VERSION 5.8 ;
BUSBITCHARS "[]" ;
DIVIDERCHAR "/" ;
UNITS
    DATABASE MICRONS 1000 ;
END UNITS

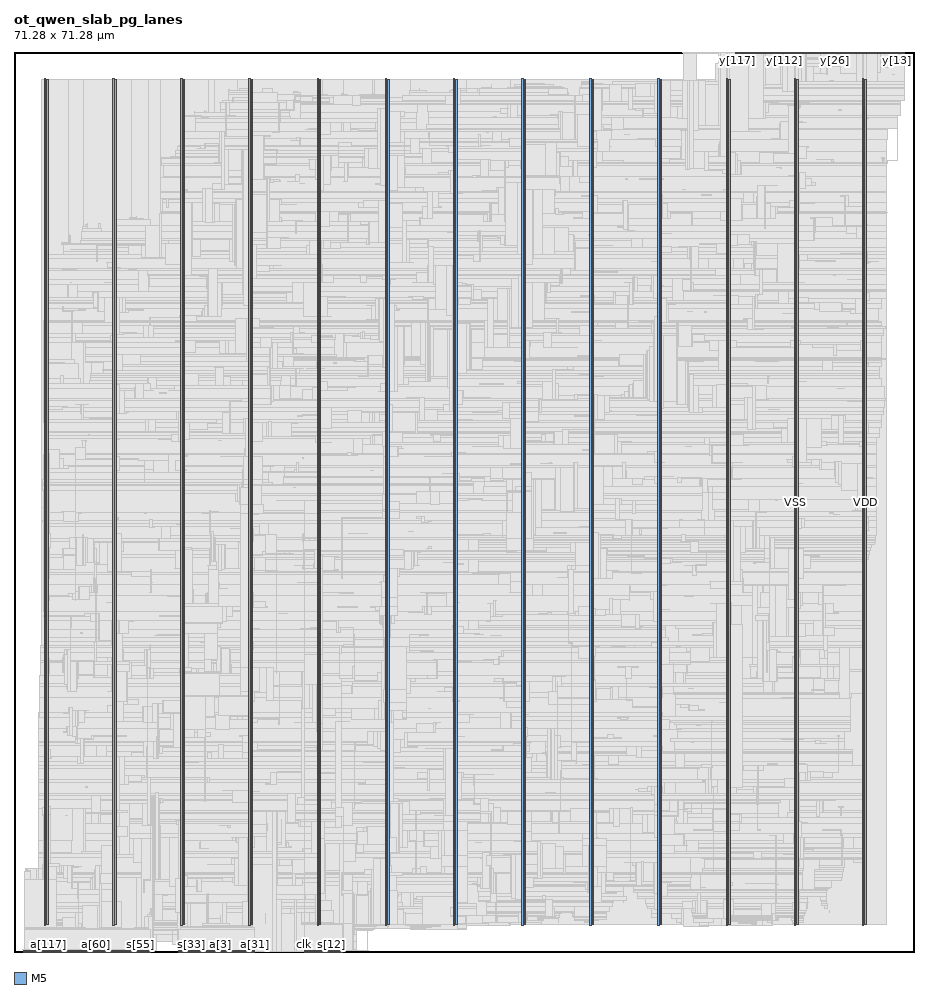
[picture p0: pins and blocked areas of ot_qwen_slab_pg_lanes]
MACRO ot_qwen_slab_pg_lanes
  FOREIGN ot_qwen_slab_pg_lanes 0 0 ;
  CLASS BLOCK ;
  SIZE 71.28 BY 71.28 ;
  PIN a[0]
    DIRECTION INPUT ;
    USE SIGNAL ;
    PORT
      LAYER M5 ;
        RECT  16.08 0 16.104 0.084 ;
    END
  END a[0]
  PIN a[100]
    DIRECTION INPUT ;
    USE SIGNAL ;
    PORT
      LAYER M5 ;
        RECT  1.104 0 1.128 0.084 ;
    END
  END a[100]
  PIN a[101]
    DIRECTION INPUT ;
    USE SIGNAL ;
    PORT
      LAYER M5 ;
        RECT  1.2 0 1.224 0.084 ;
    END
  END a[101]
  PIN a[102]
    DIRECTION INPUT ;
    USE SIGNAL ;
    PORT
      LAYER M5 ;
        RECT  1.296 0 1.32 0.084 ;
    END
  END a[102]
  PIN a[103]
    DIRECTION INPUT ;
    USE SIGNAL ;
    PORT
      LAYER M5 ;
        RECT  1.392 0 1.416 0.084 ;
    END
  END a[103]
  PIN a[104]
    DIRECTION INPUT ;
    USE SIGNAL ;
    PORT
      LAYER M5 ;
        RECT  1.488 0 1.512 0.084 ;
    END
  END a[104]
  PIN a[105]
    DIRECTION INPUT ;
    USE SIGNAL ;
    PORT
      LAYER M5 ;
        RECT  1.584 0 1.608 0.084 ;
    END
  END a[105]
  PIN a[106]
    DIRECTION INPUT ;
    USE SIGNAL ;
    PORT
      LAYER M5 ;
        RECT  1.68 0 1.704 0.084 ;
    END
  END a[106]
  PIN a[107]
    DIRECTION INPUT ;
    USE SIGNAL ;
    PORT
      LAYER M5 ;
        RECT  1.776 0 1.8 0.084 ;
    END
  END a[107]
  PIN a[108]
    DIRECTION INPUT ;
    USE SIGNAL ;
    PORT
      LAYER M5 ;
        RECT  1.872 0 1.896 0.084 ;
    END
  END a[108]
  PIN a[109]
    DIRECTION INPUT ;
    USE SIGNAL ;
    PORT
      LAYER M5 ;
        RECT  1.968 0 1.992 0.084 ;
    END
  END a[109]
  PIN a[10]
    DIRECTION INPUT ;
    USE SIGNAL ;
    PORT
      LAYER M5 ;
        RECT  17.04 0 17.064 0.084 ;
    END
  END a[10]
  PIN a[110]
    DIRECTION INPUT ;
    USE SIGNAL ;
    PORT
      LAYER M5 ;
        RECT  2.064 0 2.088 0.084 ;
    END
  END a[110]
  PIN a[111]
    DIRECTION INPUT ;
    USE SIGNAL ;
    PORT
      LAYER M5 ;
        RECT  2.16 0 2.184 0.084 ;
    END
  END a[111]
  PIN a[112]
    DIRECTION INPUT ;
    USE SIGNAL ;
    PORT
      LAYER M5 ;
        RECT  2.256 0 2.28 0.084 ;
    END
  END a[112]
  PIN a[113]
    DIRECTION INPUT ;
    USE SIGNAL ;
    PORT
      LAYER M5 ;
        RECT  2.352 0 2.376 0.084 ;
    END
  END a[113]
  PIN a[114]
    DIRECTION INPUT ;
    USE SIGNAL ;
    PORT
      LAYER M5 ;
        RECT  2.448 0 2.472 0.084 ;
    END
  END a[114]
  PIN a[115]
    DIRECTION INPUT ;
    USE SIGNAL ;
    PORT
      LAYER M5 ;
        RECT  2.544 0 2.568 0.084 ;
    END
  END a[115]
  PIN a[116]
    DIRECTION INPUT ;
    USE SIGNAL ;
    PORT
      LAYER M5 ;
        RECT  2.64 0 2.664 0.084 ;
    END
  END a[116]
  PIN a[117]
    DIRECTION INPUT ;
    USE SIGNAL ;
    PORT
      LAYER M5 ;
        RECT  2.736 0 2.76 0.084 ;
    END
  END a[117]
  PIN a[118]
    DIRECTION INPUT ;
    USE SIGNAL ;
    PORT
      LAYER M5 ;
        RECT  2.832 0 2.856 0.084 ;
    END
  END a[118]
  PIN a[119]
    DIRECTION INPUT ;
    USE SIGNAL ;
    PORT
      LAYER M5 ;
        RECT  2.928 0 2.952 0.084 ;
    END
  END a[119]
  PIN a[11]
    DIRECTION INPUT ;
    USE SIGNAL ;
    PORT
      LAYER M5 ;
        RECT  17.136 0 17.16 0.084 ;
    END
  END a[11]
  PIN a[120]
    DIRECTION INPUT ;
    USE SIGNAL ;
    PORT
      LAYER M5 ;
        RECT  3.024 0 3.048 0.084 ;
    END
  END a[120]
  PIN a[121]
    DIRECTION INPUT ;
    USE SIGNAL ;
    PORT
      LAYER M5 ;
        RECT  3.12 0 3.144 0.084 ;
    END
  END a[121]
  PIN a[122]
    DIRECTION INPUT ;
    USE SIGNAL ;
    PORT
      LAYER M5 ;
        RECT  3.216 0 3.24 0.084 ;
    END
  END a[122]
  PIN a[123]
    DIRECTION INPUT ;
    USE SIGNAL ;
    PORT
      LAYER M5 ;
        RECT  3.312 0 3.336 0.084 ;
    END
  END a[123]
  PIN a[124]
    DIRECTION INPUT ;
    USE SIGNAL ;
    PORT
      LAYER M5 ;
        RECT  3.408 0 3.432 0.084 ;
    END
  END a[124]
  PIN a[125]
    DIRECTION INPUT ;
    USE SIGNAL ;
    PORT
      LAYER M5 ;
        RECT  3.504 0 3.528 0.084 ;
    END
  END a[125]
  PIN a[126]
    DIRECTION INPUT ;
    USE SIGNAL ;
    PORT
      LAYER M5 ;
        RECT  3.6 0 3.624 0.084 ;
    END
  END a[126]
  PIN a[127]
    DIRECTION INPUT ;
    USE SIGNAL ;
    PORT
      LAYER M5 ;
        RECT  3.696 0 3.72 0.084 ;
    END
  END a[127]
  PIN a[12]
    DIRECTION INPUT ;
    USE SIGNAL ;
    PORT
      LAYER M5 ;
        RECT  17.232 0 17.256 0.084 ;
    END
  END a[12]
  PIN a[13]
    DIRECTION INPUT ;
    USE SIGNAL ;
    PORT
      LAYER M5 ;
        RECT  17.328 0 17.352 0.084 ;
    END
  END a[13]
  PIN a[14]
    DIRECTION INPUT ;
    USE SIGNAL ;
    PORT
      LAYER M5 ;
        RECT  17.424 0 17.448 0.084 ;
    END
  END a[14]
  PIN a[15]
    DIRECTION INPUT ;
    USE SIGNAL ;
    PORT
      LAYER M5 ;
        RECT  17.52 0 17.544 0.084 ;
    END
  END a[15]
  PIN a[16]
    DIRECTION INPUT ;
    USE SIGNAL ;
    PORT
      LAYER M5 ;
        RECT  17.616 0 17.64 0.084 ;
    END
  END a[16]
  PIN a[17]
    DIRECTION INPUT ;
    USE SIGNAL ;
    PORT
      LAYER M5 ;
        RECT  17.712 0 17.736 0.084 ;
    END
  END a[17]
  PIN a[18]
    DIRECTION INPUT ;
    USE SIGNAL ;
    PORT
      LAYER M5 ;
        RECT  17.808 0 17.832 0.084 ;
    END
  END a[18]
  PIN a[19]
    DIRECTION INPUT ;
    USE SIGNAL ;
    PORT
      LAYER M5 ;
        RECT  17.904 0 17.928 0.084 ;
    END
  END a[19]
  PIN a[1]
    DIRECTION INPUT ;
    USE SIGNAL ;
    PORT
      LAYER M5 ;
        RECT  16.176 0 16.2 0.084 ;
    END
  END a[1]
  PIN a[20]
    DIRECTION INPUT ;
    USE SIGNAL ;
    PORT
      LAYER M5 ;
        RECT  18 0 18.024 0.084 ;
    END
  END a[20]
  PIN a[21]
    DIRECTION INPUT ;
    USE SIGNAL ;
    PORT
      LAYER M5 ;
        RECT  18.096 0 18.12 0.084 ;
    END
  END a[21]
  PIN a[22]
    DIRECTION INPUT ;
    USE SIGNAL ;
    PORT
      LAYER M5 ;
        RECT  18.192 0 18.216 0.084 ;
    END
  END a[22]
  PIN a[23]
    DIRECTION INPUT ;
    USE SIGNAL ;
    PORT
      LAYER M5 ;
        RECT  18.288 0 18.312 0.084 ;
    END
  END a[23]
  PIN a[24]
    DIRECTION INPUT ;
    USE SIGNAL ;
    PORT
      LAYER M5 ;
        RECT  18.384 0 18.408 0.084 ;
    END
  END a[24]
  PIN a[25]
    DIRECTION INPUT ;
    USE SIGNAL ;
    PORT
      LAYER M5 ;
        RECT  18.48 0 18.504 0.084 ;
    END
  END a[25]
  PIN a[26]
    DIRECTION INPUT ;
    USE SIGNAL ;
    PORT
      LAYER M5 ;
        RECT  18.576 0 18.6 0.084 ;
    END
  END a[26]
  PIN a[27]
    DIRECTION INPUT ;
    USE SIGNAL ;
    PORT
      LAYER M5 ;
        RECT  18.672 0 18.696 0.084 ;
    END
  END a[27]
  PIN a[28]
    DIRECTION INPUT ;
    USE SIGNAL ;
    PORT
      LAYER M5 ;
        RECT  18.768 0 18.792 0.084 ;
    END
  END a[28]
  PIN a[29]
    DIRECTION INPUT ;
    USE SIGNAL ;
    PORT
      LAYER M5 ;
        RECT  18.864 0 18.888 0.084 ;
    END
  END a[29]
  PIN a[2]
    DIRECTION INPUT ;
    USE SIGNAL ;
    PORT
      LAYER M5 ;
        RECT  16.272 0 16.296 0.084 ;
    END
  END a[2]
  PIN a[30]
    DIRECTION INPUT ;
    USE SIGNAL ;
    PORT
      LAYER M5 ;
        RECT  18.96 0 18.984 0.084 ;
    END
  END a[30]
  PIN a[31]
    DIRECTION INPUT ;
    USE SIGNAL ;
    PORT
      LAYER M5 ;
        RECT  19.056 0 19.08 0.084 ;
    END
  END a[31]
  PIN a[32]
    DIRECTION INPUT ;
    USE SIGNAL ;
    PORT
      LAYER M5 ;
        RECT  3.792 0 3.816 0.084 ;
    END
  END a[32]
  PIN a[33]
    DIRECTION INPUT ;
    USE SIGNAL ;
    PORT
      LAYER M5 ;
        RECT  3.888 0 3.912 0.084 ;
    END
  END a[33]
  PIN a[34]
    DIRECTION INPUT ;
    USE SIGNAL ;
    PORT
      LAYER M5 ;
        RECT  3.984 0 4.008 0.084 ;
    END
  END a[34]
  PIN a[35]
    DIRECTION INPUT ;
    USE SIGNAL ;
    PORT
      LAYER M5 ;
        RECT  4.08 0 4.104 0.084 ;
    END
  END a[35]
  PIN a[36]
    DIRECTION INPUT ;
    USE SIGNAL ;
    PORT
      LAYER M5 ;
        RECT  4.176 0 4.2 0.084 ;
    END
  END a[36]
  PIN a[37]
    DIRECTION INPUT ;
    USE SIGNAL ;
    PORT
      LAYER M5 ;
        RECT  4.272 0 4.296 0.084 ;
    END
  END a[37]
  PIN a[38]
    DIRECTION INPUT ;
    USE SIGNAL ;
    PORT
      LAYER M5 ;
        RECT  4.368 0 4.392 0.084 ;
    END
  END a[38]
  PIN a[39]
    DIRECTION INPUT ;
    USE SIGNAL ;
    PORT
      LAYER M5 ;
        RECT  4.464 0 4.488 0.084 ;
    END
  END a[39]
  PIN a[3]
    DIRECTION INPUT ;
    USE SIGNAL ;
    PORT
      LAYER M5 ;
        RECT  16.368 0 16.392 0.084 ;
    END
  END a[3]
  PIN a[40]
    DIRECTION INPUT ;
    USE SIGNAL ;
    PORT
      LAYER M5 ;
        RECT  4.56 0 4.584 0.084 ;
    END
  END a[40]
  PIN a[41]
    DIRECTION INPUT ;
    USE SIGNAL ;
    PORT
      LAYER M5 ;
        RECT  4.656 0 4.68 0.084 ;
    END
  END a[41]
  PIN a[42]
    DIRECTION INPUT ;
    USE SIGNAL ;
    PORT
      LAYER M5 ;
        RECT  4.752 0 4.776 0.084 ;
    END
  END a[42]
  PIN a[43]
    DIRECTION INPUT ;
    USE SIGNAL ;
    PORT
      LAYER M5 ;
        RECT  4.848 0 4.872 0.084 ;
    END
  END a[43]
  PIN a[44]
    DIRECTION INPUT ;
    USE SIGNAL ;
    PORT
      LAYER M5 ;
        RECT  4.944 0 4.968 0.084 ;
    END
  END a[44]
  PIN a[45]
    DIRECTION INPUT ;
    USE SIGNAL ;
    PORT
      LAYER M5 ;
        RECT  5.04 0 5.064 0.084 ;
    END
  END a[45]
  PIN a[46]
    DIRECTION INPUT ;
    USE SIGNAL ;
    PORT
      LAYER M5 ;
        RECT  5.136 0 5.16 0.084 ;
    END
  END a[46]
  PIN a[47]
    DIRECTION INPUT ;
    USE SIGNAL ;
    PORT
      LAYER M5 ;
        RECT  5.232 0 5.256 0.084 ;
    END
  END a[47]
  PIN a[48]
    DIRECTION INPUT ;
    USE SIGNAL ;
    PORT
      LAYER M5 ;
        RECT  5.328 0 5.352 0.084 ;
    END
  END a[48]
  PIN a[49]
    DIRECTION INPUT ;
    USE SIGNAL ;
    PORT
      LAYER M5 ;
        RECT  5.424 0 5.448 0.084 ;
    END
  END a[49]
  PIN a[4]
    DIRECTION INPUT ;
    USE SIGNAL ;
    PORT
      LAYER M5 ;
        RECT  16.464 0 16.488 0.084 ;
    END
  END a[4]
  PIN a[50]
    DIRECTION INPUT ;
    USE SIGNAL ;
    PORT
      LAYER M5 ;
        RECT  5.52 0 5.544 0.084 ;
    END
  END a[50]
  PIN a[51]
    DIRECTION INPUT ;
    USE SIGNAL ;
    PORT
      LAYER M5 ;
        RECT  5.616 0 5.64 0.084 ;
    END
  END a[51]
  PIN a[52]
    DIRECTION INPUT ;
    USE SIGNAL ;
    PORT
      LAYER M5 ;
        RECT  5.712 0 5.736 0.084 ;
    END
  END a[52]
  PIN a[53]
    DIRECTION INPUT ;
    USE SIGNAL ;
    PORT
      LAYER M5 ;
        RECT  5.808 0 5.832 0.084 ;
    END
  END a[53]
  PIN a[54]
    DIRECTION INPUT ;
    USE SIGNAL ;
    PORT
      LAYER M5 ;
        RECT  5.904 0 5.928 0.084 ;
    END
  END a[54]
  PIN a[55]
    DIRECTION INPUT ;
    USE SIGNAL ;
    PORT
      LAYER M5 ;
        RECT  6 0 6.024 0.084 ;
    END
  END a[55]
  PIN a[56]
    DIRECTION INPUT ;
    USE SIGNAL ;
    PORT
      LAYER M5 ;
        RECT  6.096 0 6.12 0.084 ;
    END
  END a[56]
  PIN a[57]
    DIRECTION INPUT ;
    USE SIGNAL ;
    PORT
      LAYER M5 ;
        RECT  6.192 0 6.216 0.084 ;
    END
  END a[57]
  PIN a[58]
    DIRECTION INPUT ;
    USE SIGNAL ;
    PORT
      LAYER M5 ;
        RECT  6.288 0 6.312 0.084 ;
    END
  END a[58]
  PIN a[59]
    DIRECTION INPUT ;
    USE SIGNAL ;
    PORT
      LAYER M5 ;
        RECT  6.384 0 6.408 0.084 ;
    END
  END a[59]
  PIN a[5]
    DIRECTION INPUT ;
    USE SIGNAL ;
    PORT
      LAYER M5 ;
        RECT  16.56 0 16.584 0.084 ;
    END
  END a[5]
  PIN a[60]
    DIRECTION INPUT ;
    USE SIGNAL ;
    PORT
      LAYER M5 ;
        RECT  6.48 0 6.504 0.084 ;
    END
  END a[60]
  PIN a[61]
    DIRECTION INPUT ;
    USE SIGNAL ;
    PORT
      LAYER M5 ;
        RECT  6.576 0 6.6 0.084 ;
    END
  END a[61]
  PIN a[62]
    DIRECTION INPUT ;
    USE SIGNAL ;
    PORT
      LAYER M5 ;
        RECT  6.672 0 6.696 0.084 ;
    END
  END a[62]
  PIN a[63]
    DIRECTION INPUT ;
    USE SIGNAL ;
    PORT
      LAYER M5 ;
        RECT  6.768 0 6.792 0.084 ;
    END
  END a[63]
  PIN a[64]
    DIRECTION INPUT ;
    USE SIGNAL ;
    PORT
      LAYER M5 ;
        RECT  6.864 0 6.888 0.084 ;
    END
  END a[64]
  PIN a[65]
    DIRECTION INPUT ;
    USE SIGNAL ;
    PORT
      LAYER M5 ;
        RECT  6.96 0 6.984 0.084 ;
    END
  END a[65]
  PIN a[66]
    DIRECTION INPUT ;
    USE SIGNAL ;
    PORT
      LAYER M5 ;
        RECT  7.056 0 7.08 0.084 ;
    END
  END a[66]
  PIN a[67]
    DIRECTION INPUT ;
    USE SIGNAL ;
    PORT
      LAYER M5 ;
        RECT  7.152 0 7.176 0.084 ;
    END
  END a[67]
  PIN a[68]
    DIRECTION INPUT ;
    USE SIGNAL ;
    PORT
      LAYER M5 ;
        RECT  7.248 0 7.272 0.084 ;
    END
  END a[68]
  PIN a[69]
    DIRECTION INPUT ;
    USE SIGNAL ;
    PORT
      LAYER M5 ;
        RECT  7.344 0 7.368 0.084 ;
    END
  END a[69]
  PIN a[6]
    DIRECTION INPUT ;
    USE SIGNAL ;
    PORT
      LAYER M5 ;
        RECT  16.656 0 16.68 0.084 ;
    END
  END a[6]
  PIN a[70]
    DIRECTION INPUT ;
    USE SIGNAL ;
    PORT
      LAYER M5 ;
        RECT  7.44 0 7.464 0.084 ;
    END
  END a[70]
  PIN a[71]
    DIRECTION INPUT ;
    USE SIGNAL ;
    PORT
      LAYER M5 ;
        RECT  7.536 0 7.56 0.084 ;
    END
  END a[71]
  PIN a[72]
    DIRECTION INPUT ;
    USE SIGNAL ;
    PORT
      LAYER M5 ;
        RECT  7.632 0 7.656 0.084 ;
    END
  END a[72]
  PIN a[73]
    DIRECTION INPUT ;
    USE SIGNAL ;
    PORT
      LAYER M5 ;
        RECT  7.728 0 7.752 0.084 ;
    END
  END a[73]
  PIN a[74]
    DIRECTION INPUT ;
    USE SIGNAL ;
    PORT
      LAYER M5 ;
        RECT  7.824 0 7.848 0.084 ;
    END
  END a[74]
  PIN a[75]
    DIRECTION INPUT ;
    USE SIGNAL ;
    PORT
      LAYER M5 ;
        RECT  7.92 0 7.944 0.084 ;
    END
  END a[75]
  PIN a[76]
    DIRECTION INPUT ;
    USE SIGNAL ;
    PORT
      LAYER M5 ;
        RECT  8.016 0 8.04 0.084 ;
    END
  END a[76]
  PIN a[77]
    DIRECTION INPUT ;
    USE SIGNAL ;
    PORT
      LAYER M5 ;
        RECT  8.112 0 8.136 0.084 ;
    END
  END a[77]
  PIN a[78]
    DIRECTION INPUT ;
    USE SIGNAL ;
    PORT
      LAYER M5 ;
        RECT  8.208 0 8.232 0.084 ;
    END
  END a[78]
  PIN a[79]
    DIRECTION INPUT ;
    USE SIGNAL ;
    PORT
      LAYER M5 ;
        RECT  8.304 0 8.328 0.084 ;
    END
  END a[79]
  PIN a[7]
    DIRECTION INPUT ;
    USE SIGNAL ;
    PORT
      LAYER M5 ;
        RECT  16.752 0 16.776 0.084 ;
    END
  END a[7]
  PIN a[80]
    DIRECTION INPUT ;
    USE SIGNAL ;
    PORT
      LAYER M5 ;
        RECT  8.4 0 8.424 0.084 ;
    END
  END a[80]
  PIN a[81]
    DIRECTION INPUT ;
    USE SIGNAL ;
    PORT
      LAYER M5 ;
        RECT  8.496 0 8.52 0.084 ;
    END
  END a[81]
  PIN a[82]
    DIRECTION INPUT ;
    USE SIGNAL ;
    PORT
      LAYER M5 ;
        RECT  8.592 0 8.616 0.084 ;
    END
  END a[82]
  PIN a[83]
    DIRECTION INPUT ;
    USE SIGNAL ;
    PORT
      LAYER M5 ;
        RECT  8.688 0 8.712 0.084 ;
    END
  END a[83]
  PIN a[84]
    DIRECTION INPUT ;
    USE SIGNAL ;
    PORT
      LAYER M5 ;
        RECT  8.784 0 8.808 0.084 ;
    END
  END a[84]
  PIN a[85]
    DIRECTION INPUT ;
    USE SIGNAL ;
    PORT
      LAYER M5 ;
        RECT  8.88 0 8.904 0.084 ;
    END
  END a[85]
  PIN a[86]
    DIRECTION INPUT ;
    USE SIGNAL ;
    PORT
      LAYER M5 ;
        RECT  8.976 0 9 0.084 ;
    END
  END a[86]
  PIN a[87]
    DIRECTION INPUT ;
    USE SIGNAL ;
    PORT
      LAYER M5 ;
        RECT  9.072 0 9.096 0.084 ;
    END
  END a[87]
  PIN a[88]
    DIRECTION INPUT ;
    USE SIGNAL ;
    PORT
      LAYER M5 ;
        RECT  9.168 0 9.192 0.084 ;
    END
  END a[88]
  PIN a[89]
    DIRECTION INPUT ;
    USE SIGNAL ;
    PORT
      LAYER M5 ;
        RECT  9.264 0 9.288 0.084 ;
    END
  END a[89]
  PIN a[8]
    DIRECTION INPUT ;
    USE SIGNAL ;
    PORT
      LAYER M5 ;
        RECT  16.848 0 16.872 0.084 ;
    END
  END a[8]
  PIN a[90]
    DIRECTION INPUT ;
    USE SIGNAL ;
    PORT
      LAYER M5 ;
        RECT  9.36 0 9.384 0.084 ;
    END
  END a[90]
  PIN a[91]
    DIRECTION INPUT ;
    USE SIGNAL ;
    PORT
      LAYER M5 ;
        RECT  9.456 0 9.48 0.084 ;
    END
  END a[91]
  PIN a[92]
    DIRECTION INPUT ;
    USE SIGNAL ;
    PORT
      LAYER M5 ;
        RECT  9.552 0 9.576 0.084 ;
    END
  END a[92]
  PIN a[93]
    DIRECTION INPUT ;
    USE SIGNAL ;
    PORT
      LAYER M5 ;
        RECT  9.648 0 9.672 0.084 ;
    END
  END a[93]
  PIN a[94]
    DIRECTION INPUT ;
    USE SIGNAL ;
    PORT
      LAYER M5 ;
        RECT  9.744 0 9.768 0.084 ;
    END
  END a[94]
  PIN a[95]
    DIRECTION INPUT ;
    USE SIGNAL ;
    PORT
      LAYER M5 ;
        RECT  9.84 0 9.864 0.084 ;
    END
  END a[95]
  PIN a[96]
    DIRECTION INPUT ;
    USE SIGNAL ;
    PORT
      LAYER M5 ;
        RECT  0.72 0 0.744 0.084 ;
    END
  END a[96]
  PIN a[97]
    DIRECTION INPUT ;
    USE SIGNAL ;
    PORT
      LAYER M5 ;
        RECT  0.816 0 0.84 0.084 ;
    END
  END a[97]
  PIN a[98]
    DIRECTION INPUT ;
    USE SIGNAL ;
    PORT
      LAYER M5 ;
        RECT  0.912 0 0.936 0.084 ;
    END
  END a[98]
  PIN a[99]
    DIRECTION INPUT ;
    USE SIGNAL ;
    PORT
      LAYER M5 ;
        RECT  1.008 0 1.032 0.084 ;
    END
  END a[99]
  PIN a[9]
    DIRECTION INPUT ;
    USE SIGNAL ;
    PORT
      LAYER M5 ;
        RECT  16.944 0 16.968 0.084 ;
    END
  END a[9]
  PIN clk
    DIRECTION INPUT ;
    USE SIGNAL ;
    PORT
      LAYER M5 ;
        RECT  22.992 0 23.016 0.084 ;
    END
  END clk
  PIN err[0]
    DIRECTION OUTPUT ;
    USE SIGNAL ;
    PORT
      LAYER M5 ;
        RECT  67.536 71.196 67.56 71.28 ;
    END
  END err[0]
  PIN err[1]
    DIRECTION OUTPUT ;
    USE SIGNAL ;
    PORT
      LAYER M5 ;
        RECT  67.632 71.196 67.656 71.28 ;
    END
  END err[1]
  PIN err[2]
    DIRECTION OUTPUT ;
    USE SIGNAL ;
    PORT
      LAYER M5 ;
        RECT  67.728 71.196 67.752 71.28 ;
    END
  END err[2]
  PIN err[3]
    DIRECTION OUTPUT ;
    USE SIGNAL ;
    PORT
      LAYER M5 ;
        RECT  67.824 71.196 67.848 71.28 ;
    END
  END err[3]
  PIN err[4]
    DIRECTION OUTPUT ;
    USE SIGNAL ;
    PORT
      LAYER M5 ;
        RECT  67.92 71.196 67.944 71.28 ;
    END
  END err[4]
  PIN err[5]
    DIRECTION OUTPUT ;
    USE SIGNAL ;
    PORT
      LAYER M5 ;
        RECT  68.016 71.196 68.04 71.28 ;
    END
  END err[5]
  PIN err[6]
    DIRECTION OUTPUT ;
    USE SIGNAL ;
    PORT
      LAYER M5 ;
        RECT  68.112 71.196 68.136 71.28 ;
    END
  END err[6]
  PIN err[7]
    DIRECTION OUTPUT ;
    USE SIGNAL ;
    PORT
      LAYER M5 ;
        RECT  68.208 71.196 68.232 71.28 ;
    END
  END err[7]
  PIN l_v[0]
    DIRECTION INPUT ;
    USE SIGNAL ;
    PORT
      LAYER M5 ;
        RECT  23.088 0 23.112 0.084 ;
    END
  END l_v[0]
  PIN l_v[1]
    DIRECTION INPUT ;
    USE SIGNAL ;
    PORT
      LAYER M5 ;
        RECT  23.184 0 23.208 0.084 ;
    END
  END l_v[1]
  PIN l_v[2]
    DIRECTION INPUT ;
    USE SIGNAL ;
    PORT
      LAYER M5 ;
        RECT  23.28 0 23.304 0.084 ;
    END
  END l_v[2]
  PIN l_v[3]
    DIRECTION INPUT ;
    USE SIGNAL ;
    PORT
      LAYER M5 ;
        RECT  23.376 0 23.4 0.084 ;
    END
  END l_v[3]
  PIN l_ws[0]
    DIRECTION INPUT ;
    USE SIGNAL ;
    PORT
      LAYER M5 ;
        RECT  23.472 0 23.496 0.084 ;
    END
  END l_ws[0]
  PIN l_ws[1]
    DIRECTION INPUT ;
    USE SIGNAL ;
    PORT
      LAYER M5 ;
        RECT  23.568 0 23.592 0.084 ;
    END
  END l_ws[1]
  PIN l_ws[2]
    DIRECTION INPUT ;
    USE SIGNAL ;
    PORT
      LAYER M5 ;
        RECT  23.664 0 23.688 0.084 ;
    END
  END l_ws[2]
  PIN l_ws[3]
    DIRECTION INPUT ;
    USE SIGNAL ;
    PORT
      LAYER M5 ;
        RECT  23.76 0 23.784 0.084 ;
    END
  END l_ws[3]
  PIN rs0
    DIRECTION INPUT ;
    USE SIGNAL ;
    PORT
      LAYER M5 ;
        RECT  23.856 0 23.88 0.084 ;
    END
  END rs0
  PIN s[0]
    DIRECTION INPUT ;
    USE SIGNAL ;
    PORT
      LAYER M5 ;
        RECT  23.952 0 23.976 0.084 ;
    END
  END s[0]
  PIN s[10]
    DIRECTION INPUT ;
    USE SIGNAL ;
    PORT
      LAYER M5 ;
        RECT  24.912 0 24.936 0.084 ;
    END
  END s[10]
  PIN s[11]
    DIRECTION INPUT ;
    USE SIGNAL ;
    PORT
      LAYER M5 ;
        RECT  25.008 0 25.032 0.084 ;
    END
  END s[11]
  PIN s[12]
    DIRECTION INPUT ;
    USE SIGNAL ;
    PORT
      LAYER M5 ;
        RECT  25.104 0 25.128 0.084 ;
    END
  END s[12]
  PIN s[13]
    DIRECTION INPUT ;
    USE SIGNAL ;
    PORT
      LAYER M5 ;
        RECT  25.2 0 25.224 0.084 ;
    END
  END s[13]
  PIN s[14]
    DIRECTION INPUT ;
    USE SIGNAL ;
    PORT
      LAYER M5 ;
        RECT  25.296 0 25.32 0.084 ;
    END
  END s[14]
  PIN s[15]
    DIRECTION INPUT ;
    USE SIGNAL ;
    PORT
      LAYER M5 ;
        RECT  25.392 0 25.416 0.084 ;
    END
  END s[15]
  PIN s[16]
    DIRECTION INPUT ;
    USE SIGNAL ;
    PORT
      LAYER M5 ;
        RECT  25.488 0 25.512 0.084 ;
    END
  END s[16]
  PIN s[17]
    DIRECTION INPUT ;
    USE SIGNAL ;
    PORT
      LAYER M5 ;
        RECT  25.584 0 25.608 0.084 ;
    END
  END s[17]
  PIN s[18]
    DIRECTION INPUT ;
    USE SIGNAL ;
    PORT
      LAYER M5 ;
        RECT  25.68 0 25.704 0.084 ;
    END
  END s[18]
  PIN s[19]
    DIRECTION INPUT ;
    USE SIGNAL ;
    PORT
      LAYER M5 ;
        RECT  25.776 0 25.8 0.084 ;
    END
  END s[19]
  PIN s[1]
    DIRECTION INPUT ;
    USE SIGNAL ;
    PORT
      LAYER M5 ;
        RECT  24.048 0 24.072 0.084 ;
    END
  END s[1]
  PIN s[20]
    DIRECTION INPUT ;
    USE SIGNAL ;
    PORT
      LAYER M5 ;
        RECT  25.872 0 25.896 0.084 ;
    END
  END s[20]
  PIN s[21]
    DIRECTION INPUT ;
    USE SIGNAL ;
    PORT
      LAYER M5 ;
        RECT  25.968 0 25.992 0.084 ;
    END
  END s[21]
  PIN s[22]
    DIRECTION INPUT ;
    USE SIGNAL ;
    PORT
      LAYER M5 ;
        RECT  13.008 0 13.032 0.084 ;
    END
  END s[22]
  PIN s[23]
    DIRECTION INPUT ;
    USE SIGNAL ;
    PORT
      LAYER M5 ;
        RECT  13.104 0 13.128 0.084 ;
    END
  END s[23]
  PIN s[24]
    DIRECTION INPUT ;
    USE SIGNAL ;
    PORT
      LAYER M5 ;
        RECT  13.2 0 13.224 0.084 ;
    END
  END s[24]
  PIN s[25]
    DIRECTION INPUT ;
    USE SIGNAL ;
    PORT
      LAYER M5 ;
        RECT  13.296 0 13.32 0.084 ;
    END
  END s[25]
  PIN s[26]
    DIRECTION INPUT ;
    USE SIGNAL ;
    PORT
      LAYER M5 ;
        RECT  13.392 0 13.416 0.084 ;
    END
  END s[26]
  PIN s[27]
    DIRECTION INPUT ;
    USE SIGNAL ;
    PORT
      LAYER M5 ;
        RECT  13.488 0 13.512 0.084 ;
    END
  END s[27]
  PIN s[28]
    DIRECTION INPUT ;
    USE SIGNAL ;
    PORT
      LAYER M5 ;
        RECT  13.584 0 13.608 0.084 ;
    END
  END s[28]
  PIN s[29]
    DIRECTION INPUT ;
    USE SIGNAL ;
    PORT
      LAYER M5 ;
        RECT  13.68 0 13.704 0.084 ;
    END
  END s[29]
  PIN s[2]
    DIRECTION INPUT ;
    USE SIGNAL ;
    PORT
      LAYER M5 ;
        RECT  24.144 0 24.168 0.084 ;
    END
  END s[2]
  PIN s[30]
    DIRECTION INPUT ;
    USE SIGNAL ;
    PORT
      LAYER M5 ;
        RECT  13.776 0 13.8 0.084 ;
    END
  END s[30]
  PIN s[31]
    DIRECTION INPUT ;
    USE SIGNAL ;
    PORT
      LAYER M5 ;
        RECT  13.872 0 13.896 0.084 ;
    END
  END s[31]
  PIN s[32]
    DIRECTION INPUT ;
    USE SIGNAL ;
    PORT
      LAYER M5 ;
        RECT  13.968 0 13.992 0.084 ;
    END
  END s[32]
  PIN s[33]
    DIRECTION INPUT ;
    USE SIGNAL ;
    PORT
      LAYER M5 ;
        RECT  14.064 0 14.088 0.084 ;
    END
  END s[33]
  PIN s[34]
    DIRECTION INPUT ;
    USE SIGNAL ;
    PORT
      LAYER M5 ;
        RECT  14.16 0 14.184 0.084 ;
    END
  END s[34]
  PIN s[35]
    DIRECTION INPUT ;
    USE SIGNAL ;
    PORT
      LAYER M5 ;
        RECT  14.256 0 14.28 0.084 ;
    END
  END s[35]
  PIN s[36]
    DIRECTION INPUT ;
    USE SIGNAL ;
    PORT
      LAYER M5 ;
        RECT  14.352 0 14.376 0.084 ;
    END
  END s[36]
  PIN s[37]
    DIRECTION INPUT ;
    USE SIGNAL ;
    PORT
      LAYER M5 ;
        RECT  14.448 0 14.472 0.084 ;
    END
  END s[37]
  PIN s[38]
    DIRECTION INPUT ;
    USE SIGNAL ;
    PORT
      LAYER M5 ;
        RECT  14.544 0 14.568 0.084 ;
    END
  END s[38]
  PIN s[39]
    DIRECTION INPUT ;
    USE SIGNAL ;
    PORT
      LAYER M5 ;
        RECT  14.64 0 14.664 0.084 ;
    END
  END s[39]
  PIN s[3]
    DIRECTION INPUT ;
    USE SIGNAL ;
    PORT
      LAYER M5 ;
        RECT  24.24 0 24.264 0.084 ;
    END
  END s[3]
  PIN s[40]
    DIRECTION INPUT ;
    USE SIGNAL ;
    PORT
      LAYER M5 ;
        RECT  14.736 0 14.76 0.084 ;
    END
  END s[40]
  PIN s[41]
    DIRECTION INPUT ;
    USE SIGNAL ;
    PORT
      LAYER M5 ;
        RECT  14.832 0 14.856 0.084 ;
    END
  END s[41]
  PIN s[42]
    DIRECTION INPUT ;
    USE SIGNAL ;
    PORT
      LAYER M5 ;
        RECT  14.928 0 14.952 0.084 ;
    END
  END s[42]
  PIN s[43]
    DIRECTION INPUT ;
    USE SIGNAL ;
    PORT
      LAYER M5 ;
        RECT  15.024 0 15.048 0.084 ;
    END
  END s[43]
  PIN s[44]
    DIRECTION INPUT ;
    USE SIGNAL ;
    PORT
      LAYER M5 ;
        RECT  15.12 0 15.144 0.084 ;
    END
  END s[44]
  PIN s[45]
    DIRECTION INPUT ;
    USE SIGNAL ;
    PORT
      LAYER M5 ;
        RECT  15.216 0 15.24 0.084 ;
    END
  END s[45]
  PIN s[46]
    DIRECTION INPUT ;
    USE SIGNAL ;
    PORT
      LAYER M5 ;
        RECT  15.312 0 15.336 0.084 ;
    END
  END s[46]
  PIN s[47]
    DIRECTION INPUT ;
    USE SIGNAL ;
    PORT
      LAYER M5 ;
        RECT  15.408 0 15.432 0.084 ;
    END
  END s[47]
  PIN s[48]
    DIRECTION INPUT ;
    USE SIGNAL ;
    PORT
      LAYER M5 ;
        RECT  15.504 0 15.528 0.084 ;
    END
  END s[48]
  PIN s[49]
    DIRECTION INPUT ;
    USE SIGNAL ;
    PORT
      LAYER M5 ;
        RECT  15.6 0 15.624 0.084 ;
    END
  END s[49]
  PIN s[4]
    DIRECTION INPUT ;
    USE SIGNAL ;
    PORT
      LAYER M5 ;
        RECT  24.336 0 24.36 0.084 ;
    END
  END s[4]
  PIN s[50]
    DIRECTION INPUT ;
    USE SIGNAL ;
    PORT
      LAYER M5 ;
        RECT  15.696 0 15.72 0.084 ;
    END
  END s[50]
  PIN s[51]
    DIRECTION INPUT ;
    USE SIGNAL ;
    PORT
      LAYER M5 ;
        RECT  15.792 0 15.816 0.084 ;
    END
  END s[51]
  PIN s[52]
    DIRECTION INPUT ;
    USE SIGNAL ;
    PORT
      LAYER M5 ;
        RECT  15.888 0 15.912 0.084 ;
    END
  END s[52]
  PIN s[53]
    DIRECTION INPUT ;
    USE SIGNAL ;
    PORT
      LAYER M5 ;
        RECT  15.984 0 16.008 0.084 ;
    END
  END s[53]
  PIN s[54]
    DIRECTION INPUT ;
    USE SIGNAL ;
    PORT
      LAYER M5 ;
        RECT  9.936 0 9.96 0.084 ;
    END
  END s[54]
  PIN s[55]
    DIRECTION INPUT ;
    USE SIGNAL ;
    PORT
      LAYER M5 ;
        RECT  10.032 0 10.056 0.084 ;
    END
  END s[55]
  PIN s[56]
    DIRECTION INPUT ;
    USE SIGNAL ;
    PORT
      LAYER M5 ;
        RECT  10.128 0 10.152 0.084 ;
    END
  END s[56]
  PIN s[57]
    DIRECTION INPUT ;
    USE SIGNAL ;
    PORT
      LAYER M5 ;
        RECT  10.224 0 10.248 0.084 ;
    END
  END s[57]
  PIN s[58]
    DIRECTION INPUT ;
    USE SIGNAL ;
    PORT
      LAYER M5 ;
        RECT  10.32 0 10.344 0.084 ;
    END
  END s[58]
  PIN s[59]
    DIRECTION INPUT ;
    USE SIGNAL ;
    PORT
      LAYER M5 ;
        RECT  10.416 0 10.44 0.084 ;
    END
  END s[59]
  PIN s[5]
    DIRECTION INPUT ;
    USE SIGNAL ;
    PORT
      LAYER M5 ;
        RECT  24.432 0 24.456 0.084 ;
    END
  END s[5]
  PIN s[60]
    DIRECTION INPUT ;
    USE SIGNAL ;
    PORT
      LAYER M5 ;
        RECT  10.512 0 10.536 0.084 ;
    END
  END s[60]
  PIN s[61]
    DIRECTION INPUT ;
    USE SIGNAL ;
    PORT
      LAYER M5 ;
        RECT  10.608 0 10.632 0.084 ;
    END
  END s[61]
  PIN s[62]
    DIRECTION INPUT ;
    USE SIGNAL ;
    PORT
      LAYER M5 ;
        RECT  10.704 0 10.728 0.084 ;
    END
  END s[62]
  PIN s[63]
    DIRECTION INPUT ;
    USE SIGNAL ;
    PORT
      LAYER M5 ;
        RECT  10.8 0 10.824 0.084 ;
    END
  END s[63]
  PIN s[6]
    DIRECTION INPUT ;
    USE SIGNAL ;
    PORT
      LAYER M5 ;
        RECT  24.528 0 24.552 0.084 ;
    END
  END s[6]
  PIN s[7]
    DIRECTION INPUT ;
    USE SIGNAL ;
    PORT
      LAYER M5 ;
        RECT  24.624 0 24.648 0.084 ;
    END
  END s[7]
  PIN s[8]
    DIRECTION INPUT ;
    USE SIGNAL ;
    PORT
      LAYER M5 ;
        RECT  24.72 0 24.744 0.084 ;
    END
  END s[8]
  PIN s[9]
    DIRECTION INPUT ;
    USE SIGNAL ;
    PORT
      LAYER M5 ;
        RECT  24.816 0 24.84 0.084 ;
    END
  END s[9]
  PIN vo[0]
    DIRECTION OUTPUT ;
    USE SIGNAL ;
    PORT
      LAYER M5 ;
        RECT  68.304 71.196 68.328 71.28 ;
    END
  END vo[0]
  PIN vo[1]
    DIRECTION OUTPUT ;
    USE SIGNAL ;
    PORT
      LAYER M5 ;
        RECT  68.4 71.196 68.424 71.28 ;
    END
  END vo[1]
  PIN vo[2]
    DIRECTION OUTPUT ;
    USE SIGNAL ;
    PORT
      LAYER M5 ;
        RECT  68.496 71.196 68.52 71.28 ;
    END
  END vo[2]
  PIN vo[3]
    DIRECTION OUTPUT ;
    USE SIGNAL ;
    PORT
      LAYER M5 ;
        RECT  68.592 71.196 68.616 71.28 ;
    END
  END vo[3]
  PIN y[0]
    DIRECTION OUTPUT ;
    USE SIGNAL ;
    PORT
      LAYER M5 ;
        RECT  68.688 71.196 68.712 71.28 ;
    END
  END y[0]
  PIN y[100]
    DIRECTION OUTPUT ;
    USE SIGNAL ;
    PORT
      LAYER M5 ;
        RECT  59.856 71.196 59.88 71.28 ;
    END
  END y[100]
  PIN y[101]
    DIRECTION OUTPUT ;
    USE SIGNAL ;
    PORT
      LAYER M5 ;
        RECT  59.952 71.196 59.976 71.28 ;
    END
  END y[101]
  PIN y[102]
    DIRECTION OUTPUT ;
    USE SIGNAL ;
    PORT
      LAYER M5 ;
        RECT  60.048 71.196 60.072 71.28 ;
    END
  END y[102]
  PIN y[103]
    DIRECTION OUTPUT ;
    USE SIGNAL ;
    PORT
      LAYER M5 ;
        RECT  60.144 71.196 60.168 71.28 ;
    END
  END y[103]
  PIN y[104]
    DIRECTION OUTPUT ;
    USE SIGNAL ;
    PORT
      LAYER M5 ;
        RECT  60.24 71.196 60.264 71.28 ;
    END
  END y[104]
  PIN y[105]
    DIRECTION OUTPUT ;
    USE SIGNAL ;
    PORT
      LAYER M5 ;
        RECT  60.336 71.196 60.36 71.28 ;
    END
  END y[105]
  PIN y[106]
    DIRECTION OUTPUT ;
    USE SIGNAL ;
    PORT
      LAYER M5 ;
        RECT  60.432 71.196 60.456 71.28 ;
    END
  END y[106]
  PIN y[107]
    DIRECTION OUTPUT ;
    USE SIGNAL ;
    PORT
      LAYER M5 ;
        RECT  60.528 71.196 60.552 71.28 ;
    END
  END y[107]
  PIN y[108]
    DIRECTION OUTPUT ;
    USE SIGNAL ;
    PORT
      LAYER M5 ;
        RECT  60.624 71.196 60.648 71.28 ;
    END
  END y[108]
  PIN y[109]
    DIRECTION OUTPUT ;
    USE SIGNAL ;
    PORT
      LAYER M5 ;
        RECT  60.72 71.196 60.744 71.28 ;
    END
  END y[109]
  PIN y[10]
    DIRECTION OUTPUT ;
    USE SIGNAL ;
    PORT
      LAYER M5 ;
        RECT  69.648 71.196 69.672 71.28 ;
    END
  END y[10]
  PIN y[110]
    DIRECTION OUTPUT ;
    USE SIGNAL ;
    PORT
      LAYER M5 ;
        RECT  60.816 71.196 60.84 71.28 ;
    END
  END y[110]
  PIN y[111]
    DIRECTION OUTPUT ;
    USE SIGNAL ;
    PORT
      LAYER M5 ;
        RECT  60.912 71.196 60.936 71.28 ;
    END
  END y[111]
  PIN y[112]
    DIRECTION OUTPUT ;
    USE SIGNAL ;
    PORT
      LAYER M5 ;
        RECT  61.008 71.196 61.032 71.28 ;
    END
  END y[112]
  PIN y[113]
    DIRECTION OUTPUT ;
    USE SIGNAL ;
    PORT
      LAYER M5 ;
        RECT  61.104 71.196 61.128 71.28 ;
    END
  END y[113]
  PIN y[114]
    DIRECTION OUTPUT ;
    USE SIGNAL ;
    PORT
      LAYER M5 ;
        RECT  61.2 71.196 61.224 71.28 ;
    END
  END y[114]
  PIN y[115]
    DIRECTION OUTPUT ;
    USE SIGNAL ;
    PORT
      LAYER M5 ;
        RECT  61.296 71.196 61.32 71.28 ;
    END
  END y[115]
  PIN y[116]
    DIRECTION OUTPUT ;
    USE SIGNAL ;
    PORT
      LAYER M5 ;
        RECT  57.168 71.196 57.192 71.28 ;
    END
  END y[116]
  PIN y[117]
    DIRECTION OUTPUT ;
    USE SIGNAL ;
    PORT
      LAYER M5 ;
        RECT  57.264 71.196 57.288 71.28 ;
    END
  END y[117]
  PIN y[118]
    DIRECTION OUTPUT ;
    USE SIGNAL ;
    PORT
      LAYER M5 ;
        RECT  57.36 71.196 57.384 71.28 ;
    END
  END y[118]
  PIN y[119]
    DIRECTION OUTPUT ;
    USE SIGNAL ;
    PORT
      LAYER M5 ;
        RECT  57.456 71.196 57.48 71.28 ;
    END
  END y[119]
  PIN y[11]
    DIRECTION OUTPUT ;
    USE SIGNAL ;
    PORT
      LAYER M5 ;
        RECT  69.744 71.196 69.768 71.28 ;
    END
  END y[11]
  PIN y[120]
    DIRECTION OUTPUT ;
    USE SIGNAL ;
    PORT
      LAYER M5 ;
        RECT  57.552 71.196 57.576 71.28 ;
    END
  END y[120]
  PIN y[121]
    DIRECTION OUTPUT ;
    USE SIGNAL ;
    PORT
      LAYER M5 ;
        RECT  57.648 71.196 57.672 71.28 ;
    END
  END y[121]
  PIN y[122]
    DIRECTION OUTPUT ;
    USE SIGNAL ;
    PORT
      LAYER M5 ;
        RECT  57.744 71.196 57.768 71.28 ;
    END
  END y[122]
  PIN y[123]
    DIRECTION OUTPUT ;
    USE SIGNAL ;
    PORT
      LAYER M5 ;
        RECT  57.84 71.196 57.864 71.28 ;
    END
  END y[123]
  PIN y[124]
    DIRECTION OUTPUT ;
    USE SIGNAL ;
    PORT
      LAYER M5 ;
        RECT  57.936 71.196 57.96 71.28 ;
    END
  END y[124]
  PIN y[125]
    DIRECTION OUTPUT ;
    USE SIGNAL ;
    PORT
      LAYER M5 ;
        RECT  58.032 71.196 58.056 71.28 ;
    END
  END y[125]
  PIN y[126]
    DIRECTION OUTPUT ;
    USE SIGNAL ;
    PORT
      LAYER M5 ;
        RECT  58.128 71.196 58.152 71.28 ;
    END
  END y[126]
  PIN y[127]
    DIRECTION OUTPUT ;
    USE SIGNAL ;
    PORT
      LAYER M5 ;
        RECT  58.224 71.196 58.248 71.28 ;
    END
  END y[127]
  PIN y[12]
    DIRECTION OUTPUT ;
    USE SIGNAL ;
    PORT
      LAYER M5 ;
        RECT  69.84 71.196 69.864 71.28 ;
    END
  END y[12]
  PIN y[13]
    DIRECTION OUTPUT ;
    USE SIGNAL ;
    PORT
      LAYER M5 ;
        RECT  69.936 71.196 69.96 71.28 ;
    END
  END y[13]
  PIN y[14]
    DIRECTION OUTPUT ;
    USE SIGNAL ;
    PORT
      LAYER M5 ;
        RECT  70.032 71.196 70.056 71.28 ;
    END
  END y[14]
  PIN y[15]
    DIRECTION OUTPUT ;
    USE SIGNAL ;
    PORT
      LAYER M5 ;
        RECT  70.128 71.196 70.152 71.28 ;
    END
  END y[15]
  PIN y[16]
    DIRECTION OUTPUT ;
    USE SIGNAL ;
    PORT
      LAYER M5 ;
        RECT  70.224 71.196 70.248 71.28 ;
    END
  END y[16]
  PIN y[17]
    DIRECTION OUTPUT ;
    USE SIGNAL ;
    PORT
      LAYER M5 ;
        RECT  70.32 71.196 70.344 71.28 ;
    END
  END y[17]
  PIN y[18]
    DIRECTION OUTPUT ;
    USE SIGNAL ;
    PORT
      LAYER M5 ;
        RECT  70.416 71.196 70.44 71.28 ;
    END
  END y[18]
  PIN y[19]
    DIRECTION OUTPUT ;
    USE SIGNAL ;
    PORT
      LAYER M5 ;
        RECT  70.512 71.196 70.536 71.28 ;
    END
  END y[19]
  PIN y[1]
    DIRECTION OUTPUT ;
    USE SIGNAL ;
    PORT
      LAYER M5 ;
        RECT  68.784 71.196 68.808 71.28 ;
    END
  END y[1]
  PIN y[20]
    DIRECTION OUTPUT ;
    USE SIGNAL ;
    PORT
      LAYER M5 ;
        RECT  64.464 71.196 64.488 71.28 ;
    END
  END y[20]
  PIN y[21]
    DIRECTION OUTPUT ;
    USE SIGNAL ;
    PORT
      LAYER M5 ;
        RECT  64.56 71.196 64.584 71.28 ;
    END
  END y[21]
  PIN y[22]
    DIRECTION OUTPUT ;
    USE SIGNAL ;
    PORT
      LAYER M5 ;
        RECT  64.656 71.196 64.68 71.28 ;
    END
  END y[22]
  PIN y[23]
    DIRECTION OUTPUT ;
    USE SIGNAL ;
    PORT
      LAYER M5 ;
        RECT  64.752 71.196 64.776 71.28 ;
    END
  END y[23]
  PIN y[24]
    DIRECTION OUTPUT ;
    USE SIGNAL ;
    PORT
      LAYER M5 ;
        RECT  64.848 71.196 64.872 71.28 ;
    END
  END y[24]
  PIN y[25]
    DIRECTION OUTPUT ;
    USE SIGNAL ;
    PORT
      LAYER M5 ;
        RECT  64.944 71.196 64.968 71.28 ;
    END
  END y[25]
  PIN y[26]
    DIRECTION OUTPUT ;
    USE SIGNAL ;
    PORT
      LAYER M5 ;
        RECT  65.04 71.196 65.064 71.28 ;
    END
  END y[26]
  PIN y[27]
    DIRECTION OUTPUT ;
    USE SIGNAL ;
    PORT
      LAYER M5 ;
        RECT  65.136 71.196 65.16 71.28 ;
    END
  END y[27]
  PIN y[28]
    DIRECTION OUTPUT ;
    USE SIGNAL ;
    PORT
      LAYER M5 ;
        RECT  65.232 71.196 65.256 71.28 ;
    END
  END y[28]
  PIN y[29]
    DIRECTION OUTPUT ;
    USE SIGNAL ;
    PORT
      LAYER M5 ;
        RECT  65.328 71.196 65.352 71.28 ;
    END
  END y[29]
  PIN y[2]
    DIRECTION OUTPUT ;
    USE SIGNAL ;
    PORT
      LAYER M5 ;
        RECT  68.88 71.196 68.904 71.28 ;
    END
  END y[2]
  PIN y[30]
    DIRECTION OUTPUT ;
    USE SIGNAL ;
    PORT
      LAYER M5 ;
        RECT  65.424 71.196 65.448 71.28 ;
    END
  END y[30]
  PIN y[31]
    DIRECTION OUTPUT ;
    USE SIGNAL ;
    PORT
      LAYER M5 ;
        RECT  65.52 71.196 65.544 71.28 ;
    END
  END y[31]
  PIN y[32]
    DIRECTION OUTPUT ;
    USE SIGNAL ;
    PORT
      LAYER M5 ;
        RECT  65.616 71.196 65.64 71.28 ;
    END
  END y[32]
  PIN y[33]
    DIRECTION OUTPUT ;
    USE SIGNAL ;
    PORT
      LAYER M5 ;
        RECT  65.712 71.196 65.736 71.28 ;
    END
  END y[33]
  PIN y[34]
    DIRECTION OUTPUT ;
    USE SIGNAL ;
    PORT
      LAYER M5 ;
        RECT  65.808 71.196 65.832 71.28 ;
    END
  END y[34]
  PIN y[35]
    DIRECTION OUTPUT ;
    USE SIGNAL ;
    PORT
      LAYER M5 ;
        RECT  65.904 71.196 65.928 71.28 ;
    END
  END y[35]
  PIN y[36]
    DIRECTION OUTPUT ;
    USE SIGNAL ;
    PORT
      LAYER M5 ;
        RECT  66 71.196 66.024 71.28 ;
    END
  END y[36]
  PIN y[37]
    DIRECTION OUTPUT ;
    USE SIGNAL ;
    PORT
      LAYER M5 ;
        RECT  66.096 71.196 66.12 71.28 ;
    END
  END y[37]
  PIN y[38]
    DIRECTION OUTPUT ;
    USE SIGNAL ;
    PORT
      LAYER M5 ;
        RECT  66.192 71.196 66.216 71.28 ;
    END
  END y[38]
  PIN y[39]
    DIRECTION OUTPUT ;
    USE SIGNAL ;
    PORT
      LAYER M5 ;
        RECT  66.288 71.196 66.312 71.28 ;
    END
  END y[39]
  PIN y[3]
    DIRECTION OUTPUT ;
    USE SIGNAL ;
    PORT
      LAYER M5 ;
        RECT  68.976 71.196 69 71.28 ;
    END
  END y[3]
  PIN y[40]
    DIRECTION OUTPUT ;
    USE SIGNAL ;
    PORT
      LAYER M5 ;
        RECT  66.384 71.196 66.408 71.28 ;
    END
  END y[40]
  PIN y[41]
    DIRECTION OUTPUT ;
    USE SIGNAL ;
    PORT
      LAYER M5 ;
        RECT  66.48 71.196 66.504 71.28 ;
    END
  END y[41]
  PIN y[42]
    DIRECTION OUTPUT ;
    USE SIGNAL ;
    PORT
      LAYER M5 ;
        RECT  66.576 71.196 66.6 71.28 ;
    END
  END y[42]
  PIN y[43]
    DIRECTION OUTPUT ;
    USE SIGNAL ;
    PORT
      LAYER M5 ;
        RECT  66.672 71.196 66.696 71.28 ;
    END
  END y[43]
  PIN y[44]
    DIRECTION OUTPUT ;
    USE SIGNAL ;
    PORT
      LAYER M5 ;
        RECT  66.768 71.196 66.792 71.28 ;
    END
  END y[44]
  PIN y[45]
    DIRECTION OUTPUT ;
    USE SIGNAL ;
    PORT
      LAYER M5 ;
        RECT  66.864 71.196 66.888 71.28 ;
    END
  END y[45]
  PIN y[46]
    DIRECTION OUTPUT ;
    USE SIGNAL ;
    PORT
      LAYER M5 ;
        RECT  66.96 71.196 66.984 71.28 ;
    END
  END y[46]
  PIN y[47]
    DIRECTION OUTPUT ;
    USE SIGNAL ;
    PORT
      LAYER M5 ;
        RECT  67.056 71.196 67.08 71.28 ;
    END
  END y[47]
  PIN y[48]
    DIRECTION OUTPUT ;
    USE SIGNAL ;
    PORT
      LAYER M5 ;
        RECT  67.152 71.196 67.176 71.28 ;
    END
  END y[48]
  PIN y[49]
    DIRECTION OUTPUT ;
    USE SIGNAL ;
    PORT
      LAYER M5 ;
        RECT  67.248 71.196 67.272 71.28 ;
    END
  END y[49]
  PIN y[4]
    DIRECTION OUTPUT ;
    USE SIGNAL ;
    PORT
      LAYER M5 ;
        RECT  69.072 71.196 69.096 71.28 ;
    END
  END y[4]
  PIN y[50]
    DIRECTION OUTPUT ;
    USE SIGNAL ;
    PORT
      LAYER M5 ;
        RECT  67.344 71.196 67.368 71.28 ;
    END
  END y[50]
  PIN y[51]
    DIRECTION OUTPUT ;
    USE SIGNAL ;
    PORT
      LAYER M5 ;
        RECT  67.44 71.196 67.464 71.28 ;
    END
  END y[51]
  PIN y[52]
    DIRECTION OUTPUT ;
    USE SIGNAL ;
    PORT
      LAYER M5 ;
        RECT  61.392 71.196 61.416 71.28 ;
    END
  END y[52]
  PIN y[53]
    DIRECTION OUTPUT ;
    USE SIGNAL ;
    PORT
      LAYER M5 ;
        RECT  61.488 71.196 61.512 71.28 ;
    END
  END y[53]
  PIN y[54]
    DIRECTION OUTPUT ;
    USE SIGNAL ;
    PORT
      LAYER M5 ;
        RECT  61.584 71.196 61.608 71.28 ;
    END
  END y[54]
  PIN y[55]
    DIRECTION OUTPUT ;
    USE SIGNAL ;
    PORT
      LAYER M5 ;
        RECT  61.68 71.196 61.704 71.28 ;
    END
  END y[55]
  PIN y[56]
    DIRECTION OUTPUT ;
    USE SIGNAL ;
    PORT
      LAYER M5 ;
        RECT  61.776 71.196 61.8 71.28 ;
    END
  END y[56]
  PIN y[57]
    DIRECTION OUTPUT ;
    USE SIGNAL ;
    PORT
      LAYER M5 ;
        RECT  61.872 71.196 61.896 71.28 ;
    END
  END y[57]
  PIN y[58]
    DIRECTION OUTPUT ;
    USE SIGNAL ;
    PORT
      LAYER M5 ;
        RECT  61.968 71.196 61.992 71.28 ;
    END
  END y[58]
  PIN y[59]
    DIRECTION OUTPUT ;
    USE SIGNAL ;
    PORT
      LAYER M5 ;
        RECT  62.064 71.196 62.088 71.28 ;
    END
  END y[59]
  PIN y[5]
    DIRECTION OUTPUT ;
    USE SIGNAL ;
    PORT
      LAYER M5 ;
        RECT  69.168 71.196 69.192 71.28 ;
    END
  END y[5]
  PIN y[60]
    DIRECTION OUTPUT ;
    USE SIGNAL ;
    PORT
      LAYER M5 ;
        RECT  62.16 71.196 62.184 71.28 ;
    END
  END y[60]
  PIN y[61]
    DIRECTION OUTPUT ;
    USE SIGNAL ;
    PORT
      LAYER M5 ;
        RECT  62.256 71.196 62.28 71.28 ;
    END
  END y[61]
  PIN y[62]
    DIRECTION OUTPUT ;
    USE SIGNAL ;
    PORT
      LAYER M5 ;
        RECT  62.352 71.196 62.376 71.28 ;
    END
  END y[62]
  PIN y[63]
    DIRECTION OUTPUT ;
    USE SIGNAL ;
    PORT
      LAYER M5 ;
        RECT  62.448 71.196 62.472 71.28 ;
    END
  END y[63]
  PIN y[64]
    DIRECTION OUTPUT ;
    USE SIGNAL ;
    PORT
      LAYER M5 ;
        RECT  62.544 71.196 62.568 71.28 ;
    END
  END y[64]
  PIN y[65]
    DIRECTION OUTPUT ;
    USE SIGNAL ;
    PORT
      LAYER M5 ;
        RECT  62.64 71.196 62.664 71.28 ;
    END
  END y[65]
  PIN y[66]
    DIRECTION OUTPUT ;
    USE SIGNAL ;
    PORT
      LAYER M5 ;
        RECT  62.736 71.196 62.76 71.28 ;
    END
  END y[66]
  PIN y[67]
    DIRECTION OUTPUT ;
    USE SIGNAL ;
    PORT
      LAYER M5 ;
        RECT  62.832 71.196 62.856 71.28 ;
    END
  END y[67]
  PIN y[68]
    DIRECTION OUTPUT ;
    USE SIGNAL ;
    PORT
      LAYER M5 ;
        RECT  62.928 71.196 62.952 71.28 ;
    END
  END y[68]
  PIN y[69]
    DIRECTION OUTPUT ;
    USE SIGNAL ;
    PORT
      LAYER M5 ;
        RECT  63.024 71.196 63.048 71.28 ;
    END
  END y[69]
  PIN y[6]
    DIRECTION OUTPUT ;
    USE SIGNAL ;
    PORT
      LAYER M5 ;
        RECT  69.264 71.196 69.288 71.28 ;
    END
  END y[6]
  PIN y[70]
    DIRECTION OUTPUT ;
    USE SIGNAL ;
    PORT
      LAYER M5 ;
        RECT  63.12 71.196 63.144 71.28 ;
    END
  END y[70]
  PIN y[71]
    DIRECTION OUTPUT ;
    USE SIGNAL ;
    PORT
      LAYER M5 ;
        RECT  63.216 71.196 63.24 71.28 ;
    END
  END y[71]
  PIN y[72]
    DIRECTION OUTPUT ;
    USE SIGNAL ;
    PORT
      LAYER M5 ;
        RECT  63.312 71.196 63.336 71.28 ;
    END
  END y[72]
  PIN y[73]
    DIRECTION OUTPUT ;
    USE SIGNAL ;
    PORT
      LAYER M5 ;
        RECT  63.408 71.196 63.432 71.28 ;
    END
  END y[73]
  PIN y[74]
    DIRECTION OUTPUT ;
    USE SIGNAL ;
    PORT
      LAYER M5 ;
        RECT  63.504 71.196 63.528 71.28 ;
    END
  END y[74]
  PIN y[75]
    DIRECTION OUTPUT ;
    USE SIGNAL ;
    PORT
      LAYER M5 ;
        RECT  63.6 71.196 63.624 71.28 ;
    END
  END y[75]
  PIN y[76]
    DIRECTION OUTPUT ;
    USE SIGNAL ;
    PORT
      LAYER M5 ;
        RECT  63.696 71.196 63.72 71.28 ;
    END
  END y[76]
  PIN y[77]
    DIRECTION OUTPUT ;
    USE SIGNAL ;
    PORT
      LAYER M5 ;
        RECT  63.792 71.196 63.816 71.28 ;
    END
  END y[77]
  PIN y[78]
    DIRECTION OUTPUT ;
    USE SIGNAL ;
    PORT
      LAYER M5 ;
        RECT  63.888 71.196 63.912 71.28 ;
    END
  END y[78]
  PIN y[79]
    DIRECTION OUTPUT ;
    USE SIGNAL ;
    PORT
      LAYER M5 ;
        RECT  63.984 71.196 64.008 71.28 ;
    END
  END y[79]
  PIN y[7]
    DIRECTION OUTPUT ;
    USE SIGNAL ;
    PORT
      LAYER M5 ;
        RECT  69.36 71.196 69.384 71.28 ;
    END
  END y[7]
  PIN y[80]
    DIRECTION OUTPUT ;
    USE SIGNAL ;
    PORT
      LAYER M5 ;
        RECT  64.08 71.196 64.104 71.28 ;
    END
  END y[80]
  PIN y[81]
    DIRECTION OUTPUT ;
    USE SIGNAL ;
    PORT
      LAYER M5 ;
        RECT  64.176 71.196 64.2 71.28 ;
    END
  END y[81]
  PIN y[82]
    DIRECTION OUTPUT ;
    USE SIGNAL ;
    PORT
      LAYER M5 ;
        RECT  64.272 71.196 64.296 71.28 ;
    END
  END y[82]
  PIN y[83]
    DIRECTION OUTPUT ;
    USE SIGNAL ;
    PORT
      LAYER M5 ;
        RECT  64.368 71.196 64.392 71.28 ;
    END
  END y[83]
  PIN y[84]
    DIRECTION OUTPUT ;
    USE SIGNAL ;
    PORT
      LAYER M5 ;
        RECT  58.32 71.196 58.344 71.28 ;
    END
  END y[84]
  PIN y[85]
    DIRECTION OUTPUT ;
    USE SIGNAL ;
    PORT
      LAYER M5 ;
        RECT  58.416 71.196 58.44 71.28 ;
    END
  END y[85]
  PIN y[86]
    DIRECTION OUTPUT ;
    USE SIGNAL ;
    PORT
      LAYER M5 ;
        RECT  58.512 71.196 58.536 71.28 ;
    END
  END y[86]
  PIN y[87]
    DIRECTION OUTPUT ;
    USE SIGNAL ;
    PORT
      LAYER M5 ;
        RECT  58.608 71.196 58.632 71.28 ;
    END
  END y[87]
  PIN y[88]
    DIRECTION OUTPUT ;
    USE SIGNAL ;
    PORT
      LAYER M5 ;
        RECT  58.704 71.196 58.728 71.28 ;
    END
  END y[88]
  PIN y[89]
    DIRECTION OUTPUT ;
    USE SIGNAL ;
    PORT
      LAYER M5 ;
        RECT  58.8 71.196 58.824 71.28 ;
    END
  END y[89]
  PIN y[8]
    DIRECTION OUTPUT ;
    USE SIGNAL ;
    PORT
      LAYER M5 ;
        RECT  69.456 71.196 69.48 71.28 ;
    END
  END y[8]
  PIN y[90]
    DIRECTION OUTPUT ;
    USE SIGNAL ;
    PORT
      LAYER M5 ;
        RECT  58.896 71.196 58.92 71.28 ;
    END
  END y[90]
  PIN y[91]
    DIRECTION OUTPUT ;
    USE SIGNAL ;
    PORT
      LAYER M5 ;
        RECT  58.992 71.196 59.016 71.28 ;
    END
  END y[91]
  PIN y[92]
    DIRECTION OUTPUT ;
    USE SIGNAL ;
    PORT
      LAYER M5 ;
        RECT  59.088 71.196 59.112 71.28 ;
    END
  END y[92]
  PIN y[93]
    DIRECTION OUTPUT ;
    USE SIGNAL ;
    PORT
      LAYER M5 ;
        RECT  59.184 71.196 59.208 71.28 ;
    END
  END y[93]
  PIN y[94]
    DIRECTION OUTPUT ;
    USE SIGNAL ;
    PORT
      LAYER M5 ;
        RECT  59.28 71.196 59.304 71.28 ;
    END
  END y[94]
  PIN y[95]
    DIRECTION OUTPUT ;
    USE SIGNAL ;
    PORT
      LAYER M5 ;
        RECT  59.376 71.196 59.4 71.28 ;
    END
  END y[95]
  PIN y[96]
    DIRECTION OUTPUT ;
    USE SIGNAL ;
    PORT
      LAYER M5 ;
        RECT  59.472 71.196 59.496 71.28 ;
    END
  END y[96]
  PIN y[97]
    DIRECTION OUTPUT ;
    USE SIGNAL ;
    PORT
      LAYER M5 ;
        RECT  59.568 71.196 59.592 71.28 ;
    END
  END y[97]
  PIN y[98]
    DIRECTION OUTPUT ;
    USE SIGNAL ;
    PORT
      LAYER M5 ;
        RECT  59.664 71.196 59.688 71.28 ;
    END
  END y[98]
  PIN y[99]
    DIRECTION OUTPUT ;
    USE SIGNAL ;
    PORT
      LAYER M5 ;
        RECT  59.76 71.196 59.784 71.28 ;
    END
  END y[99]
  PIN y[9]
    DIRECTION OUTPUT ;
    USE SIGNAL ;
    PORT
      LAYER M5 ;
        RECT  69.552 71.196 69.576 71.28 ;
    END
  END y[9]
  PIN VDD
    DIRECTION INOUT ;
    USE POWER ;
    PORT
      LAYER M5 ;
        RECT  67.392 2.151 67.512 69.129 ;
        RECT  61.992 2.151 62.112 69.129 ;
        RECT  56.592 2.151 56.712 69.129 ;
        RECT  51.192 2.151 51.312 69.129 ;
        RECT  45.792 2.151 45.912 69.129 ;
        RECT  40.392 2.151 40.512 69.129 ;
        RECT  34.992 2.151 35.112 69.129 ;
        RECT  29.592 2.151 29.712 69.129 ;
        RECT  24.192 2.151 24.312 69.129 ;
        RECT  18.792 2.151 18.912 69.129 ;
        RECT  13.392 2.151 13.512 69.129 ;
        RECT  7.992 2.151 8.112 69.129 ;
        RECT  2.592 2.151 2.712 69.129 ;
    END
  END VDD
  PIN VSS
    DIRECTION INOUT ;
    USE GROUND ;
    PORT
      LAYER M5 ;
        RECT  67.2 2.137 67.32 69.143 ;
        RECT  61.8 2.137 61.92 69.143 ;
        RECT  56.4 2.137 56.52 69.143 ;
        RECT  51 2.137 51.12 69.143 ;
        RECT  45.6 2.137 45.72 69.143 ;
        RECT  40.2 2.137 40.32 69.143 ;
        RECT  34.8 2.137 34.92 69.143 ;
        RECT  29.4 2.137 29.52 69.143 ;
        RECT  24 2.137 24.12 69.143 ;
        RECT  18.6 2.137 18.72 69.143 ;
        RECT  13.2 2.137 13.32 69.143 ;
        RECT  7.8 2.137 7.92 69.143 ;
        RECT  2.4 2.137 2.52 69.143 ;
    END
  END VSS
  # OT_OBS_CLOSED layer=M5 d_um=1.536 added=217
  OBS
    LAYER RVTN ;
     RECT  2.16 2.16 69.12 2.295 ;
     RECT  2.16 2.565 69.12 2.835 ;
     RECT  2.16 3.105 69.12 3.375 ;
     RECT  2.16 3.645 69.12 3.915 ;
     RECT  2.16 4.185 69.12 4.455 ;
     RECT  2.16 4.725 69.12 4.995 ;
     RECT  2.16 5.265 69.12 5.535 ;
     RECT  2.16 5.805 69.12 6.075 ;
     RECT  2.16 6.345 69.12 6.615 ;
     RECT  2.16 6.885 69.12 7.155 ;
     RECT  2.16 7.425 69.12 7.695 ;
     RECT  2.16 7.965 69.12 8.235 ;
     RECT  2.16 8.505 69.12 8.775 ;
     RECT  2.16 9.045 69.12 9.315 ;
     RECT  2.16 9.585 69.12 9.855 ;
     RECT  2.16 10.125 69.12 10.395 ;
     RECT  2.16 10.665 69.12 10.935 ;
     RECT  2.16 11.205 69.12 11.475 ;
     RECT  2.16 11.745 69.12 12.015 ;
     RECT  2.16 12.285 69.12 12.555 ;
     RECT  2.16 12.825 69.12 13.095 ;
     RECT  2.16 13.365 69.12 13.635 ;
     RECT  2.16 13.905 69.12 14.175 ;
     RECT  2.16 14.445 69.12 14.715 ;
     RECT  2.16 14.985 69.12 15.255 ;
     RECT  2.16 15.525 69.12 15.795 ;
     RECT  2.16 16.065 69.12 16.335 ;
     RECT  2.16 16.605 69.12 16.875 ;
     RECT  2.16 17.145 69.12 17.415 ;
     RECT  2.16 17.685 69.12 17.955 ;
     RECT  2.16 18.225 69.12 18.495 ;
     RECT  2.16 18.765 69.12 19.035 ;
     RECT  2.16 19.305 69.12 19.575 ;
     RECT  2.16 19.845 69.12 20.115 ;
     RECT  2.16 20.385 69.12 20.655 ;
     RECT  2.16 20.925 69.12 21.195 ;
     RECT  2.16 21.465 69.12 21.735 ;
     RECT  2.16 22.005 69.12 22.275 ;
     RECT  2.16 22.545 69.12 22.815 ;
     RECT  2.16 23.085 69.12 23.355 ;
     RECT  2.16 23.625 69.12 23.895 ;
     RECT  2.16 24.165 69.12 24.435 ;
     RECT  2.16 24.705 69.12 24.975 ;
     RECT  2.16 25.245 69.12 25.515 ;
     RECT  2.16 25.785 69.12 26.055 ;
     RECT  2.16 26.325 69.12 26.595 ;
     RECT  2.16 26.865 69.12 27.135 ;
     RECT  2.16 27.405 69.12 27.675 ;
     RECT  2.16 27.945 69.12 28.215 ;
     RECT  2.16 28.485 69.12 28.755 ;
     RECT  2.16 29.025 69.12 29.295 ;
     RECT  2.16 29.565 69.12 29.835 ;
     RECT  2.16 30.105 69.12 30.375 ;
     RECT  2.16 30.645 69.12 30.915 ;
     RECT  2.16 31.185 69.12 31.455 ;
     RECT  2.16 31.725 69.12 31.995 ;
     RECT  2.16 32.265 69.12 32.535 ;
     RECT  2.16 32.805 69.12 33.075 ;
     RECT  2.16 33.345 69.12 33.615 ;
     RECT  2.16 33.885 69.12 34.155 ;
     RECT  2.16 34.425 69.12 34.695 ;
     RECT  2.16 34.965 69.12 35.235 ;
     RECT  2.16 35.505 69.12 35.775 ;
     RECT  2.16 36.045 69.12 36.315 ;
     RECT  2.16 36.585 69.12 36.855 ;
     RECT  2.16 37.125 69.12 37.395 ;
     RECT  2.16 37.665 69.12 37.935 ;
     RECT  2.16 38.205 69.12 38.475 ;
     RECT  2.16 38.745 69.12 39.015 ;
     RECT  2.16 39.285 69.12 39.555 ;
     RECT  2.16 39.825 69.12 40.095 ;
     RECT  2.16 40.365 69.12 40.635 ;
     RECT  2.16 40.905 69.12 41.175 ;
     RECT  2.16 41.445 69.12 41.715 ;
     RECT  2.16 41.985 69.12 42.255 ;
     RECT  2.16 42.525 69.12 42.795 ;
     RECT  2.16 43.065 69.12 43.335 ;
     RECT  2.16 43.605 69.12 43.875 ;
     RECT  2.16 44.145 69.12 44.415 ;
     RECT  2.16 44.685 69.12 44.955 ;
     RECT  2.16 45.225 69.12 45.495 ;
     RECT  2.16 45.765 69.12 46.035 ;
     RECT  2.16 46.305 69.12 46.575 ;
     RECT  2.16 46.845 69.12 47.115 ;
     RECT  2.16 47.385 69.12 47.655 ;
     RECT  2.16 47.925 69.12 48.195 ;
     RECT  2.16 48.465 69.12 48.735 ;
     RECT  2.16 49.005 69.12 49.275 ;
     RECT  2.16 49.545 69.12 49.815 ;
     RECT  2.16 50.085 69.12 50.355 ;
     RECT  2.16 50.625 69.12 50.895 ;
     RECT  2.16 51.165 69.12 51.435 ;
     RECT  2.16 51.705 69.12 51.975 ;
     RECT  2.16 52.245 69.12 52.515 ;
     RECT  2.16 52.785 69.12 53.055 ;
     RECT  2.16 53.325 69.12 53.595 ;
     RECT  2.16 53.865 69.12 54.135 ;
     RECT  2.16 54.405 69.12 54.675 ;
     RECT  2.16 54.945 69.12 55.215 ;
     RECT  2.16 55.485 69.12 55.755 ;
     RECT  2.16 56.025 69.12 56.295 ;
     RECT  2.16 56.565 69.12 56.835 ;
     RECT  2.16 57.105 69.12 57.375 ;
     RECT  2.16 57.645 69.12 57.915 ;
     RECT  2.16 58.185 69.12 58.455 ;
     RECT  2.16 58.725 69.12 58.995 ;
     RECT  2.16 59.265 69.12 59.535 ;
     RECT  2.16 59.805 69.12 60.075 ;
     RECT  2.16 60.345 69.12 60.615 ;
     RECT  2.16 60.885 69.12 61.155 ;
     RECT  2.16 61.425 69.12 61.695 ;
     RECT  2.16 61.965 69.12 62.235 ;
     RECT  2.16 62.505 69.12 62.775 ;
     RECT  2.16 63.045 69.12 63.315 ;
     RECT  2.16 63.585 69.12 63.855 ;
     RECT  2.16 64.125 69.12 64.395 ;
     RECT  2.16 64.665 69.12 64.935 ;
     RECT  2.16 65.205 69.12 65.475 ;
     RECT  2.16 65.745 69.12 66.015 ;
     RECT  2.16 66.285 69.12 66.555 ;
     RECT  2.16 66.825 69.12 67.095 ;
     RECT  2.16 67.365 69.12 67.635 ;
     RECT  2.16 67.905 69.12 68.175 ;
     RECT  2.16 68.445 69.12 68.715 ;
     RECT  2.16 68.985 69.12 69.12 ;
    LAYER RVTP ;
     RECT  2.16 2.295 69.12 2.565 ;
     RECT  2.16 2.835 69.12 3.105 ;
     RECT  2.16 3.375 69.12 3.645 ;
     RECT  2.16 3.915 69.12 4.185 ;
     RECT  2.16 4.455 69.12 4.725 ;
     RECT  2.16 4.995 69.12 5.265 ;
     RECT  2.16 5.535 69.12 5.805 ;
     RECT  2.16 6.075 69.12 6.345 ;
     RECT  2.16 6.615 69.12 6.885 ;
     RECT  2.16 7.155 69.12 7.425 ;
     RECT  2.16 7.695 69.12 7.965 ;
     RECT  2.16 8.235 69.12 8.505 ;
     RECT  2.16 8.775 69.12 9.045 ;
     RECT  2.16 9.315 69.12 9.585 ;
     RECT  2.16 9.855 69.12 10.125 ;
     RECT  2.16 10.395 69.12 10.665 ;
     RECT  2.16 10.935 69.12 11.205 ;
     RECT  2.16 11.475 69.12 11.745 ;
     RECT  2.16 12.015 69.12 12.285 ;
     RECT  2.16 12.555 69.12 12.825 ;
     RECT  2.16 13.095 69.12 13.365 ;
     RECT  2.16 13.635 69.12 13.905 ;
     RECT  2.16 14.175 69.12 14.445 ;
     RECT  2.16 14.715 69.12 14.985 ;
     RECT  2.16 15.255 69.12 15.525 ;
     RECT  2.16 15.795 69.12 16.065 ;
     RECT  2.16 16.335 69.12 16.605 ;
     RECT  2.16 16.875 69.12 17.145 ;
     RECT  2.16 17.415 69.12 17.685 ;
     RECT  2.16 17.955 69.12 18.225 ;
     RECT  2.16 18.495 69.12 18.765 ;
     RECT  2.16 19.035 69.12 19.305 ;
     RECT  2.16 19.575 69.12 19.845 ;
     RECT  2.16 20.115 69.12 20.385 ;
     RECT  2.16 20.655 69.12 20.925 ;
     RECT  2.16 21.195 69.12 21.465 ;
     RECT  2.16 21.735 69.12 22.005 ;
     RECT  2.16 22.275 69.12 22.545 ;
     RECT  2.16 22.815 69.12 23.085 ;
     RECT  2.16 23.355 69.12 23.625 ;
     RECT  2.16 23.895 69.12 24.165 ;
     RECT  2.16 24.435 69.12 24.705 ;
     RECT  2.16 24.975 69.12 25.245 ;
     RECT  2.16 25.515 69.12 25.785 ;
     RECT  2.16 26.055 69.12 26.325 ;
     RECT  2.16 26.595 69.12 26.865 ;
     RECT  2.16 27.135 69.12 27.405 ;
     RECT  2.16 27.675 69.12 27.945 ;
     RECT  2.16 28.215 69.12 28.485 ;
     RECT  2.16 28.755 69.12 29.025 ;
     RECT  2.16 29.295 69.12 29.565 ;
     RECT  2.16 29.835 69.12 30.105 ;
     RECT  2.16 30.375 69.12 30.645 ;
     RECT  2.16 30.915 69.12 31.185 ;
     RECT  2.16 31.455 69.12 31.725 ;
     RECT  2.16 31.995 69.12 32.265 ;
     RECT  2.16 32.535 69.12 32.805 ;
     RECT  2.16 33.075 69.12 33.345 ;
     RECT  2.16 33.615 69.12 33.885 ;
     RECT  2.16 34.155 69.12 34.425 ;
     RECT  2.16 34.695 69.12 34.965 ;
     RECT  2.16 35.235 69.12 35.505 ;
     RECT  2.16 35.775 69.12 36.045 ;
     RECT  2.16 36.315 69.12 36.585 ;
     RECT  2.16 36.855 69.12 37.125 ;
     RECT  2.16 37.395 69.12 37.665 ;
     RECT  2.16 37.935 69.12 38.205 ;
     RECT  2.16 38.475 69.12 38.745 ;
     RECT  2.16 39.015 69.12 39.285 ;
     RECT  2.16 39.555 69.12 39.825 ;
     RECT  2.16 40.095 69.12 40.365 ;
     RECT  2.16 40.635 69.12 40.905 ;
     RECT  2.16 41.175 69.12 41.445 ;
     RECT  2.16 41.715 69.12 41.985 ;
     RECT  2.16 42.255 69.12 42.525 ;
     RECT  2.16 42.795 69.12 43.065 ;
     RECT  2.16 43.335 69.12 43.605 ;
     RECT  2.16 43.875 69.12 44.145 ;
     RECT  2.16 44.415 69.12 44.685 ;
     RECT  2.16 44.955 69.12 45.225 ;
     RECT  2.16 45.495 69.12 45.765 ;
     RECT  2.16 46.035 69.12 46.305 ;
     RECT  2.16 46.575 69.12 46.845 ;
     RECT  2.16 47.115 69.12 47.385 ;
     RECT  2.16 47.655 69.12 47.925 ;
     RECT  2.16 48.195 69.12 48.465 ;
     RECT  2.16 48.735 69.12 49.005 ;
     RECT  2.16 49.275 69.12 49.545 ;
     RECT  2.16 49.815 69.12 50.085 ;
     RECT  2.16 50.355 69.12 50.625 ;
     RECT  2.16 50.895 69.12 51.165 ;
     RECT  2.16 51.435 69.12 51.705 ;
     RECT  2.16 51.975 69.12 52.245 ;
     RECT  2.16 52.515 69.12 52.785 ;
     RECT  2.16 53.055 69.12 53.325 ;
     RECT  2.16 53.595 69.12 53.865 ;
     RECT  2.16 54.135 69.12 54.405 ;
     RECT  2.16 54.675 69.12 54.945 ;
     RECT  2.16 55.215 69.12 55.485 ;
     RECT  2.16 55.755 69.12 56.025 ;
     RECT  2.16 56.295 69.12 56.565 ;
     RECT  2.16 56.835 69.12 57.105 ;
     RECT  2.16 57.375 69.12 57.645 ;
     RECT  2.16 57.915 69.12 58.185 ;
     RECT  2.16 58.455 69.12 58.725 ;
     RECT  2.16 58.995 69.12 59.265 ;
     RECT  2.16 59.535 69.12 59.805 ;
     RECT  2.16 60.075 69.12 60.345 ;
     RECT  2.16 60.615 69.12 60.885 ;
     RECT  2.16 61.155 69.12 61.425 ;
     RECT  2.16 61.695 69.12 61.965 ;
     RECT  2.16 62.235 69.12 62.505 ;
     RECT  2.16 62.775 69.12 63.045 ;
     RECT  2.16 63.315 69.12 63.585 ;
     RECT  2.16 63.855 69.12 64.125 ;
     RECT  2.16 64.395 69.12 64.665 ;
     RECT  2.16 64.935 69.12 65.205 ;
     RECT  2.16 65.475 69.12 65.745 ;
     RECT  2.16 66.015 69.12 66.285 ;
     RECT  2.16 66.555 69.12 66.825 ;
     RECT  2.16 67.095 69.12 67.365 ;
     RECT  2.16 67.635 69.12 67.905 ;
     RECT  2.16 68.175 69.12 68.445 ;
     RECT  2.16 68.715 69.12 68.985 ;
    LAYER M1 ;
     RECT  2.16 2.151 69.12 69.129 ;
    LAYER M2 ;
     RECT  1.903 3.114 1.975 3.132 ;
     RECT  1.939 18.576 1.975 18.594 ;
     RECT  1.939 4.536 2.047 4.554 ;
     RECT  1.975 3.114 2.083 3.474 ;
     RECT  2.011 21.906 2.083 21.924 ;
     RECT  2.047 4.536 2.155 4.824 ;
     RECT  2.083 2.772 2.16 3.474 ;
     RECT  2.155 4.536 2.16 5.094 ;
     RECT  2.083 9.126 2.16 9.144 ;
     RECT  2.119 11.016 2.16 11.034 ;
     RECT  2.011 12.366 2.16 12.384 ;
     RECT  2.047 16.956 2.16 16.974 ;
     RECT  2.155 17.766 2.16 17.784 ;
     RECT  1.975 18.576 2.16 18.954 ;
     RECT  2.083 21.276 2.16 21.924 ;
     RECT  2.119 24.246 2.16 24.264 ;
     RECT  2.16 2.151 4.315 69.129 ;
     RECT  4.315 2.106 5.503 69.129 ;
     RECT  6.259 1.152 6.647 1.17 ;
     RECT  5.503 1.962 9.319 69.129 ;
     RECT  9.319 1.881 10.679 69.129 ;
     RECT  10.679 1.962 11.623 69.129 ;
     RECT  11.623 1.422 15.395 69.129 ;
     RECT  15.395 1.8 15.899 69.129 ;
     RECT  15.899 1.836 17.671 69.129 ;
     RECT  17.671 1.422 24.395 69.129 ;
     RECT  24.395 1.458 26.123 69.129 ;
     RECT  26.123 1.728 28.391 69.129 ;
     RECT  28.391 1.8 28.535 69.129 ;
     RECT  28.535 1.836 31.387 69.129 ;
     RECT  31.387 1.764 35.807 69.129 ;
     RECT  35.807 2.106 39.299 69.129 ;
     RECT  39.299 2.151 52.987 69.129 ;
     RECT  52.987 2.034 55.031 69.129 ;
     RECT  55.579 70.38 55.759 70.398 ;
     RECT  55.031 2.106 56.047 69.129 ;
     RECT  56.047 2.106 56.471 69.552 ;
     RECT  55.759 70.38 57.083 70.668 ;
     RECT  56.471 2.106 59.315 69.246 ;
     RECT  59.315 2.106 60.107 69.129 ;
     RECT  57.083 70.38 61.123 70.398 ;
     RECT  61.123 70.38 61.799 70.668 ;
     RECT  61.799 70.38 62.735 70.398 ;
     RECT  65.119 70.578 65.191 70.596 ;
     RECT  65.191 70.578 65.219 70.668 ;
     RECT  65.219 70.65 65.471 70.668 ;
     RECT  66.199 70.65 66.299 70.668 ;
     RECT  60.107 2.151 69.12 69.129 ;
     RECT  69.12 58.536 69.143 58.554 ;
     RECT  69.12 62.478 69.143 62.694 ;
     RECT  69.12 64.368 69.179 64.386 ;
     RECT  69.12 65.25 69.287 65.304 ;
     RECT  69.12 66.096 69.395 67.734 ;
     RECT  69.12 68.724 69.467 68.976 ;
     RECT  69.395 66.096 69.611 66.546 ;
     RECT  69.467 68.724 69.647 68.742 ;
     RECT  69.287 65.286 69.791 65.304 ;
     RECT  69.611 66.096 69.899 66.276 ;
     RECT  69.143 62.676 69.971 62.694 ;
     RECT  69.899 66.258 70.187 66.276 ;
     RECT  69.395 67.446 70.439 67.734 ;
     RECT  70.439 67.446 70.547 67.464 ;
    LAYER M3 ;
     RECT  16.488 0.043 16.506 0.091 ;
     RECT  6.624 0.091 6.642 0.139 ;
     RECT  7.452 0.091 7.47 0.139 ;
     RECT  8.568 0.091 9.234 0.139 ;
     RECT  15.516 0.091 16.506 0.139 ;
     RECT  15.372 0.139 16.506 0.173 ;
     RECT  19.368 0.139 19.386 0.187 ;
     RECT  27.108 0.139 27.126 0.187 ;
     RECT  25.236 0.139 25.254 0.235 ;
     RECT  7.452 0.139 9.234 0.475 ;
     RECT  6.264 0.139 6.642 0.523 ;
     RECT  7.452 0.475 9.918 0.523 ;
     RECT  11.268 0.091 11.286 0.523 ;
     RECT  6.264 0.523 9.918 0.571 ;
     RECT  11.124 0.523 11.286 0.571 ;
     RECT  23.364 0.043 23.382 0.571 ;
     RECT  6.264 0.571 11.286 0.859 ;
     RECT  12.564 0.619 12.582 0.859 ;
     RECT  26.496 0.187 27.126 0.859 ;
     RECT  23.364 0.571 23.454 0.955 ;
     RECT  25.236 0.235 25.722 1.147 ;
     RECT  24.66 1.147 25.722 1.387 ;
     RECT  26.46 0.859 27.126 1.387 ;
     RECT  23.364 0.955 23.814 1.417 ;
     RECT  24.66 1.387 27.126 1.417 ;
     RECT  20.772 0.235 20.79 1.579 ;
     RECT  20.52 1.579 20.79 1.627 ;
     RECT  2.304 0.091 2.898 1.723 ;
     RECT  6.264 0.859 12.582 1.723 ;
     RECT  13.716 0.571 13.734 1.723 ;
     RECT  15.372 0.173 15.894 1.723 ;
     RECT  17.676 0.091 17.694 1.723 ;
     RECT  19.368 0.187 19.566 1.723 ;
     RECT  28.008 0.091 28.026 1.723 ;
     RECT  17.676 1.723 17.838 1.759 ;
     RECT  19.044 1.723 19.566 1.759 ;
     RECT  22.248 0.091 22.266 1.759 ;
     RECT  23.364 1.417 27.126 1.759 ;
     RECT  28.008 1.723 28.386 1.759 ;
     RECT  1.908 1.723 13.734 1.771 ;
     RECT  15.048 1.723 15.894 1.771 ;
     RECT  23.364 1.759 28.386 1.795 ;
     RECT  16.668 1.771 16.686 1.819 ;
     RECT  17.676 1.759 19.566 1.819 ;
     RECT  21.924 1.759 22.266 1.831 ;
     RECT  23.364 1.795 28.53 1.831 ;
     RECT  31.392 1.759 31.41 1.831 ;
     RECT  21.924 1.831 28.53 1.876 ;
     RECT  31.392 1.831 32.13 1.876 ;
     RECT  35.784 1.759 35.802 1.876 ;
     RECT  1.908 1.771 15.894 1.915 ;
     RECT  16.668 1.819 19.566 1.915 ;
     RECT  31.392 1.876 32.562 1.957 ;
     RECT  20.52 1.627 21.114 1.963 ;
     RECT  31.392 1.957 33.03 1.993 ;
     RECT  21.888 1.876 28.53 2.029 ;
     RECT  29.556 1.876 29.574 2.029 ;
     RECT  1.908 1.915 19.566 2.065 ;
     RECT  20.376 1.963 21.114 2.065 ;
     RECT  21.888 2.029 28.71 2.101 ;
     RECT  29.556 2.029 29.682 2.101 ;
     RECT  31.392 1.993 33.75 2.101 ;
     RECT  55.008 2.029 55.026 2.101 ;
     RECT  35.136 1.876 35.802 2.143 ;
     RECT  1.908 2.065 21.114 2.155 ;
     RECT  21.888 2.101 29.682 2.155 ;
     RECT  58.392 2.101 58.734 2.191 ;
     RECT  30.996 2.101 33.75 2.203 ;
     RECT  34.815 2.143 35.802 2.203 ;
     RECT  52.992 2.029 53.01 2.219 ;
     RECT  1.908 2.155 29.682 2.227 ;
     RECT  30.996 2.203 35.802 2.227 ;
     RECT  39.276 2.101 39.294 2.227 ;
     RECT  37.584 2.191 37.602 2.251 ;
     RECT  60.084 2.101 60.102 2.251 ;
     RECT  58.392 2.191 58.806 2.263 ;
     RECT  61.815 2.143 61.905 2.263 ;
     RECT  30.996 2.227 36.126 2.299 ;
     RECT  37.044 2.251 37.602 2.299 ;
     RECT  39.132 2.227 39.294 2.299 ;
     RECT  45.615 2.143 45.705 2.299 ;
     RECT  52.776 2.263 52.902 2.299 ;
     RECT  54.288 2.101 55.026 2.299 ;
     RECT  60.012 2.251 60.102 2.335 ;
     RECT  40.215 2.143 40.305 2.347 ;
     RECT  1.908 2.227 30.114 2.371 ;
     RECT  30.888 2.299 37.602 2.371 ;
     RECT  38.412 2.299 39.294 2.371 ;
     RECT  40.215 2.347 40.554 2.371 ;
     RECT  41.796 2.191 41.814 2.371 ;
     RECT  45.468 2.299 45.705 2.371 ;
     RECT  53.82 2.299 55.026 2.371 ;
     RECT  57.384 2.263 58.806 2.371 ;
     RECT  61.632 2.263 61.905 2.371 ;
     RECT  45.18 2.371 45.705 2.413 ;
     RECT  51.015 2.143 51.105 2.413 ;
     RECT  56.415 2.143 56.505 2.413 ;
     RECT  57.348 2.371 58.806 2.413 ;
     RECT  67.215 2.143 67.305 2.413 ;
     RECT  38.34 2.371 39.294 2.461 ;
     RECT  40.215 2.371 41.814 2.461 ;
     RECT  45.18 2.413 45.897 2.461 ;
     RECT  56.415 2.413 58.806 2.461 ;
     RECT  1.908 2.371 37.602 2.491 ;
     RECT  38.34 2.461 41.958 2.491 ;
     RECT  59.688 2.335 60.102 2.491 ;
     RECT  45.18 2.461 46.278 2.497 ;
     RECT  56.415 2.461 58.878 2.533 ;
     RECT  59.688 2.491 60.534 2.533 ;
     RECT  61.632 2.371 62.514 2.533 ;
     RECT  44.424 2.497 46.278 2.569 ;
     RECT  56.415 2.533 60.534 2.569 ;
     RECT  1.908 2.491 41.958 2.597 ;
     RECT  44.388 2.569 46.278 2.605 ;
     RECT  53.82 2.371 55.386 2.635 ;
     RECT  56.376 2.569 60.534 2.635 ;
     RECT  21.888 2.597 41.958 2.641 ;
     RECT  43.092 2.299 43.11 2.641 ;
     RECT  52.452 2.299 52.902 2.641 ;
     RECT  61.596 2.533 62.514 2.641 ;
     RECT  51.015 2.413 51.297 2.731 ;
     RECT  21.888 2.641 43.11 2.767 ;
     RECT  44.388 2.605 46.962 2.767 ;
     RECT  53.82 2.635 60.534 2.767 ;
     RECT  61.56 2.641 62.514 2.767 ;
     RECT  44.28 2.767 46.962 2.803 ;
     RECT  53.82 2.767 62.514 2.839 ;
     RECT  21.888 2.767 43.182 2.861 ;
     RECT  53.748 2.839 62.514 2.875 ;
     RECT  53.748 2.875 62.55 2.911 ;
     RECT  44.208 2.803 46.962 3.037 ;
     RECT  50.472 2.731 51.297 3.037 ;
     RECT  37.404 2.861 43.182 3.073 ;
     RECT  50.472 3.037 51.318 3.073 ;
     RECT  52.092 2.641 52.902 3.073 ;
     RECT  53.748 2.911 62.586 3.073 ;
     RECT  1.908 2.597 21.114 3.137 ;
     RECT  37.404 3.073 43.326 3.145 ;
     RECT  44.136 3.037 46.962 3.145 ;
     RECT  53.748 3.073 62.694 3.145 ;
     RECT  37.404 3.145 46.962 3.181 ;
     RECT  53.676 3.145 62.694 3.271 ;
     RECT  64.584 3.145 64.602 3.299 ;
     RECT  1.98 3.137 21.114 3.415 ;
     RECT  21.888 2.861 36.63 3.415 ;
     RECT  50.472 3.073 52.902 3.415 ;
     RECT  53.676 3.271 62.766 3.415 ;
     RECT  50.184 3.415 62.766 3.451 ;
     RECT  64.296 3.415 64.422 3.451 ;
     RECT  1.98 3.415 36.63 3.569 ;
     RECT  37.404 3.181 47.142 3.577 ;
     RECT  50.184 3.451 62.874 3.577 ;
     RECT  64.188 3.451 64.422 3.685 ;
     RECT  50.112 3.577 62.874 3.811 ;
     RECT  63.972 3.685 64.422 3.839 ;
     RECT  31.608 3.569 36.63 3.875 ;
     RECT  1.98 3.569 30.798 3.911 ;
     RECT  37.404 3.577 47.394 3.955 ;
     RECT  31.608 3.875 35.91 3.983 ;
     RECT  37.404 3.955 47.502 3.991 ;
     RECT  63.972 3.839 64.386 3.991 ;
     RECT  36.756 3.991 47.502 4.117 ;
     RECT  48.24 3.955 48.258 4.117 ;
     RECT  63.936 3.991 64.386 4.117 ;
     RECT  31.608 3.983 35.874 4.217 ;
     RECT  50.04 3.811 62.874 4.261 ;
     RECT  36.756 4.117 48.474 4.415 ;
     RECT  49.392 4.261 62.874 4.423 ;
     RECT  63.864 4.117 64.386 4.423 ;
     RECT  1.98 3.911 30.654 4.531 ;
     RECT  1.944 4.531 30.654 4.559 ;
     RECT  27.972 4.559 30.654 4.693 ;
     RECT  31.608 4.217 35.586 4.693 ;
     RECT  49.392 4.423 64.386 4.729 ;
     RECT  36.756 4.415 48.294 4.801 ;
     RECT  49.032 4.729 64.386 4.891 ;
     RECT  49.032 4.891 64.422 4.919 ;
     RECT  49.032 4.919 62.442 4.955 ;
     RECT  63.396 4.919 64.422 4.999 ;
     RECT  63.396 4.999 64.566 5.071 ;
     RECT  36.684 4.801 48.294 5.161 ;
     RECT  49.032 4.955 53.55 5.161 ;
     RECT  36.684 5.161 53.55 5.305 ;
     RECT  27.972 4.693 35.586 5.341 ;
     RECT  36.648 5.305 53.55 5.341 ;
     RECT  1.944 4.559 27.234 5.575 ;
     RECT  27.972 5.341 53.55 5.575 ;
     RECT  63.396 5.071 64.782 5.701 ;
     RECT  1.944 5.575 53.55 5.881 ;
     RECT  63.396 5.701 65.574 5.881 ;
     RECT  1.944 5.881 53.622 6.115 ;
     RECT  54.396 4.955 62.442 6.115 ;
     RECT  63.396 5.881 65.61 6.151 ;
     RECT  1.944 6.115 62.442 6.241 ;
     RECT  1.944 6.241 62.478 6.275 ;
     RECT  63.396 6.151 65.646 6.385 ;
     RECT  54.504 6.275 62.478 6.421 ;
     RECT  63.396 6.385 65.718 6.539 ;
     RECT  54.504 6.421 62.514 6.647 ;
     RECT  63.756 6.539 65.718 6.691 ;
     RECT  67.215 2.413 67.497 7.051 ;
     RECT  54.648 6.647 62.514 7.357 ;
     RECT  63.756 6.691 65.754 7.357 ;
     RECT  66.492 7.051 67.497 7.357 ;
     RECT  54.648 7.357 67.497 7.393 ;
     RECT  1.944 6.275 53.55 7.501 ;
     RECT  54.432 7.393 67.497 7.501 ;
     RECT  1.944 7.501 67.497 7.799 ;
     RECT  1.944 7.799 4.554 7.889 ;
     RECT  5.364 7.799 67.497 7.925 ;
     RECT  54.18 7.925 67.497 8.159 ;
     RECT  54.18 8.159 65.718 8.303 ;
     RECT  54.18 8.303 65.682 8.573 ;
     RECT  1.944 7.889 4.518 8.851 ;
     RECT  5.652 7.925 53.298 8.851 ;
     RECT  54.18 8.573 60.966 8.851 ;
     RECT  61.704 8.573 65.682 9.085 ;
     RECT  66.492 8.159 67.497 9.085 ;
     RECT  5.652 8.851 60.966 9.355 ;
     RECT  61.704 9.085 67.497 9.355 ;
     RECT  5.652 9.355 67.497 10.193 ;
     RECT  5.652 10.193 52.542 10.205 ;
     RECT  6.912 10.205 52.542 10.319 ;
     RECT  6.912 10.319 52.434 10.463 ;
     RECT  53.316 10.193 67.497 10.625 ;
     RECT  43.884 10.463 52.434 10.781 ;
     RECT  5.652 10.205 6.102 10.939 ;
     RECT  6.912 10.463 42.894 10.939 ;
     RECT  53.316 10.625 60.534 11.003 ;
     RECT  5.652 10.939 42.894 11.039 ;
     RECT  61.272 10.625 67.497 11.039 ;
     RECT  53.316 11.003 53.694 11.101 ;
     RECT  43.884 10.781 52.29 11.129 ;
     RECT  6.876 11.039 42.894 11.209 ;
     RECT  43.884 11.129 51.894 11.209 ;
     RECT  61.38 11.039 67.497 11.237 ;
     RECT  1.944 8.851 4.626 11.371 ;
     RECT  5.652 11.039 6.102 11.371 ;
     RECT  53.136 11.101 53.694 11.749 ;
     RECT  54.432 11.003 60.534 11.749 ;
     RECT  53.136 11.749 60.534 11.821 ;
     RECT  6.876 11.209 51.894 11.995 ;
     RECT  53.028 11.821 60.678 11.995 ;
     RECT  1.944 11.371 6.102 12.091 ;
     RECT  6.876 11.995 60.678 12.091 ;
     RECT  61.416 11.237 67.497 12.091 ;
     RECT  1.944 12.091 6.138 12.361 ;
     RECT  6.876 12.091 67.497 12.361 ;
     RECT  1.944 12.361 67.497 12.551 ;
     RECT  1.944 12.551 54.954 12.557 ;
     RECT  52.416 12.557 54.954 12.587 ;
     RECT  1.944 12.557 51.498 13.441 ;
     RECT  52.416 12.587 54.738 13.441 ;
     RECT  55.8 12.551 67.497 13.441 ;
     RECT  55.764 13.441 67.497 13.627 ;
     RECT  1.944 13.441 54.738 13.639 ;
     RECT  55.728 13.627 67.497 13.639 ;
     RECT  1.944 13.639 67.497 13.667 ;
     RECT  1.944 13.667 54.162 14.521 ;
     RECT  55.152 13.667 67.497 14.747 ;
     RECT  1.944 14.521 54.27 14.791 ;
     RECT  55.152 14.747 66.438 14.791 ;
     RECT  1.944 14.791 66.438 15.053 ;
     RECT  1.944 15.053 40.626 15.485 ;
     RECT  41.4 15.053 66.438 15.719 ;
     RECT  41.58 15.719 66.438 15.755 ;
     RECT  41.832 15.755 66.438 15.791 ;
     RECT  42.084 15.791 66.438 15.863 ;
     RECT  7.308 15.485 40.626 15.871 ;
     RECT  52.344 15.863 66.438 16.061 ;
     RECT  42.084 15.863 51.39 16.259 ;
     RECT  1.944 15.485 6.57 16.375 ;
     RECT  7.308 15.871 40.806 16.375 ;
     RECT  1.944 16.375 40.806 16.609 ;
     RECT  1.944 16.609 40.986 16.645 ;
     RECT  42.084 16.259 51.297 16.645 ;
     RECT  52.344 16.061 65.754 16.645 ;
     RECT  52.02 16.645 65.754 16.871 ;
     RECT  52.344 16.871 65.754 16.943 ;
     RECT  52.524 16.943 65.754 17.491 ;
     RECT  1.944 16.645 51.297 17.681 ;
     RECT  52.524 17.491 66.222 17.725 ;
     RECT  52.488 17.725 66.222 18.031 ;
     RECT  52.308 18.031 66.222 18.157 ;
     RECT  39.384 17.681 51.297 18.301 ;
     RECT  52.02 18.157 66.222 18.301 ;
     RECT  1.944 17.681 38.538 18.599 ;
     RECT  39.384 18.301 66.222 18.689 ;
     RECT  1.98 18.599 38.538 18.931 ;
     RECT  39.384 18.689 51.39 18.931 ;
     RECT  1.98 18.931 51.39 18.959 ;
     RECT  52.38 18.689 66.222 20.039 ;
     RECT  2.016 18.959 51.297 20.191 ;
     RECT  66.204 20.039 66.222 20.191 ;
     RECT  52.38 20.039 65.394 20.425 ;
     RECT  52.236 20.425 65.394 20.453 ;
     RECT  66.204 20.191 66.33 20.461 ;
     RECT  67.215 14.747 67.497 20.461 ;
     RECT  64.188 20.453 65.394 20.573 ;
     RECT  52.236 20.453 63.342 20.579 ;
     RECT  2.016 20.191 51.39 21.001 ;
     RECT  52.236 20.579 59.382 21.001 ;
     RECT  2.016 21.001 59.382 21.263 ;
     RECT  64.188 20.573 65.322 21.541 ;
     RECT  60.192 20.579 63.306 21.631 ;
     RECT  64.188 21.541 65.358 21.631 ;
     RECT  53.172 21.263 59.382 21.677 ;
     RECT  60.192 21.631 65.358 21.695 ;
     RECT  58.32 21.677 59.382 21.775 ;
     RECT  60.192 21.695 63.882 21.775 ;
     RECT  2.016 21.263 51.297 21.929 ;
     RECT  53.172 21.677 57.546 21.929 ;
     RECT  52.2 21.263 52.362 22.171 ;
     RECT  53.172 21.929 57.402 22.171 ;
     RECT  66.204 20.461 67.497 22.243 ;
     RECT  66.132 22.243 67.497 22.379 ;
     RECT  58.32 21.775 63.882 22.585 ;
     RECT  58.248 22.585 63.882 22.621 ;
     RECT  64.872 21.695 65.358 22.621 ;
     RECT  58.248 22.621 65.358 22.739 ;
     RECT  2.124 21.929 51.297 22.891 ;
     RECT  52.2 22.171 57.402 22.891 ;
     RECT  2.124 22.891 57.402 23.083 ;
     RECT  2.124 23.083 57.726 23.701 ;
     RECT  58.5 22.739 65.358 23.701 ;
     RECT  2.124 23.701 65.358 24.133 ;
     RECT  66.204 22.379 67.497 24.133 ;
     RECT  2.124 24.133 67.497 24.269 ;
     RECT  2.376 24.269 67.497 24.629 ;
     RECT  2.376 24.629 51.822 24.899 ;
     RECT  2.376 24.899 51.57 25.547 ;
     RECT  52.632 24.629 67.497 25.591 ;
     RECT  36.792 25.547 51.57 25.681 ;
     RECT  36.792 25.681 51.606 25.825 ;
     RECT  36.792 25.825 51.642 25.861 ;
     RECT  52.38 25.591 67.497 25.861 ;
     RECT  2.376 25.547 35.982 26.293 ;
     RECT  36.792 25.861 67.497 26.293 ;
     RECT  2.376 26.293 67.497 26.941 ;
     RECT  2.304 26.941 67.497 28.211 ;
     RECT  2.304 28.211 41.094 29.093 ;
     RECT  39.384 29.093 41.094 29.101 ;
     RECT  41.832 28.211 67.497 29.101 ;
     RECT  2.304 29.093 38.394 29.911 ;
     RECT  2.304 29.911 38.43 30.029 ;
     RECT  2.304 30.029 35.982 30.065 ;
     RECT  39.384 29.101 67.497 30.073 ;
     RECT  36.72 30.029 38.43 30.137 ;
     RECT  36.792 30.137 38.43 30.145 ;
     RECT  39.168 30.073 67.497 30.145 ;
     RECT  19.908 30.065 35.982 30.173 ;
     RECT  36.792 30.145 67.497 30.955 ;
     RECT  19.944 30.173 35.982 31.117 ;
     RECT  36.756 30.955 67.497 31.117 ;
     RECT  2.304 30.065 19.062 31.261 ;
     RECT  19.944 31.117 67.698 31.261 ;
     RECT  2.304 31.261 67.698 31.487 ;
     RECT  19.692 31.487 67.698 31.495 ;
     RECT  19.692 31.495 67.734 31.685 ;
     RECT  20.16 31.685 67.734 31.765 ;
     RECT  20.16 31.765 67.806 31.805 ;
     RECT  36.792 31.805 67.806 32.071 ;
     RECT  36.792 32.071 67.914 32.305 ;
     RECT  36.792 32.305 68.166 32.431 ;
     RECT  2.304 31.487 18.897 32.491 ;
     RECT  36.792 32.431 68.238 32.575 ;
     RECT  20.16 31.805 35.982 32.701 ;
     RECT  36.756 32.575 68.238 32.701 ;
     RECT  2.304 32.491 18.954 32.729 ;
     RECT  20.16 32.701 68.238 32.801 ;
     RECT  12.42 32.729 18.954 33.007 ;
     RECT  39.456 32.801 68.238 33.007 ;
     RECT  39.456 33.007 68.274 33.583 ;
     RECT  2.304 32.729 11.682 33.691 ;
     RECT  12.42 33.007 19.422 33.691 ;
     RECT  2.304 33.691 19.422 33.961 ;
     RECT  20.16 32.801 38.682 33.961 ;
     RECT  39.42 33.583 68.274 34.151 ;
     RECT  2.304 33.961 38.682 34.159 ;
     RECT  39.42 34.151 54.414 34.159 ;
     RECT  55.44 34.151 68.274 34.501 ;
     RECT  2.304 34.159 54.414 34.781 ;
     RECT  55.44 34.501 68.346 34.925 ;
     RECT  19.62 34.781 54.414 35.005 ;
     RECT  55.44 34.925 58.194 35.041 ;
     RECT  55.296 35.041 58.194 35.851 ;
     RECT  59.004 34.925 68.346 35.851 ;
     RECT  19.62 35.005 54.522 36.121 ;
     RECT  19.62 36.121 54.558 36.311 ;
     RECT  2.304 34.781 18.897 36.517 ;
     RECT  37.188 36.311 54.558 36.851 ;
     RECT  37.26 36.851 54.558 36.895 ;
     RECT  55.296 35.851 68.346 36.895 ;
     RECT  2.268 36.517 18.897 36.931 ;
     RECT  19.62 36.311 36.414 36.931 ;
     RECT  2.268 36.931 36.414 37.049 ;
     RECT  21.24 37.049 36.414 37.121 ;
     RECT  2.268 37.049 20.502 37.157 ;
     RECT  2.268 37.157 20.394 37.193 ;
     RECT  2.268 37.193 20.178 37.391 ;
     RECT  37.26 36.895 68.346 37.463 ;
     RECT  21.348 37.121 36.414 37.597 ;
     RECT  37.26 37.463 37.746 37.597 ;
     RECT  21.348 37.597 37.746 37.625 ;
     RECT  2.304 37.391 20.178 38.005 ;
     RECT  21.384 37.625 37.746 38.407 ;
     RECT  38.664 37.463 68.346 38.407 ;
     RECT  2.304 38.005 20.322 38.443 ;
     RECT  2.304 38.443 20.538 38.551 ;
     RECT  21.384 38.407 68.346 38.551 ;
     RECT  2.304 38.551 68.346 39.389 ;
     RECT  2.376 39.389 68.346 39.515 ;
     RECT  27.612 39.515 68.346 40.163 ;
     RECT  29.16 40.163 68.346 40.361 ;
     RECT  2.376 39.515 26.874 40.639 ;
     RECT  27.612 40.163 28.206 40.639 ;
     RECT  30.744 40.361 68.346 40.711 ;
     RECT  2.376 40.639 28.206 40.945 ;
     RECT  29.16 40.361 29.754 40.945 ;
     RECT  30.744 40.711 68.526 41.071 ;
     RECT  30.744 41.071 68.562 41.107 ;
     RECT  2.376 40.945 29.754 41.179 ;
     RECT  30.672 41.107 68.562 41.179 ;
     RECT  2.376 41.179 68.562 41.243 ;
     RECT  11.232 41.243 68.562 41.515 ;
     RECT  11.232 41.515 68.67 41.909 ;
     RECT  2.376 41.243 10.422 41.917 ;
     RECT  11.232 41.909 28.134 41.945 ;
     RECT  28.908 41.909 68.67 42.061 ;
     RECT  2.304 41.917 10.422 42.151 ;
     RECT  11.232 41.945 27.99 42.151 ;
     RECT  28.908 42.061 68.706 42.601 ;
     RECT  2.304 42.151 27.99 42.799 ;
     RECT  28.908 42.601 68.886 42.799 ;
     RECT  2.304 42.799 68.886 43.141 ;
     RECT  2.304 43.141 68.922 43.681 ;
     RECT  2.304 43.681 68.994 43.808 ;
     RECT  21.888 43.808 68.994 43.871 ;
     RECT  2.304 43.808 21.042 44.609 ;
     RECT  21.888 43.871 68.922 44.789 ;
     RECT  11.304 44.609 21.042 44.887 ;
     RECT  2.304 44.609 10.566 45.059 ;
     RECT  6.012 45.059 10.566 45.293 ;
     RECT  11.304 44.887 21.078 45.301 ;
     RECT  2.304 45.059 5.238 45.389 ;
     RECT  21.888 44.789 68.706 45.419 ;
     RECT  6.084 45.293 10.566 45.463 ;
     RECT  11.304 45.301 21.15 45.463 ;
     RECT  6.084 45.463 21.15 45.661 ;
     RECT  21.888 45.419 68.562 45.661 ;
     RECT  6.084 45.661 68.562 45.833 ;
     RECT  7.815 45.833 68.562 46.031 ;
     RECT  64.836 46.031 68.562 46.363 ;
     RECT  7.815 46.031 64.062 46.409 ;
     RECT  2.304 45.389 5.094 46.571 ;
     RECT  6.12 45.833 7.074 46.651 ;
     RECT  64.836 46.363 68.67 46.651 ;
     RECT  5.688 46.651 7.074 46.741 ;
     RECT  7.815 46.409 21.366 46.741 ;
     RECT  22.14 46.409 64.062 46.885 ;
     RECT  64.836 46.651 68.706 46.885 ;
     RECT  22.14 46.885 68.706 46.921 ;
     RECT  2.304 46.571 4.77 46.949 ;
     RECT  22.14 46.921 68.994 47.039 ;
     RECT  22.14 47.039 68.706 47.111 ;
     RECT  5.688 46.741 21.366 47.191 ;
     RECT  22.14 47.111 25.542 47.191 ;
     RECT  5.688 47.191 25.542 47.309 ;
     RECT  5.688 47.309 25.362 47.891 ;
     RECT  2.304 46.949 4.59 48.271 ;
     RECT  5.688 47.891 19.53 48.271 ;
     RECT  26.316 47.111 68.706 48.271 ;
     RECT  20.376 47.891 25.362 48.505 ;
     RECT  2.304 48.271 19.53 48.659 ;
     RECT  11.052 48.659 19.53 48.667 ;
     RECT  20.376 48.505 25.47 48.667 ;
     RECT  26.208 48.271 68.706 48.811 ;
     RECT  11.052 48.667 25.47 48.973 ;
     RECT  26.208 48.811 68.85 48.973 ;
     RECT  2.304 48.659 10.242 48.989 ;
     RECT  11.052 48.973 68.85 49.351 ;
     RECT  11.052 49.351 68.994 49.577 ;
     RECT  5.436 48.989 10.242 49.621 ;
     RECT  11.052 49.577 68.706 49.621 ;
     RECT  2.304 48.989 4.554 49.855 ;
     RECT  2.304 49.855 4.59 49.891 ;
     RECT  5.436 49.621 68.706 49.891 ;
     RECT  2.304 49.891 68.706 49.919 ;
     RECT  2.304 49.919 68.454 50.045 ;
     RECT  2.415 50.045 68.454 50.935 ;
     RECT  2.415 50.935 68.67 51.395 ;
     RECT  2.415 51.395 60.57 51.475 ;
     RECT  2.376 51.475 60.57 51.629 ;
     RECT  61.308 51.395 68.67 51.781 ;
     RECT  2.376 51.629 52.182 51.869 ;
     RECT  5.004 51.869 52.182 52.277 ;
     RECT  52.992 51.629 60.57 52.321 ;
     RECT  61.308 51.781 69.066 52.321 ;
     RECT  52.992 52.321 69.066 52.411 ;
     RECT  52.92 52.411 69.066 52.448 ;
     RECT  10.656 52.277 52.182 52.709 ;
     RECT  2.376 51.869 4.23 52.861 ;
     RECT  5.004 52.277 9.846 52.861 ;
     RECT  52.956 52.448 69.066 52.889 ;
     RECT  2.376 52.861 9.846 53.285 ;
     RECT  10.764 52.709 52.182 53.329 ;
     RECT  52.956 52.889 56.754 53.329 ;
     RECT  10.764 53.329 56.754 53.563 ;
     RECT  10.584 53.563 56.754 53.671 ;
     RECT  57.528 52.889 69.066 53.671 ;
     RECT  2.415 53.285 9.846 53.941 ;
     RECT  10.584 53.671 69.066 53.941 ;
     RECT  2.415 53.941 69.066 54.167 ;
     RECT  2.415 54.167 57.006 54.949 ;
     RECT  57.744 54.167 69.066 54.949 ;
     RECT  2.415 54.949 69.066 55.211 ;
     RECT  3.924 55.211 69.066 55.517 ;
     RECT  12.204 55.517 69.066 55.787 ;
     RECT  3.924 55.517 11.43 56.065 ;
     RECT  3.78 56.065 11.43 56.093 ;
     RECT  3.78 56.093 4.482 56.219 ;
     RECT  5.256 56.093 11.43 56.327 ;
     RECT  5.364 56.327 11.43 56.371 ;
     RECT  12.204 55.787 48.906 56.371 ;
     RECT  5.364 56.371 48.906 56.533 ;
     RECT  49.788 55.787 69.066 56.533 ;
     RECT  4.356 56.219 4.482 56.759 ;
     RECT  4.356 56.759 4.374 56.795 ;
     RECT  5.364 56.533 69.066 57.029 ;
     RECT  5.436 57.029 6.966 57.299 ;
     RECT  6.66 57.299 6.966 57.335 ;
     RECT  5.436 57.299 5.814 57.479 ;
     RECT  7.815 57.029 69.066 57.533 ;
     RECT  5.688 57.479 5.814 57.641 ;
     RECT  6.66 57.335 6.822 57.677 ;
     RECT  5.796 57.641 5.814 57.713 ;
     RECT  7.815 57.533 10.818 57.983 ;
     RECT  7.815 57.983 10.242 58.019 ;
     RECT  9.108 58.019 10.242 58.109 ;
     RECT  9.108 58.109 9.702 58.181 ;
     RECT  9.684 58.181 9.702 58.253 ;
     RECT  11.628 57.533 69.066 58.459 ;
     RECT  11.592 58.459 69.066 58.531 ;
     RECT  11.592 58.531 69.138 58.685 ;
     RECT  11.736 58.685 69.138 59.369 ;
     RECT  11.736 59.369 57.798 59.701 ;
     RECT  11.628 59.701 57.798 60.115 ;
     RECT  58.572 59.369 69.138 60.115 ;
     RECT  11.628 60.115 69.138 60.269 ;
     RECT  11.628 60.269 43.254 61.349 ;
     RECT  11.808 61.349 43.254 61.393 ;
     RECT  44.028 60.269 69.138 61.393 ;
     RECT  11.808 61.393 69.138 62.275 ;
     RECT  11.664 62.275 69.138 62.465 ;
     RECT  33.084 62.465 69.138 62.501 ;
     RECT  11.664 62.465 32.346 62.909 ;
     RECT  12.384 62.909 32.346 62.969 ;
     RECT  12.816 62.969 32.346 63.245 ;
     RECT  33.084 62.501 69.102 63.389 ;
     RECT  12.816 63.245 31.41 63.509 ;
     RECT  32.148 63.245 32.346 63.661 ;
     RECT  33.084 63.389 46.206 63.661 ;
     RECT  12.924 63.509 31.41 63.779 ;
     RECT  12.996 63.779 31.41 63.851 ;
     RECT  32.148 63.661 46.206 64.129 ;
     RECT  32.148 64.129 46.242 64.193 ;
     RECT  38.628 64.193 46.242 64.319 ;
     RECT  47.124 63.389 69.102 64.355 ;
     RECT  47.34 64.355 69.102 64.363 ;
     RECT  13.215 63.851 31.41 64.435 ;
     RECT  32.148 64.193 37.89 64.435 ;
     RECT  13.215 64.435 37.89 64.967 ;
     RECT  26.64 64.967 37.89 65.011 ;
     RECT  38.628 64.319 46.17 65.011 ;
     RECT  47.34 64.363 69.174 65.129 ;
     RECT  26.64 65.011 46.17 65.165 ;
     RECT  48.132 65.129 69.174 65.165 ;
     RECT  32.688 65.165 46.17 65.245 ;
     RECT  47.34 65.129 47.358 65.245 ;
     RECT  48.24 65.165 69.174 65.245 ;
     RECT  69.948 62.671 69.966 65.245 ;
     RECT  32.688 65.245 47.358 65.543 ;
     RECT  14.364 64.967 25.902 65.707 ;
     RECT  26.64 65.165 31.914 65.707 ;
     RECT  14.364 65.707 31.914 66.011 ;
     RECT  32.796 65.543 47.358 66.055 ;
     RECT  48.24 65.245 69.966 66.055 ;
     RECT  32.796 66.055 69.966 66.083 ;
     RECT  14.364 66.011 21.87 66.187 ;
     RECT  14.292 66.187 21.87 66.209 ;
     RECT  39.852 66.083 69.966 66.253 ;
     RECT  14.292 66.209 21.834 66.479 ;
     RECT  22.68 66.011 31.914 66.487 ;
     RECT  16.056 66.479 21.834 66.515 ;
     RECT  14.292 66.479 14.31 66.551 ;
     RECT  15.048 66.479 15.246 66.587 ;
     RECT  32.796 66.083 39.114 66.595 ;
     RECT  15.048 66.587 15.066 66.623 ;
     RECT  16.344 66.515 21.834 66.701 ;
     RECT  22.68 66.487 31.986 67.099 ;
     RECT  32.724 66.595 39.114 67.099 ;
     RECT  22.68 67.099 39.114 67.135 ;
     RECT  39.852 66.253 70.182 67.135 ;
     RECT  22.68 67.135 70.182 67.163 ;
     RECT  16.344 66.701 21.546 67.243 ;
     RECT  22.68 67.163 24.966 67.261 ;
     RECT  16.308 67.243 21.546 67.289 ;
     RECT  22.284 67.261 24.966 67.325 ;
     RECT  25.776 67.163 70.182 67.397 ;
     RECT  16.524 67.289 21.546 67.441 ;
     RECT  22.284 67.325 22.662 67.441 ;
     RECT  30.744 67.397 70.182 67.441 ;
     RECT  16.524 67.441 22.662 67.469 ;
     RECT  23.616 67.325 24.966 67.559 ;
     RECT  25.776 67.397 29.697 67.595 ;
     RECT  25.812 67.595 29.697 67.667 ;
     RECT  27.324 67.667 29.697 67.829 ;
     RECT  30.744 67.441 70.542 67.829 ;
     RECT  23.616 67.559 24.858 67.865 ;
     RECT  25.812 67.667 26.442 67.865 ;
     RECT  44.676 67.829 70.542 67.865 ;
     RECT  17.028 67.469 22.662 67.901 ;
     RECT  24.015 67.865 24.858 67.901 ;
     RECT  25.92 67.865 26.442 67.901 ;
     RECT  27.36 67.829 29.697 67.901 ;
     RECT  28.476 67.901 29.697 67.937 ;
     RECT  25.92 67.901 26.118 67.973 ;
     RECT  28.476 67.937 28.494 67.973 ;
     RECT  25.92 67.973 25.938 68.009 ;
     RECT  17.028 67.901 20.862 68.093 ;
     RECT  17.028 68.093 20.574 68.099 ;
     RECT  22.104 67.901 22.662 68.099 ;
     RECT  31.356 67.829 43.902 68.099 ;
     RECT  22.104 68.099 22.446 68.135 ;
     RECT  34.452 68.099 35.874 68.207 ;
     RECT  17.028 68.099 18.897 68.243 ;
     RECT  31.356 68.099 32.706 68.243 ;
     RECT  17.028 68.243 17.046 68.279 ;
     RECT  34.668 68.207 35.097 68.279 ;
     RECT  17.892 68.243 18.897 68.369 ;
     RECT  19.656 68.099 20.466 68.369 ;
     RECT  32.076 68.243 32.094 68.369 ;
     RECT  36.72 68.099 43.83 68.369 ;
     RECT  35.856 68.207 35.874 68.381 ;
     RECT  38.808 68.369 43.83 68.381 ;
     RECT  18.36 68.369 18.897 68.405 ;
     RECT  20.34 68.369 20.358 68.405 ;
     RECT  36.864 68.369 37.818 68.405 ;
     RECT  38.808 68.381 43.614 68.405 ;
     RECT  44.748 67.865 70.542 68.405 ;
     RECT  37.044 68.405 37.818 68.441 ;
     RECT  39.096 68.405 43.614 68.441 ;
     RECT  44.82 68.405 70.542 68.441 ;
     RECT  39.6 68.441 43.614 68.477 ;
     RECT  39.6 68.477 43.326 68.513 ;
     RECT  37.8 68.441 37.818 68.675 ;
     RECT  39.6 68.513 42.75 68.675 ;
     RECT  40.215 68.675 42.75 68.711 ;
     RECT  44.928 68.441 70.542 68.717 ;
     RECT  40.215 68.711 42.03 68.783 ;
     RECT  44.928 68.717 46.602 68.783 ;
     RECT  40.215 68.783 41.562 68.819 ;
     RECT  2.415 55.211 2.697 68.867 ;
     RECT  7.815 58.019 8.097 68.867 ;
     RECT  13.215 64.967 13.497 68.867 ;
     RECT  18.615 68.405 18.897 68.867 ;
     RECT  24.015 67.901 24.297 68.867 ;
     RECT  29.415 67.937 29.697 68.867 ;
     RECT  34.815 68.279 35.097 68.867 ;
     RECT  40.215 68.819 40.497 68.867 ;
     RECT  44.928 68.783 45.897 68.867 ;
     RECT  47.412 68.717 70.542 68.909 ;
     RECT  47.736 68.909 48.474 68.945 ;
     RECT  49.32 68.909 49.59 68.945 ;
     RECT  50.508 68.909 51.105 68.945 ;
     RECT  51.84 68.909 70.542 68.945 ;
     RECT  44.928 68.867 45.705 68.981 ;
     RECT  47.916 68.945 47.934 68.981 ;
     RECT  49.464 68.945 49.59 68.981 ;
     RECT  51.84 68.945 52.182 68.981 ;
     RECT  52.92 68.945 70.542 68.981 ;
     RECT  51.84 68.981 51.858 69.005 ;
     RECT  52.992 68.981 54.738 69.005 ;
     RECT  2.415 68.867 2.505 69.137 ;
     RECT  7.815 68.867 7.905 69.137 ;
     RECT  13.215 68.867 13.305 69.137 ;
     RECT  18.615 68.867 18.705 69.137 ;
     RECT  24.015 68.867 24.105 69.137 ;
     RECT  29.415 68.867 29.505 69.137 ;
     RECT  34.815 68.867 34.905 69.137 ;
     RECT  40.215 68.867 40.305 69.137 ;
     RECT  45.615 68.981 45.705 69.137 ;
     RECT  51.015 68.945 51.105 69.137 ;
     RECT  55.584 68.981 70.542 70.403 ;
     RECT  55.764 70.403 70.542 70.673 ;
     RECT  55.836 70.673 70.542 70.781 ;
     RECT  56.448 70.781 70.542 70.829 ;
     RECT  57.06 70.829 61.614 70.877 ;
     RECT  52.992 69.005 54.054 71.165 ;
     RECT  57.492 70.877 58.05 71.165 ;
     RECT  58.932 70.877 58.95 71.165 ;
     RECT  59.976 70.877 61.254 71.165 ;
     RECT  62.388 70.829 70.542 71.165 ;
     RECT  54.036 71.165 54.054 71.213 ;
     RECT  57.564 71.165 58.05 71.213 ;
     RECT  52.992 71.165 53.01 71.261 ;
     RECT  57.564 71.213 57.582 71.261 ;
     RECT  60.696 71.165 60.714 71.261 ;
     RECT  62.712 71.165 62.73 71.261 ;
     RECT  68.58 71.165 68.598 71.261 ;
    LAYER M4 ;
     RECT  0.805 6.336 0.901 6.36 ;
     RECT  0.901 6.336 0.997 6.6 ;
     RECT  0.997 6 1.093 6.6 ;
     RECT  0.709 0.192 1.381 0.216 ;
     RECT  1.381 0.144 1.669 0.216 ;
     RECT  1.093 5.136 1.765 6.6 ;
     RECT  1.765 4.752 1.957 6.6 ;
     RECT  1.853 1.728 2.116 1.752 ;
     RECT  1.957 3.984 2.293 6.6 ;
     RECT  2.252 10.848 2.293 10.872 ;
     RECT  1.669 0.096 2.369 0.216 ;
     RECT  2.293 10.848 2.401 11.448 ;
     RECT  2.116 1.728 2.408 1.8 ;
     RECT  2.293 3.984 2.408 6.936 ;
     RECT  2.401 10.848 2.408 11.544 ;
     RECT  2.365 26.592 2.408 26.616 ;
     RECT  2.365 27.888 2.408 27.912 ;
     RECT  2.329 29.616 2.408 29.64 ;
     RECT  2.293 34.128 2.408 34.152 ;
     RECT  2.293 35.184 2.408 35.208 ;
     RECT  2.293 36.576 2.408 36.6 ;
     RECT  2.408 1.728 2.512 69.132 ;
     RECT  2.512 1.728 2.704 68.862 ;
     RECT  2.704 33.12 2.801 34.152 ;
     RECT  2.704 11.424 2.819 11.544 ;
     RECT  2.704 22.08 2.819 23.256 ;
     RECT  2.704 27.888 2.819 28.2 ;
     RECT  2.704 29.616 2.819 32.088 ;
     RECT  2.801 33.12 2.819 33.432 ;
     RECT  2.819 30.288 2.837 32.088 ;
     RECT  2.704 36.48 2.845 36.984 ;
     RECT  2.704 6.144 2.867 6.984 ;
     RECT  2.819 11.52 2.867 11.544 ;
     RECT  2.837 32.064 2.867 32.088 ;
     RECT  2.819 33.12 2.867 33.144 ;
     RECT  2.704 1.728 2.873 2.904 ;
     RECT  2.369 0.096 2.909 0.12 ;
     RECT  2.704 15.36 2.915 16.008 ;
     RECT  2.915 15.36 2.981 15.48 ;
     RECT  2.873 2.832 3.017 2.904 ;
     RECT  3.017 2.832 3.277 2.856 ;
     RECT  2.704 5.136 3.277 5.16 ;
     RECT  2.704 38.304 3.629 39.816 ;
     RECT  2.867 6.288 3.635 6.984 ;
     RECT  2.845 36.96 3.665 36.984 ;
     RECT  2.704 45.024 3.697 45.384 ;
     RECT  3.635 6.288 3.773 6.888 ;
     RECT  2.819 22.944 3.805 23.016 ;
     RECT  2.704 42.96 3.809 43.176 ;
     RECT  3.805 22.176 3.841 23.016 ;
     RECT  3.805 50.736 3.841 50.76 ;
     RECT  2.873 1.728 3.877 1.848 ;
     RECT  3.836 31.344 3.877 31.368 ;
     RECT  3.629 38.304 3.881 39.048 ;
     RECT  3.841 22.176 3.912 23.304 ;
     RECT  3.733 34.896 3.913 34.92 ;
     RECT  3.877 31.344 3.923 31.944 ;
     RECT  3.773 6.288 3.949 6.84 ;
     RECT  2.837 30.288 3.953 30.312 ;
     RECT  3.697 45.024 3.953 45.672 ;
     RECT  3.841 50.736 3.953 51.096 ;
     RECT  3.912 22.176 3.973 23.544 ;
     RECT  3.973 21.216 3.985 23.544 ;
     RECT  2.704 46.656 3.989 46.68 ;
     RECT  3.913 17.424 4.129 17.448 ;
     RECT  3.985 21.216 4.165 23.928 ;
     RECT  4.129 17.424 4.237 17.88 ;
     RECT  4.165 20.88 4.237 23.928 ;
     RECT  4.093 10.8 4.241 10.824 ;
     RECT  3.809 43.152 4.241 43.176 ;
     RECT  3.949 5.808 4.273 6.84 ;
     RECT  3.881 38.304 4.277 38.568 ;
     RECT  3.949 18.864 4.309 18.888 ;
     RECT  2.819 28.176 4.309 28.2 ;
     RECT  4.237 17.184 4.381 17.88 ;
     RECT  4.309 18.864 4.381 19.368 ;
     RECT  4.277 38.544 4.385 38.568 ;
     RECT  3.923 31.92 4.417 31.944 ;
     RECT  2.704 26.592 4.453 26.616 ;
     RECT  4.237 20.64 4.499 23.928 ;
     RECT  4.453 25.68 4.537 26.616 ;
     RECT  4.46 52.992 4.547 53.016 ;
     RECT  3.913 48.288 4.549 48.312 ;
     RECT  3.953 50.736 4.549 50.808 ;
     RECT  4.273 5.472 4.561 6.84 ;
     RECT  4.381 17.184 4.597 19.368 ;
     RECT  4.309 28.176 4.597 28.392 ;
     RECT  4.549 48.288 4.636 50.808 ;
     RECT  4.561 5.04 4.637 6.84 ;
     RECT  4.597 17.088 4.637 19.368 ;
     RECT  4.637 6.72 4.709 6.84 ;
     RECT  4.636 50.736 4.709 50.808 ;
     RECT  4.597 27.936 4.837 28.392 ;
     RECT  3.877 1.728 4.849 2.712 ;
     RECT  4.637 17.088 4.849 19.128 ;
     RECT  4.837 27.888 4.849 28.392 ;
     RECT  4.636 48.288 4.853 48.984 ;
     RECT  3.841 54 4.885 54.024 ;
     RECT  3.913 34.08 4.889 34.92 ;
     RECT  4.669 30.624 4.921 30.648 ;
     RECT  4.417 31.92 4.921 32.808 ;
     RECT  4.853 48.288 4.924 48.408 ;
     RECT  4.885 54 4.925 54.168 ;
     RECT  4.499 20.64 4.961 23.016 ;
     RECT  4.849 16.512 4.997 19.128 ;
     RECT  4.637 5.04 5.029 5.496 ;
     RECT  2.981 15.456 5.029 15.48 ;
     RECT  4.961 20.88 5.033 23.016 ;
     RECT  4.709 6.72 5.069 6.792 ;
     RECT  4.709 50.784 5.101 50.808 ;
     RECT  5.029 4.224 5.123 5.496 ;
     RECT  4.849 27.888 5.137 28.536 ;
     RECT  4.997 17.904 5.141 19.128 ;
     RECT  5.033 21.648 5.141 23.016 ;
     RECT  4.889 34.08 5.141 34.776 ;
     RECT  5.137 27.888 5.177 28.968 ;
     RECT  5.029 14.928 5.245 15.48 ;
     RECT  4.997 16.512 5.245 16.872 ;
     RECT  3.953 45.024 5.249 45.384 ;
     RECT  4.885 43.344 5.281 43.368 ;
     RECT  5.281 42.624 5.317 43.368 ;
     RECT  5.069 6.768 5.321 6.792 ;
     RECT  5.141 34.752 5.357 34.776 ;
     RECT  4.921 30.624 5.389 32.808 ;
     RECT  5.281 25.248 5.393 25.272 ;
     RECT  5.353 40.512 5.425 40.536 ;
     RECT  4.849 1.728 5.461 3.096 ;
     RECT  5.425 40.416 5.461 40.536 ;
     RECT  5.317 42.144 5.465 43.368 ;
     RECT  5.245 14.928 5.501 16.872 ;
     RECT  5.389 30.624 5.501 33.096 ;
     RECT  3.769 37.008 5.501 37.032 ;
     RECT  4.537 26.592 5.569 26.616 ;
     RECT  5.501 15.456 5.573 16.872 ;
     RECT  5.141 18.144 5.609 19.128 ;
     RECT  4.925 54.144 5.609 54.168 ;
     RECT  5.101 50.784 5.645 50.856 ;
     RECT  5.461 39.888 5.653 40.536 ;
     RECT  5.609 18.864 5.681 19.128 ;
     RECT  5.501 30.624 5.681 32.808 ;
     RECT  5.653 39.024 5.699 40.536 ;
     RECT  5.699 40.416 5.753 40.536 ;
     RECT  5.681 30.864 5.789 32.808 ;
     RECT  5.641 13.056 5.825 13.08 ;
     RECT  5.681 19.104 5.897 19.128 ;
     RECT  5.465 43.344 5.933 43.368 ;
     RECT  5.177 27.936 5.969 28.968 ;
     RECT  5.465 42.144 5.997 42.312 ;
     RECT  5.929 40.992 6.013 41.016 ;
     RECT  5.123 4.944 6.037 5.496 ;
     RECT  5.569 26.592 6.037 26.808 ;
     RECT  5.893 0.096 6.085 0.12 ;
     RECT  5.573 16.848 6.145 16.872 ;
     RECT  5.969 28.464 6.145 28.968 ;
     RECT  4.021 51.84 6.217 51.864 ;
     RECT  6.037 4.944 6.253 5.784 ;
     RECT  6.145 28.464 6.284 29.112 ;
     RECT  6.217 51.84 6.289 52.2 ;
     RECT  6.085 0.096 6.293 0.168 ;
     RECT  5.141 21.984 6.325 23.016 ;
     RECT  6.145 16.848 6.329 17.112 ;
     RECT  5.789 30.864 6.329 32.76 ;
     RECT  6.325 21.744 6.371 23.064 ;
     RECT  6.284 28.464 6.371 29.64 ;
     RECT  6.253 4.944 6.397 5.976 ;
     RECT  6.325 24.528 6.409 24.552 ;
     RECT  6.397 4.944 6.469 6.504 ;
     RECT  4.501 55.632 6.505 55.656 ;
     RECT  6.505 54.672 6.517 55.656 ;
     RECT  6.371 22.752 6.541 23.064 ;
     RECT  5.461 1.728 6.577 3.72 ;
     RECT  6.371 28.464 6.581 29.112 ;
     RECT  6.517 54.672 6.589 55.992 ;
     RECT  6.289 51.072 6.613 52.2 ;
     RECT  6.613 50.736 6.689 52.2 ;
     RECT  6.505 10.944 6.721 10.968 ;
     RECT  6.037 26.208 6.721 26.808 ;
     RECT  6.329 30.864 6.749 32.472 ;
     RECT  6.577 1.104 6.757 3.72 ;
     RECT  6.469 4.944 6.757 6.888 ;
     RECT  6.721 24.672 6.761 26.808 ;
     RECT  6.581 29.088 6.833 29.112 ;
     RECT  6.757 1.104 6.899 6.888 ;
     RECT  6.899 1.728 6.901 6.888 ;
     RECT  6.689 50.736 7.141 51.864 ;
     RECT  7.141 50.64 7.189 51.864 ;
     RECT  6.293 0.096 7.297 0.12 ;
     RECT  7.189 18.96 7.369 18.984 ;
     RECT  6.371 21.744 7.369 21.768 ;
     RECT  6.541 22.752 7.369 23.352 ;
     RECT  6.749 30.672 7.369 32.472 ;
     RECT  7.34 54.576 7.381 54.6 ;
     RECT  4.924 48.384 7.621 48.408 ;
     RECT  7.405 20.64 7.693 20.664 ;
     RECT  7.369 21.744 7.693 23.352 ;
     RECT  6.761 24.672 7.693 26.232 ;
     RECT  6.901 1.728 7.808 8.424 ;
     RECT  6.721 10.176 7.808 10.968 ;
     RECT  5.573 15.456 7.808 15.48 ;
     RECT  6.329 17.088 7.808 17.112 ;
     RECT  7.369 18.96 7.808 19.56 ;
     RECT  7.693 20.64 7.808 23.352 ;
     RECT  7.693 24.384 7.808 26.232 ;
     RECT  7.333 27.648 7.808 27.672 ;
     RECT  7.369 30.144 7.808 32.472 ;
     RECT  5.699 39.024 7.808 39.048 ;
     RECT  5.997 42.288 7.808 42.312 ;
     RECT  5.249 45.024 7.808 45.048 ;
     RECT  7.045 46.08 7.808 46.104 ;
     RECT  7.621 48.384 7.808 48.792 ;
     RECT  7.189 49.872 7.808 51.864 ;
     RECT  7.189 53.04 7.808 53.064 ;
     RECT  7.381 54.192 7.808 54.6 ;
     RECT  6.589 55.632 7.808 55.992 ;
     RECT  7.808 1.728 7.912 69.132 ;
     RECT  7.297 0.096 8.051 0.6 ;
     RECT  7.912 1.728 8.104 68.862 ;
     RECT  8.104 18.24 8.129 26.28 ;
     RECT  8.104 48.768 8.129 51.816 ;
     RECT  8.104 34.176 8.243 34.392 ;
     RECT  8.129 25.2 8.332 26.28 ;
     RECT  8.104 40.56 8.339 40.584 ;
     RECT  8.104 38.16 8.345 39.24 ;
     RECT  8.129 48.912 8.345 51.816 ;
     RECT  8.104 7.728 8.381 15.48 ;
     RECT  8.104 42.672 8.381 44.952 ;
     RECT  8.104 54.192 8.417 54.216 ;
     RECT  8.104 30.144 8.525 33.144 ;
     RECT  8.345 50.64 8.579 51.816 ;
     RECT  8.104 46.032 8.597 47.352 ;
     RECT  8.129 18.24 8.633 23.928 ;
     RECT  8.525 31.728 8.633 32.472 ;
     RECT  8.633 19.584 8.668 23.928 ;
     RECT  8.345 48.912 8.669 49.032 ;
     RECT  8.051 0.096 8.723 0.552 ;
     RECT  8.381 42.672 8.741 44.472 ;
     RECT  8.381 13.248 8.777 15.48 ;
     RECT  8.579 50.688 8.849 51.816 ;
     RECT  8.104 17.088 8.885 17.112 ;
     RECT  8.741 42.672 8.921 42.792 ;
     RECT  8.668 19.584 8.956 22.968 ;
     RECT  8.777 13.248 9.029 13.944 ;
     RECT  8.332 25.2 9.029 26.232 ;
     RECT  8.921 42.768 9.065 42.792 ;
     RECT  8.849 50.688 9.065 50.856 ;
     RECT  8.104 55.776 9.097 55.992 ;
     RECT  9.029 25.2 9.101 25.224 ;
     RECT  8.381 7.728 9.137 11.736 ;
     RECT  8.104 57.552 9.173 57.576 ;
     RECT  8.777 15.456 9.277 15.48 ;
     RECT  8.956 21.648 9.281 22.968 ;
     RECT  8.525 30.144 9.313 30.168 ;
     RECT  9.137 7.728 9.457 9 ;
     RECT  9.029 26.208 9.461 26.232 ;
     RECT  9.457 7.584 9.493 9 ;
     RECT  8.741 43.872 9.565 44.472 ;
     RECT  9.565 43.872 9.637 44.712 ;
     RECT  8.104 1.728 9.673 5.928 ;
     RECT  8.723 0.096 9.709 0.12 ;
     RECT  9.673 1.152 9.709 5.928 ;
     RECT  8.669 49.008 9.713 49.032 ;
     RECT  9.097 54.048 9.713 54.072 ;
     RECT  8.345 39.024 9.853 39.048 ;
     RECT  8.956 19.584 9.893 19.992 ;
     RECT  9.853 38.928 9.893 39.048 ;
     RECT  8.597 46.512 10.001 47.352 ;
     RECT  9.097 55.248 10.069 55.992 ;
     RECT  9.709 0.096 10.105 5.928 ;
     RECT  9.493 7.056 10.105 9 ;
     RECT  9.029 13.488 10.109 13.944 ;
     RECT  9.137 10.608 10.177 11.736 ;
     RECT  8.633 18.24 10.177 18.264 ;
     RECT  10.177 10.032 10.213 11.736 ;
     RECT  9.637 43.872 10.217 45 ;
     RECT  9.065 50.832 10.253 50.856 ;
     RECT  9.277 15.456 10.285 15.768 ;
     RECT  10.177 18.24 10.285 19.416 ;
     RECT  9.637 41.232 10.289 41.256 ;
     RECT  9.893 38.928 10.309 38.952 ;
     RECT  9.281 22.704 10.321 22.968 ;
     RECT  10.109 13.824 10.325 13.944 ;
     RECT  10.268 37.2 10.355 37.224 ;
     RECT  10.069 55.008 10.429 55.992 ;
     RECT  10.033 57.504 10.429 57.528 ;
     RECT  9.281 21.648 10.46 21.672 ;
     RECT  10.321 22.704 10.46 23.976 ;
     RECT  10.357 34.752 10.505 34.776 ;
     RECT  10.213 10.032 10.609 11.784 ;
     RECT  10.7 49.728 10.717 49.752 ;
     RECT  10.46 21.648 10.748 23.976 ;
     RECT  10.609 10.032 10.781 11.928 ;
     RECT  10.217 44.448 10.787 45 ;
     RECT  10.717 49.728 10.787 50.28 ;
     RECT  10.781 9.984 10.789 11.928 ;
     RECT  10.787 44.448 10.819 44.52 ;
     RECT  9.313 29.76 10.825 30.168 ;
     RECT  10.748 21.648 10.835 24.312 ;
     RECT  10.717 28.464 10.837 28.488 ;
     RECT  10.825 29.76 10.837 30.312 ;
     RECT  10.789 9.984 10.861 12.168 ;
     RECT  10.837 28.464 10.883 30.312 ;
     RECT  10.883 30.288 10.909 30.312 ;
     RECT  10.105 0.096 10.933 9 ;
     RECT  10.861 9.984 10.933 12.312 ;
     RECT  10.285 18.144 10.933 19.416 ;
     RECT  10.933 0.096 10.969 12.312 ;
     RECT  10.883 29.232 10.973 29.256 ;
     RECT  10.753 33.6 10.973 34.248 ;
     RECT  10.969 0.096 11.009 12.36 ;
     RECT  10.835 21.648 11.009 22.488 ;
     RECT  10.309 38.208 11.041 38.952 ;
     RECT  10.819 44.448 11.045 44.472 ;
     RECT  10.285 15.456 11.077 16.68 ;
     RECT  11.009 2.496 11.117 12.36 ;
     RECT  10.973 33.6 11.117 33.624 ;
     RECT  11.117 5.712 11.185 12.36 ;
     RECT  11.077 15.36 11.257 16.68 ;
     RECT  11.009 0.096 11.297 1.416 ;
     RECT  11.257 15.36 11.329 17.064 ;
     RECT  10.933 18.144 11.329 19.656 ;
     RECT  11.149 25.056 11.401 25.08 ;
     RECT  8.633 32.448 11.42 32.472 ;
     RECT  11.329 15.36 11.441 19.656 ;
     RECT  11.401 25.056 11.441 25.176 ;
     RECT  11.42 32.448 11.461 32.712 ;
     RECT  11.185 5.712 11.477 12.6 ;
     RECT  11.441 15.36 11.477 17.64 ;
     RECT  11.461 31.776 11.507 32.712 ;
     RECT  11.477 5.712 11.549 12.168 ;
     RECT  11.477 15.744 11.549 17.64 ;
     RECT  10.429 55.008 11.557 57.528 ;
     RECT  11.549 5.712 11.621 10.056 ;
     RECT  11.549 11.76 11.621 12.168 ;
     RECT  11.557 55.008 11.644 58.488 ;
     RECT  11.644 55.008 11.693 57.528 ;
     RECT  11.441 18.864 11.761 19.656 ;
     RECT  11.117 2.496 11.765 4.536 ;
     RECT  11.621 11.856 11.765 12.168 ;
     RECT  11.549 15.744 11.765 16.248 ;
     RECT  11.761 18.864 11.801 19.944 ;
     RECT  11.765 11.856 11.837 11.88 ;
     RECT  11.693 55.008 11.977 56.088 ;
     RECT  11.441 25.104 12.053 25.176 ;
     RECT  11.545 44.256 12.053 44.28 ;
     RECT  11.833 59.616 12.085 59.64 ;
     RECT  11.765 4.464 12.161 4.536 ;
     RECT  12.085 58.992 12.197 59.64 ;
     RECT  11.041 38.016 12.265 38.952 ;
     RECT  11.621 5.712 12.301 9.096 ;
     RECT  11.549 17.616 12.409 17.64 ;
     RECT  11.801 18.864 12.409 18.888 ;
     RECT  11.437 40.608 12.445 40.632 ;
     RECT  11.297 0.816 12.553 1.416 ;
     RECT  11.765 16.224 12.661 16.248 ;
     RECT  12.409 17.616 12.661 18.888 ;
     RECT  12.229 44.448 12.697 44.472 ;
     RECT  12.733 30.336 12.769 30.36 ;
     RECT  11.507 31.776 12.769 31.8 ;
     RECT  12.517 42.144 12.833 42.168 ;
     RECT  12.805 10.368 12.841 10.392 ;
     RECT  12.553 0.624 12.977 1.416 ;
     RECT  11.765 2.496 12.977 3.336 ;
     RECT  12.445 40.464 13.045 41.016 ;
     RECT  12.833 42.144 13.045 42.84 ;
     RECT  12.301 5.184 13.057 9.096 ;
     RECT  12.841 10.08 13.057 10.392 ;
     RECT  11.009 22.176 13.093 22.488 ;
     RECT  10.787 50.256 13.093 50.28 ;
     RECT  12.197 59.616 13.201 59.64 ;
     RECT  12.977 0.624 13.208 3.336 ;
     RECT  13.057 5.184 13.208 10.392 ;
     RECT  10.325 13.824 13.208 13.848 ;
     RECT  12.661 16.224 13.208 18.888 ;
     RECT  11.801 19.92 13.208 19.944 ;
     RECT  13.093 22.032 13.208 22.488 ;
     RECT  12.053 25.104 13.208 25.128 ;
     RECT  11.509 26.592 13.208 26.616 ;
     RECT  12.193 28.176 13.208 28.2 ;
     RECT  12.769 30.336 13.208 31.8 ;
     RECT  12.877 33.84 13.208 33.864 ;
     RECT  12.265 38.016 13.208 39.384 ;
     RECT  13.045 40.464 13.208 42.84 ;
     RECT  12.697 44.448 13.208 44.904 ;
     RECT  10.001 46.512 13.208 46.536 ;
     RECT  12.757 48.384 13.208 48.408 ;
     RECT  13.093 50.256 13.208 50.376 ;
     RECT  11.977 54.432 13.208 56.088 ;
     RECT  11.693 57.504 13.208 57.528 ;
     RECT  13.201 59.28 13.208 59.64 ;
     RECT  11.653 62.88 13.208 62.904 ;
     RECT  13.208 0.624 13.312 69.132 ;
     RECT  13.312 0.624 13.504 68.862 ;
     RECT  13.504 38.16 13.673 38.184 ;
     RECT  13.504 0.624 13.705 3.816 ;
     RECT  13.504 5.184 13.709 6.024 ;
     RECT  13.504 60.336 13.709 60.36 ;
     RECT  13.504 39.264 13.745 39.288 ;
     RECT  13.504 23.808 13.859 23.832 ;
     RECT  13.504 40.56 13.889 41.928 ;
     RECT  13.705 0.576 14.003 3.816 ;
     RECT  13.504 53.568 14.033 59.352 ;
     RECT  13.504 25.2 14.099 29.544 ;
     RECT  13.504 30.96 14.099 31.992 ;
     RECT  14.033 55.056 14.105 59.352 ;
     RECT  14.099 25.2 14.213 28.68 ;
     RECT  14.213 25.2 14.243 28.248 ;
     RECT  13.504 16.992 14.291 17.64 ;
     RECT  13.504 47.472 14.357 48.408 ;
     RECT  13.504 49.968 14.483 50.376 ;
     RECT  13.709 5.184 14.485 5.832 ;
     RECT  13.504 18.768 14.485 22.488 ;
     RECT  14.291 16.992 14.531 17.4 ;
     RECT  14.485 18.624 14.579 22.488 ;
     RECT  13.504 15.024 14.645 15.048 ;
     RECT  13.504 44.88 14.645 45.816 ;
     RECT  14.033 53.568 14.713 53.592 ;
     RECT  14.684 8.688 14.721 8.712 ;
     RECT  14.533 63.6 14.749 63.624 ;
     RECT  14.721 8.208 14.771 8.712 ;
     RECT  14.105 55.056 14.771 56.424 ;
     RECT  13.504 66.192 14.821 66.216 ;
     RECT  14.483 50.304 14.857 50.376 ;
     RECT  14.485 4.8 14.861 5.832 ;
     RECT  14.821 66.048 14.867 66.216 ;
     RECT  14.861 4.8 14.88 4.824 ;
     RECT  14.857 50.304 14.893 50.76 ;
     RECT  14.531 17.04 14.897 17.4 ;
     RECT  14.105 57.84 14.965 59.352 ;
     RECT  14.713 53.52 14.968 53.592 ;
     RECT  14.749 63.6 15.068 63.864 ;
     RECT  14.893 50.304 15.073 50.856 ;
     RECT  14.965 57.84 15.145 60.456 ;
     RECT  15.068 11.952 15.155 11.976 ;
     RECT  15.068 63.6 15.155 64.008 ;
     RECT  14.243 25.632 15.181 28.248 ;
     RECT  15.181 25.632 15.212 28.392 ;
     RECT  14.003 0.624 15.217 3.816 ;
     RECT  14.968 53.472 15.217 53.592 ;
     RECT  14.579 21.648 15.289 22.488 ;
     RECT  13.889 41.376 15.293 41.928 ;
     RECT  15.217 0.624 15.301 4.584 ;
     RECT  13.504 13.68 15.325 13.848 ;
     RECT  15.212 25.584 15.325 28.392 ;
     RECT  15.073 50.304 15.361 51.24 ;
     RECT  15.217 52.512 15.361 53.592 ;
     RECT  15.301 0.096 15.395 4.584 ;
     RECT  15.037 62.448 15.401 62.472 ;
     RECT  14.867 66.048 15.401 66.072 ;
     RECT  15.361 50.304 15.433 53.592 ;
     RECT  14.771 8.208 15.437 8.232 ;
     RECT  15.325 25.584 15.473 28.488 ;
     RECT  14.929 34.704 15.477 34.728 ;
     RECT  15.461 33.12 15.48 33.144 ;
     RECT  15.356 30.576 15.5 30.6 ;
     RECT  14.099 31.776 15.5 31.992 ;
     RECT  15.325 13.44 15.509 13.848 ;
     RECT  15.477 34.704 15.539 34.92 ;
     RECT  15.5 30.576 15.541 31.992 ;
     RECT  15.48 33.12 15.541 33.336 ;
     RECT  14.897 17.088 15.545 17.4 ;
     RECT  14.785 24.48 15.577 24.504 ;
     RECT  15.473 25.584 15.577 27.384 ;
     RECT  15.289 15.36 15.613 15.816 ;
     RECT  15.145 57.744 15.685 60.456 ;
     RECT  15.685 57.744 15.689 60.84 ;
     RECT  15.577 24.48 15.793 27.384 ;
     RECT  15.289 21.648 15.833 22.824 ;
     RECT  15.541 30.288 15.833 33.336 ;
     RECT  15.833 30.288 15.865 32.856 ;
     RECT  15.689 57.744 15.875 59.304 ;
     RECT  14.579 18.624 15.905 20.28 ;
     RECT  15.905 18.624 15.937 18.792 ;
     RECT  14.645 44.88 15.937 44.904 ;
     RECT  15.865 46.272 15.937 46.296 ;
     RECT  15.865 30 15.941 32.856 ;
     RECT  15.793 24.096 16.021 27.384 ;
     RECT  16.021 23.952 16.045 27.384 ;
     RECT  15.293 41.856 16.045 41.928 ;
     RECT  16.045 23.808 16.067 27.384 ;
     RECT  15.833 22.032 16.076 22.824 ;
     RECT  16.067 23.808 16.076 24.168 ;
     RECT  15.433 50.304 16.085 54.168 ;
     RECT  15.473 28.368 16.165 28.488 ;
     RECT  15.941 30 16.165 32.28 ;
     RECT  15.613 15.36 16.189 15.864 ;
     RECT  15.901 62.544 16.189 62.568 ;
     RECT  15.155 63.84 16.189 64.008 ;
     RECT  15.539 34.896 16.193 34.92 ;
     RECT  16.165 28.368 16.229 32.28 ;
     RECT  16.229 28.8 16.252 29.256 ;
     RECT  14.861 5.808 16.261 5.832 ;
     RECT  14.357 48.384 16.261 48.408 ;
     RECT  15.875 57.888 16.265 59.304 ;
     RECT  16.189 62.544 16.309 64.008 ;
     RECT  14.76 64.992 16.309 65.016 ;
     RECT  16.076 22.032 16.337 24.168 ;
     RECT  16.067 25.68 16.337 27.384 ;
     RECT  16.189 40.512 16.403 40.536 ;
     RECT  15.689 60.384 16.405 60.84 ;
     RECT  16.309 62.544 16.405 65.016 ;
     RECT  16.229 30.24 16.409 32.28 ;
     RECT  16.085 50.304 16.409 53.016 ;
     RECT  16.261 10.032 16.441 10.056 ;
     RECT  16.337 22.032 16.445 24.12 ;
     RECT  15.395 0.096 16.477 3.96 ;
     RECT  15.509 13.44 16.481 13.464 ;
     RECT  16.409 51.216 16.481 53.016 ;
     RECT  16.337 26.016 16.499 27.384 ;
     RECT  16.499 26.112 16.547 27.384 ;
     RECT  16.261 5.808 16.549 5.88 ;
     RECT  16.045 41.856 16.549 42.168 ;
     RECT  15.937 44.88 16.553 46.296 ;
     RECT  16.189 15.36 16.589 16.44 ;
     RECT  16.409 30.288 16.661 32.28 ;
     RECT  16.405 60.384 16.661 65.016 ;
     RECT  16.661 60.384 16.697 63.576 ;
     RECT  16.661 64.608 16.721 65.016 ;
     RECT  16.261 47.424 16.729 48.408 ;
     RECT  16.721 64.608 16.741 65.544 ;
     RECT  16.297 67.248 16.741 67.272 ;
     RECT  16.661 30.336 16.769 32.28 ;
     RECT  16.477 0.048 16.805 3.96 ;
     RECT  16.547 26.208 16.805 27.336 ;
     RECT  16.741 64.608 16.805 67.272 ;
     RECT  16.441 9.984 16.873 10.056 ;
     RECT  16.252 28.8 16.913 28.824 ;
     RECT  16.697 60.816 16.949 63.576 ;
     RECT  16.729 47.376 16.985 48.408 ;
     RECT  16.549 41.04 17.053 42.696 ;
     RECT  14.771 55.536 17.053 56.424 ;
     RECT  15.905 20.256 17.075 20.28 ;
     RECT  15.937 17.616 17.089 18.792 ;
     RECT  17.089 17.616 17.093 18.888 ;
     RECT  16.445 22.032 17.093 24.072 ;
     RECT  16.805 66.24 17.093 67.272 ;
     RECT  16.553 44.88 17.129 45.576 ;
     RECT  16.873 9.84 17.165 10.056 ;
     RECT  17.093 22.032 17.165 23.976 ;
     RECT  17.053 41.04 17.165 43.608 ;
     RECT  15.289 6.912 17.197 6.936 ;
     RECT  17.165 22.032 17.237 22.776 ;
     RECT  17.197 9.072 17.269 9.096 ;
     RECT  17.053 54.72 17.269 56.424 ;
     RECT  16.265 57.888 17.269 59.208 ;
     RECT  16.805 26.592 17.273 27.336 ;
     RECT  16.513 12.768 17.305 12.792 ;
     RECT  17.093 67.248 17.305 67.272 ;
     RECT  16.549 5.616 17.341 5.88 ;
     RECT  17.269 9.024 17.341 9.096 ;
     RECT  17.305 67.248 17.345 67.704 ;
     RECT  17.341 5.472 17.449 5.88 ;
     RECT  17.197 6.912 17.449 7.368 ;
     RECT  17.269 54.72 17.449 59.208 ;
     RECT  17.449 5.472 17.485 7.368 ;
     RECT  16.985 47.424 17.516 48.408 ;
     RECT  17.341 8.832 17.521 9.096 ;
     RECT  13.504 36.288 17.521 36.312 ;
     RECT  17.449 54.384 17.521 59.208 ;
     RECT  17.516 47.424 17.557 49.368 ;
     RECT  17.093 66.24 17.561 66.264 ;
     RECT  17.521 8.784 17.593 9.096 ;
     RECT  17.521 54.384 17.629 59.592 ;
     RECT  17.093 18.432 17.701 18.888 ;
     RECT  17.521 35.712 17.701 36.312 ;
     RECT  17.701 35.712 17.74 37.032 ;
     RECT  16.769 30.336 17.773 31.992 ;
     RECT  17.485 5.232 17.809 7.368 ;
     RECT  17.593 8.64 17.809 9.096 ;
     RECT  17.74 35.664 17.881 37.032 ;
     RECT  17.237 22.032 17.989 22.536 ;
     RECT  17.165 43.584 17.989 43.608 ;
     RECT  17.881 35.424 18.025 37.032 ;
     RECT  16.949 60.816 18.025 60.84 ;
     RECT  16.949 61.92 18.025 63.576 ;
     RECT  16.481 52.08 18.061 53.016 ;
     RECT  17.629 54.096 18.061 59.592 ;
     RECT  16.805 0.048 18.085 3.096 ;
     RECT  16.589 15.36 18.085 15.864 ;
     RECT  17.845 17.088 18.085 17.112 ;
     RECT  17.701 18.432 18.133 19.848 ;
     RECT  18.025 35.424 18.133 37.08 ;
     RECT  18.097 38.208 18.133 38.232 ;
     RECT  17.129 44.88 18.133 44.904 ;
     RECT  18.061 52.08 18.133 59.736 ;
     RECT  18.025 60.816 18.133 63.576 ;
     RECT  18.133 35.424 18.169 38.232 ;
     RECT  18.133 52.08 18.169 63.576 ;
     RECT  18.169 34.656 18.181 38.232 ;
     RECT  17.165 41.04 18.197 41.928 ;
     RECT  16.357 39.216 18.229 39.24 ;
     RECT  18.181 34.608 18.277 38.232 ;
     RECT  18.229 39.216 18.277 39.912 ;
     RECT  18.277 34.608 18.332 39.912 ;
     RECT  18.197 41.04 18.332 42.216 ;
     RECT  17.557 47.424 18.385 50.184 ;
     RECT  18.085 0.048 18.457 4.008 ;
     RECT  17.809 5.232 18.457 9.096 ;
     RECT  17.773 30.336 18.493 32.472 ;
     RECT  18.085 15.36 18.601 17.112 ;
     RECT  18.133 18.432 18.601 20.088 ;
     RECT  18.457 0.048 18.608 9.096 ;
     RECT  17.341 10.32 18.608 10.344 ;
     RECT  17.305 11.808 18.608 12.792 ;
     RECT  18.601 15.36 18.608 20.088 ;
     RECT  17.989 21.216 18.608 22.536 ;
     RECT  17.165 23.952 18.608 23.976 ;
     RECT  17.273 27.072 18.608 27.336 ;
     RECT  18.493 30.336 18.608 32.52 ;
     RECT  17.125 33.552 18.608 33.576 ;
     RECT  18.332 34.608 18.608 42.216 ;
     RECT  17.989 43.584 18.608 43.848 ;
     RECT  18.133 44.88 18.608 45.288 ;
     RECT  18.385 46.8 18.608 50.184 ;
     RECT  18.169 51.168 18.608 63.576 ;
     RECT  16.805 64.608 18.608 65.16 ;
     RECT  17.345 67.68 18.608 67.704 ;
     RECT  18.608 0.048 18.712 69.132 ;
     RECT  18.712 0.048 18.904 68.862 ;
     RECT  18.904 23.952 18.965 24.6 ;
     RECT  18.904 27.312 18.965 28.44 ;
     RECT  18.904 32.496 18.965 33.576 ;
     RECT  18.904 51.168 19.001 51.192 ;
     RECT  18.904 19.824 19.037 22.536 ;
     RECT  18.904 30.192 19.073 30.36 ;
     RECT  18.904 53.376 19.181 56.04 ;
     RECT  18.904 15.984 19.289 16.584 ;
     RECT  18.904 18.144 19.289 18.456 ;
     RECT  18.904 34.656 19.397 35.448 ;
     RECT  18.904 37.008 19.397 38.232 ;
     RECT  18.904 25.584 19.433 25.608 ;
     RECT  18.904 12.72 19.469 12.744 ;
     RECT  18.904 49.488 19.469 50.184 ;
     RECT  18.965 24.576 19.613 24.6 ;
     RECT  18.904 31.392 19.649 31.416 ;
     RECT  19.397 37.008 19.667 38.04 ;
     RECT  18.904 40.464 19.667 41.928 ;
     RECT  18.904 61.2 19.721 64.632 ;
     RECT  19.397 34.752 19.763 35.448 ;
     RECT  19.667 37.008 19.829 37.032 ;
     RECT  19.721 61.2 19.829 62.424 ;
     RECT  19.721 63.504 19.829 64.632 ;
     RECT  18.965 27.312 19.937 27.768 ;
     RECT  18.965 33.024 19.955 33.048 ;
     RECT  18.904 7.968 19.964 9.144 ;
     RECT  18.904 10.128 19.964 11.112 ;
     RECT  19.037 20.592 20.005 22.536 ;
     RECT  19.667 40.848 20.005 41.928 ;
     RECT  19.181 55.68 20.005 56.04 ;
     RECT  18.904 57.024 20.005 60.024 ;
     RECT  19.829 61.2 20.005 61.224 ;
     RECT  19.937 27.312 20.045 27.336 ;
     RECT  20.005 55.68 20.081 61.224 ;
     RECT  18.904 44.88 20.113 45.72 ;
     RECT  20.005 40.848 20.149 41.976 ;
     RECT  20.113 44.88 20.197 46.296 ;
     RECT  19.897 47.856 20.197 47.88 ;
     RECT  19.181 53.904 20.225 54.408 ;
     RECT  20.081 57.888 20.261 61.224 ;
     RECT  18.904 43.392 20.293 43.848 ;
     RECT  20.197 44.88 20.293 47.88 ;
     RECT  20.261 60.96 20.297 61.224 ;
     RECT  19.829 64.608 20.297 64.632 ;
     RECT  19.933 13.296 20.329 13.32 ;
     RECT  20.293 43.392 20.339 47.88 ;
     RECT  20.149 40.848 20.405 42.024 ;
     RECT  20.339 43.392 20.405 44.904 ;
     RECT  18.904 0.048 20.473 6.936 ;
     RECT  19.964 7.968 20.473 11.112 ;
     RECT  20.339 46.176 20.485 47.88 ;
     RECT  19.469 49.488 20.541 49.512 ;
     RECT  20.405 43.584 20.549 44.904 ;
     RECT  20.297 60.96 20.579 61.176 ;
     RECT  20.005 19.92 20.585 22.536 ;
     RECT  20.225 54.144 20.585 54.408 ;
     RECT  20.509 64.896 20.653 64.92 ;
     RECT  20.473 0.048 20.765 11.112 ;
     RECT  19.829 62.4 20.773 62.424 ;
     RECT  19.829 63.504 20.773 63.528 ;
     RECT  20.329 13.296 20.801 14.232 ;
     RECT  20.773 62.4 20.819 63.528 ;
     RECT  19.073 30.192 20.837 30.216 ;
     RECT  20.819 63.216 20.837 63.528 ;
     RECT  20.485 46.176 20.845 48.312 ;
     RECT  20.837 63.216 20.86 63.24 ;
     RECT  18.904 67.248 20.873 68.088 ;
     RECT  20.765 5.28 20.901 11.112 ;
     RECT  20.901 6.816 20.908 11.112 ;
     RECT  20.653 64.896 20.965 65.016 ;
     RECT  20.873 67.248 20.965 67.272 ;
     RECT  19.289 18.432 20.972 18.456 ;
     RECT  20.965 64.896 21.011 67.272 ;
     RECT  20.908 6.816 21.017 7.32 ;
     RECT  20.261 57.888 21.017 59.592 ;
     RECT  20.585 21.12 21.053 22.248 ;
     RECT  20.549 43.776 21.053 44.904 ;
     RECT  20.579 61.056 21.053 61.176 ;
     RECT  20.972 18 21.059 18.456 ;
     RECT  21.053 21.12 21.059 22.2 ;
     RECT  20.081 55.68 21.125 56.568 ;
     RECT  21.053 61.056 21.125 61.08 ;
     RECT  21.011 65.712 21.125 66.696 ;
     RECT  20.765 0.048 21.161 4.152 ;
     RECT  20.585 54.384 21.161 54.408 ;
     RECT  21.017 59.184 21.161 59.592 ;
     RECT  21.017 57.888 21.197 58.152 ;
     RECT  20.845 46.176 21.233 46.776 ;
     RECT  21.197 57.888 21.233 57.96 ;
     RECT  19.909 31.536 21.409 31.56 ;
     RECT  20.908 8.304 21.485 11.112 ;
     RECT  18.904 52.176 21.553 52.2 ;
     RECT  21.485 8.304 21.593 8.76 ;
     RECT  20.941 26.784 21.629 26.808 ;
     RECT  21.485 10.272 21.697 11.112 ;
     RECT  20.869 12.528 21.697 12.552 ;
     RECT  21.593 8.304 21.701 8.712 ;
     RECT  21.125 56.544 21.701 56.568 ;
     RECT  21.409 31.536 21.809 31.704 ;
     RECT  20.845 48.288 21.913 48.312 ;
     RECT  21.701 8.304 21.953 8.328 ;
     RECT  20.405 40.848 21.953 41.976 ;
     RECT  21.017 6.864 21.98 7.32 ;
     RECT  20.901 5.28 22.021 5.832 ;
     RECT  21.98 6.816 22.021 7.32 ;
     RECT  21.913 48.288 22.021 49.08 ;
     RECT  22.021 5.28 22.067 7.32 ;
     RECT  21.553 51.456 22.093 52.2 ;
     RECT  21.809 31.536 22.097 31.56 ;
     RECT  22.021 47.376 22.097 49.08 ;
     RECT  22.097 49.008 22.165 49.08 ;
     RECT  21.125 66.672 22.165 66.696 ;
     RECT  21.161 0.048 22.201 3.048 ;
     RECT  21.161 4.128 22.201 4.152 ;
     RECT  22.165 66.672 22.211 67.512 ;
     RECT  19.667 38.016 22.237 38.04 ;
     RECT  22.211 67.488 22.237 67.512 ;
     RECT  21.053 44.88 22.273 44.904 ;
     RECT  21.233 46.176 22.273 46.2 ;
     RECT  22.067 5.28 22.277 6.264 ;
     RECT  21.697 10.272 22.277 12.552 ;
     RECT  22.237 67.488 22.277 67.8 ;
     RECT  22.273 44.88 22.309 46.2 ;
     RECT  22.261 56.88 22.309 56.904 ;
     RECT  21.233 57.936 22.309 57.96 ;
     RECT  21.661 61.008 22.309 61.032 ;
     RECT  22.129 36.768 22.313 36.792 ;
     RECT  22.237 38.016 22.345 38.184 ;
     RECT  21.913 64.272 22.345 64.296 ;
     RECT  22.309 56.88 22.348 57.96 ;
     RECT  22.201 0.048 22.349 4.152 ;
     RECT  22.309 44.784 22.355 46.2 ;
     RECT  22.097 47.376 22.355 47.784 ;
     RECT  21.161 59.184 22.355 59.208 ;
     RECT  21.953 41.856 22.421 41.976 ;
     RECT  22.345 38.016 22.493 38.76 ;
     RECT  22.355 44.784 22.499 44.808 ;
     RECT  22.277 10.272 22.525 10.44 ;
     RECT  22.165 49.008 22.601 49.56 ;
     RECT  22.309 61.008 22.601 61.56 ;
     RECT  22.345 64.272 22.633 64.536 ;
     RECT  22.355 45.792 22.637 46.2 ;
     RECT  22.633 63.84 22.673 64.536 ;
     RECT  22.525 9.936 22.709 10.44 ;
     RECT  22.277 11.664 22.733 12.552 ;
     RECT  19.289 15.984 22.741 16.008 ;
     RECT  20.585 19.92 22.741 19.944 ;
     RECT  21.059 21.216 22.741 22.2 ;
     RECT  22.741 19.248 22.813 19.944 ;
     RECT  22.741 21.072 22.813 22.2 ;
     RECT  22.453 42.432 22.813 42.456 ;
     RECT  22.277 5.28 22.817 5.832 ;
     RECT  22.733 11.664 22.817 12.936 ;
     RECT  22.348 57.84 22.817 57.96 ;
     RECT  22.813 42.432 22.853 42.552 ;
     RECT  22.201 30.576 22.885 30.6 ;
     RECT  22.813 32.544 22.885 32.568 ;
     RECT  21.053 43.776 22.885 43.8 ;
     RECT  20.833 14.256 22.889 14.28 ;
     RECT  22.844 39.12 22.931 39.144 ;
     RECT  22.637 46.176 22.931 46.2 ;
     RECT  22.093 51.456 22.957 53.016 ;
     RECT  22.355 47.376 22.961 47.4 ;
     RECT  22.673 63.84 22.961 63.864 ;
     RECT  19.763 34.752 22.981 34.776 ;
     RECT  20.773 35.76 22.981 35.784 ;
     RECT  22.885 32.544 22.997 33.096 ;
     RECT  22.885 8.016 23.029 8.232 ;
     RECT  22.601 49.008 23.033 49.032 ;
     RECT  22.633 60.864 23.033 60.888 ;
     RECT  22.349 4.128 23.065 4.152 ;
     RECT  22.921 55.248 23.132 55.272 ;
     RECT  23.101 65.136 23.317 65.16 ;
     RECT  22.997 32.544 23.365 32.76 ;
     RECT  22.813 19.248 23.389 22.2 ;
     RECT  23.132 55.248 23.389 55.944 ;
     RECT  22.349 0.048 23.393 3.096 ;
     RECT  23.389 19.248 23.413 22.632 ;
     RECT  23.353 62.736 23.425 62.76 ;
     RECT  22.705 25.632 23.461 25.656 ;
     RECT  23.029 7.776 23.569 8.232 ;
     RECT  22.709 9.936 23.569 10.344 ;
     RECT  22.277 67.776 23.605 67.8 ;
     RECT  22.237 18.144 23.677 18.168 ;
     RECT  23.413 19.248 23.677 23.544 ;
     RECT  22.885 43.776 23.677 44.568 ;
     RECT  22.885 30.336 23.749 30.6 ;
     RECT  23.749 30.336 23.785 30.744 ;
     RECT  23.365 31.872 23.785 32.76 ;
     RECT  22.817 57.84 23.857 57.864 ;
     RECT  23.393 0.096 23.893 3.096 ;
     RECT  23.065 4.128 23.893 4.536 ;
     RECT  21.953 40.848 23.893 40.872 ;
     RECT  23.425 61.968 23.893 62.76 ;
     RECT  22.741 15.984 23.929 16.2 ;
     RECT  23.677 18.144 23.965 23.544 ;
     RECT  23.173 46.224 23.965 46.248 ;
     RECT  23.893 0.096 24.008 4.536 ;
     RECT  22.817 5.52 24.008 5.832 ;
     RECT  23.569 7.776 24.008 10.344 ;
     RECT  22.817 11.664 24.008 11.976 ;
     RECT  23.929 15.984 24.008 16.296 ;
     RECT  23.965 17.472 24.008 23.544 ;
     RECT  23.461 25.632 24.008 25.704 ;
     RECT  22.489 29.232 24.008 29.256 ;
     RECT  23.785 30.336 24.008 32.76 ;
     RECT  22.981 34.752 24.008 35.784 ;
     RECT  22.493 38.016 24.008 38.04 ;
     RECT  23.893 40.32 24.008 40.872 ;
     RECT  22.853 42.528 24.008 42.552 ;
     RECT  23.677 43.776 24.008 44.712 ;
     RECT  23.965 46.224 24.008 46.728 ;
     RECT  23.533 48.24 24.008 48.792 ;
     RECT  22.957 50.304 24.008 53.016 ;
     RECT  23.389 55.248 24.008 56.376 ;
     RECT  23.857 57.84 24.008 58.68 ;
     RECT  23.893 61.2 24.008 62.76 ;
     RECT  23.317 65.136 24.008 65.208 ;
     RECT  23.605 67.68 24.008 67.8 ;
     RECT  24.008 0.096 24.112 69.132 ;
     RECT  24.112 0.096 24.304 68.862 ;
     RECT  24.304 52.992 24.365 56.376 ;
     RECT  24.304 30.24 24.401 31.416 ;
     RECT  24.304 15.984 24.419 20.424 ;
     RECT  24.365 52.992 24.419 54.456 ;
     RECT  24.419 15.984 24.437 17.496 ;
     RECT  24.304 26.208 24.46 26.76 ;
     RECT  24.365 55.68 24.545 56.376 ;
     RECT  24.304 60.288 24.545 63.048 ;
     RECT  24.304 0.096 24.563 10.344 ;
     RECT  24.304 46.224 24.617 46.248 ;
     RECT  24.563 0.096 24.689 8.568 ;
     RECT  24.304 50.304 24.797 51.912 ;
     RECT  24.304 44.448 24.833 45.192 ;
     RECT  24.304 57.456 25.013 58.632 ;
     RECT  24.545 60.816 25.049 63.048 ;
     RECT  24.545 55.68 25.085 56.328 ;
     RECT  25.049 61.776 25.085 63.048 ;
     RECT  24.304 64.752 25.085 65.736 ;
     RECT  24.304 11.376 25.121 11.976 ;
     RECT  24.304 41.424 25.121 43.128 ;
     RECT  24.304 40.32 25.139 40.344 ;
     RECT  24.797 50.304 25.157 50.328 ;
     RECT  25.085 61.872 25.157 63.048 ;
     RECT  25.121 41.424 25.165 42.552 ;
     RECT  24.304 48.768 25.229 48.792 ;
     RECT  24.304 67.68 25.297 67.8 ;
     RECT  24.419 52.992 25.337 53.592 ;
     RECT  24.401 30.24 25.373 31.32 ;
     RECT  24.563 9.888 25.436 10.344 ;
     RECT  25.121 11.376 25.436 11.832 ;
     RECT  24.419 18.768 25.445 19.272 ;
     RECT  24.437 17.472 25.477 17.496 ;
     RECT  24.304 14.16 25.517 14.184 ;
     RECT  24.46 26.208 25.549 26.232 ;
     RECT  25.477 17.472 25.553 18.264 ;
     RECT  25.333 46.608 25.553 46.728 ;
     RECT  25.157 62.16 25.693 63.048 ;
     RECT  25.549 25.296 25.697 26.232 ;
     RECT  25.373 30.24 25.697 30.264 ;
     RECT  25.373 31.296 25.697 31.32 ;
     RECT  25.013 57.84 25.733 58.632 ;
     RECT  25.693 62.16 25.733 64.104 ;
     RECT  24.689 0.096 25.765 5.256 ;
     RECT  24.689 6.48 25.765 8.568 ;
     RECT  24.304 22.032 25.765 22.056 ;
     RECT  24.304 24.288 25.765 24.312 ;
     RECT  24.304 28.464 25.765 28.488 ;
     RECT  25.765 21.648 25.811 22.056 ;
     RECT  25.085 55.68 25.841 56.232 ;
     RECT  25.697 25.296 25.877 25.704 ;
     RECT  25.765 23.664 25.913 24.312 ;
     RECT  25.436 9.888 25.949 11.832 ;
     RECT  25.811 21.648 25.955 21.672 ;
     RECT  25.085 65.712 25.985 65.736 ;
     RECT  25.945 29.616 26.029 29.64 ;
     RECT  25.765 0.096 26.121 8.568 ;
     RECT  25.913 24.192 26.125 24.312 ;
     RECT  26.125 61.008 26.161 61.032 ;
     RECT  25.733 62.16 26.161 62.568 ;
     RECT  25.765 28.416 26.237 28.488 ;
     RECT  24.797 51.888 26.273 51.912 ;
     RECT  25.165 42.192 26.377 42.552 ;
     RECT  25.841 56.208 26.377 56.232 ;
     RECT  25.733 57.84 26.377 58.44 ;
     RECT  24.304 39.312 26.413 39.336 ;
     RECT  24.833 44.448 26.417 44.712 ;
     RECT  26.161 61.008 26.417 62.568 ;
     RECT  26.417 61.536 26.453 62.568 ;
     RECT  26.377 56.208 26.489 58.44 ;
     RECT  25.553 18.24 26.561 18.264 ;
     RECT  26.489 57.84 26.633 58.44 ;
     RECT  26.413 39.312 26.705 39.576 ;
     RECT  25.445 19.248 26.737 19.272 ;
     RECT  25.733 63.792 26.741 64.104 ;
     RECT  25.297 67.104 26.773 67.8 ;
     RECT  25.949 10.032 26.777 11.832 ;
     RECT  26.677 20.496 26.777 21.48 ;
     RECT  26.121 0.096 26.813 6.168 ;
     RECT  26.777 10.848 26.813 11.832 ;
     RECT  26.813 0.096 26.819 4.872 ;
     RECT  26.777 21.12 26.819 21.48 ;
     RECT  26.237 28.416 26.849 28.44 ;
     RECT  26.819 0.096 26.857 4.68 ;
     RECT  26.773 22.56 26.857 22.584 ;
     RECT  26.125 24.192 26.876 24.36 ;
     RECT  25.877 25.68 26.876 25.704 ;
     RECT  26.857 0.096 26.885 4.536 ;
     RECT  26.876 24.192 26.921 25.704 ;
     RECT  26.921 24.192 26.963 25.128 ;
     RECT  24.437 15.984 26.965 16.44 ;
     RECT  25.621 46.848 26.981 46.872 ;
     RECT  26.885 1.44 26.993 4.536 ;
     RECT  26.813 11.376 26.993 11.832 ;
     RECT  26.993 11.664 27.011 11.832 ;
     RECT  26.965 15.984 27.011 16.584 ;
     RECT  26.121 7.152 27.029 8.568 ;
     RECT  26.417 44.688 27.059 44.712 ;
     RECT  26.981 46.752 27.061 46.872 ;
     RECT  26.993 2.208 27.101 4.536 ;
     RECT  26.885 0.096 27.137 0.168 ;
     RECT  27.029 7.92 27.157 8.568 ;
     RECT  25.657 27.312 27.173 27.336 ;
     RECT  26.705 39.312 27.173 39.336 ;
     RECT  26.629 65.232 27.277 65.256 ;
     RECT  26.845 48.768 27.313 48.792 ;
     RECT  25.337 53.568 27.385 53.592 ;
     RECT  27.313 48.768 27.421 48.984 ;
     RECT  26.773 67.008 27.425 67.8 ;
     RECT  27.385 53.52 27.457 53.592 ;
     RECT  26.633 57.84 27.457 57.864 ;
     RECT  26.377 41.904 27.497 42.888 ;
     RECT  27.011 11.76 27.529 11.832 ;
     RECT  27.421 48.624 27.565 49.08 ;
     RECT  26.453 62.16 27.637 62.568 ;
     RECT  27.277 58.992 27.709 59.352 ;
     RECT  27.157 7.92 27.713 9.864 ;
     RECT  27.637 62.16 27.745 62.856 ;
     RECT  27.565 48.624 27.749 49.176 ;
     RECT  26.813 6.144 27.781 6.168 ;
     RECT  27.061 46.752 27.781 46.92 ;
     RECT  27.749 48.624 27.785 49.08 ;
     RECT  27.277 13.296 27.853 13.32 ;
     RECT  26.489 56.208 27.889 56.472 ;
     RECT  27.457 53.04 27.893 53.592 ;
     RECT  27.713 8.544 27.925 9.864 ;
     RECT  26.521 33.12 27.965 33.144 ;
     RECT  27.313 45.552 27.973 45.576 ;
     RECT  27.781 46.752 27.973 47.064 ;
     RECT  27.011 16.416 27.997 16.584 ;
     RECT  27.137 0.096 28.037 0.12 ;
     RECT  27.889 56.016 28.069 56.472 ;
     RECT  27.457 57.6 28.069 57.864 ;
     RECT  27.973 45.552 28.073 47.256 ;
     RECT  27.101 2.208 28.105 4.488 ;
     RECT  27.745 62.16 28.105 63.672 ;
     RECT  27.425 67.776 28.105 67.8 ;
     RECT  27.497 41.904 28.145 42.744 ;
     RECT  28.069 56.016 28.181 57.864 ;
     RECT  27.785 48.624 28.213 48.792 ;
     RECT  28.105 2.208 28.249 4.776 ;
     RECT  28.249 2.208 28.285 5.016 ;
     RECT  27.781 6.144 28.285 6.552 ;
     RECT  27.925 50.064 28.285 50.088 ;
     RECT  27.925 51.168 28.285 51.192 ;
     RECT  28.285 2.208 28.321 5.112 ;
     RECT  28.285 6.096 28.321 6.552 ;
     RECT  28.249 38.112 28.433 38.136 ;
     RECT  27.997 16.416 28.465 17.448 ;
     RECT  28.321 2.208 28.501 6.552 ;
     RECT  26.737 18.432 28.573 19.272 ;
     RECT  28.213 27.312 28.609 27.336 ;
     RECT  28.285 50.064 28.609 51.192 ;
     RECT  27.277 65.088 28.645 65.256 ;
     RECT  28.645 65.088 28.753 65.688 ;
     RECT  28.465 16.272 28.789 17.448 ;
     RECT  26.819 21.408 28.789 21.48 ;
     RECT  28.105 62.016 28.789 63.672 ;
     RECT  28.753 64.992 28.789 66.504 ;
     RECT  28.789 62.016 28.825 66.504 ;
     RECT  28.213 48.528 28.861 48.792 ;
     RECT  28.609 50.064 28.861 51.768 ;
     RECT  28.181 56.208 28.861 57.864 ;
     RECT  27.709 58.992 28.861 59.496 ;
     RECT  28.573 18.432 28.897 19.32 ;
     RECT  28.609 27.072 28.933 27.336 ;
     RECT  28.933 26.64 28.969 27.336 ;
     RECT  28.861 48.528 28.969 51.768 ;
     RECT  28.933 29.28 29.005 29.304 ;
     RECT  28.645 60.816 29.005 60.84 ;
     RECT  28.501 2.208 29.041 7.368 ;
     RECT  28.789 16.08 29.041 17.448 ;
     RECT  28.969 26.016 29.041 27.336 ;
     RECT  28.897 44.4 29.041 44.424 ;
     RECT  29.005 60.672 29.041 60.84 ;
     RECT  28.825 62.016 29.041 66.792 ;
     RECT  28.897 18.432 29.077 19.944 ;
     RECT  28.789 21.408 29.077 22.104 ;
     RECT  29.041 25.968 29.077 27.336 ;
     RECT  29.077 18.432 29.113 22.776 ;
     RECT  28.429 40.992 29.149 41.016 ;
     RECT  28.073 46.512 29.149 47.256 ;
     RECT  25.957 34.368 29.18 34.392 ;
     RECT  24.304 35.52 29.18 35.784 ;
     RECT  27.893 53.52 29.185 53.592 ;
     RECT  29.077 25.968 29.221 28.2 ;
     RECT  29.18 34.368 29.221 35.784 ;
     RECT  29.149 40.032 29.221 41.016 ;
     RECT  29.149 46.32 29.257 47.256 ;
     RECT  28.969 48.384 29.257 51.768 ;
     RECT  26.963 24.192 29.269 24.744 ;
     RECT  29.221 25.728 29.269 28.2 ;
     RECT  29.005 29.28 29.269 29.352 ;
     RECT  29.113 18.432 29.365 23.064 ;
     RECT  29.269 24.192 29.365 28.2 ;
     RECT  29.041 2.208 29.408 7.416 ;
     RECT  27.925 8.544 29.408 9.96 ;
     RECT  27.529 11.76 29.408 11.928 ;
     RECT  27.853 13.296 29.408 13.656 ;
     RECT  27.673 14.976 29.408 15 ;
     RECT  29.041 15.984 29.408 17.448 ;
     RECT  29.365 18.432 29.408 28.2 ;
     RECT  29.269 29.28 29.408 29.784 ;
     RECT  29.221 34.368 29.408 36.264 ;
     RECT  29.221 40.032 29.408 41.208 ;
     RECT  28.145 42.72 29.408 42.744 ;
     RECT  29.041 44.4 29.408 45 ;
     RECT  29.257 46.32 29.408 51.768 ;
     RECT  29.185 53.28 29.408 53.592 ;
     RECT  28.861 56.208 29.408 59.496 ;
     RECT  29.041 60.672 29.408 66.792 ;
     RECT  28.105 67.776 29.408 67.848 ;
     RECT  29.408 2.148 29.512 69.132 ;
     RECT  29.512 2.208 29.704 68.862 ;
     RECT  29.704 44.4 29.729 51.48 ;
     RECT  29.704 22.752 29.765 24.936 ;
     RECT  29.704 6.048 29.801 12.12 ;
     RECT  29.704 52.848 29.801 53.304 ;
     RECT  29.704 25.968 29.843 27.096 ;
     RECT  29.843 26.016 29.873 27.096 ;
     RECT  29.801 6.048 29.891 6.84 ;
     RECT  29.704 41.232 29.953 43.368 ;
     RECT  29.704 14.592 30.035 14.808 ;
     RECT  29.704 18.144 30.035 21.672 ;
     RECT  29.873 26.016 30.125 26.664 ;
     RECT  29.729 44.4 30.125 51.336 ;
     RECT  29.801 53.28 30.233 53.304 ;
     RECT  30.125 50.832 30.305 51.192 ;
     RECT  29.704 2.208 30.341 4.872 ;
     RECT  29.704 28.08 30.341 30.408 ;
     RECT  30.125 44.4 30.341 49.512 ;
     RECT  30.341 4.416 30.364 4.872 ;
     RECT  30.125 26.64 30.371 26.664 ;
     RECT  30.341 28.08 30.371 28.104 ;
     RECT  29.704 60.336 30.377 63.048 ;
     RECT  29.704 39.264 30.413 40.056 ;
     RECT  30.364 4.416 30.449 4.44 ;
     RECT  29.801 7.92 30.485 12.12 ;
     RECT  29.704 34.368 30.515 34.392 ;
     RECT  30.485 7.92 30.521 11.928 ;
     RECT  30.341 29.76 30.557 30.408 ;
     RECT  30.305 50.832 30.557 50.856 ;
     RECT  29.704 15.84 30.593 16.824 ;
     RECT  29.704 64.08 30.629 66.552 ;
     RECT  30.413 39.84 30.665 40.056 ;
     RECT  29.704 57.408 30.737 59.256 ;
     RECT  29.891 6.048 30.755 6.264 ;
     RECT  30.035 18.432 30.755 21.672 ;
     RECT  29.704 54.624 30.769 56.136 ;
     RECT  30.737 57.408 30.769 57.96 ;
     RECT  30.737 58.992 30.773 59.256 ;
     RECT  29.704 67.68 30.773 67.704 ;
     RECT  30.521 8.304 30.803 11.928 ;
     RECT  30.341 2.208 30.809 3.336 ;
     RECT  29.704 31.392 30.809 31.848 ;
     RECT  30.665 39.84 30.845 39.864 ;
     RECT  30.341 44.976 30.851 49.512 ;
     RECT  29.765 22.992 30.908 24.936 ;
     RECT  30.593 16.224 30.913 16.824 ;
     RECT  30.377 60.528 30.913 63.048 ;
     RECT  30.629 64.08 30.913 65.016 ;
     RECT  29.704 37.584 30.917 37.608 ;
     RECT  30.913 60.528 30.917 65.016 ;
     RECT  30.557 30.288 30.949 30.408 ;
     RECT  30.809 31.392 30.949 31.752 ;
     RECT  30.035 14.592 30.953 14.616 ;
     RECT  30.851 46.512 30.953 49.512 ;
     RECT  30.917 60.528 30.953 63.24 ;
     RECT  30.629 66.192 30.953 66.552 ;
     RECT  30.809 2.208 30.989 3.096 ;
     RECT  30.755 19.92 31.021 21.672 ;
     RECT  30.908 22.704 31.021 24.936 ;
     RECT  30.953 61.584 31.025 62.136 ;
     RECT  31.021 19.92 31.061 24.936 ;
     RECT  30.769 54.624 31.061 57.96 ;
     RECT  30.755 18.432 31.091 18.456 ;
     RECT  31.061 20.496 31.097 24.936 ;
     RECT  31.097 20.496 31.105 22.2 ;
     RECT  30.803 8.304 31.169 9.624 ;
     RECT  30.913 16.224 31.169 17.4 ;
     RECT  30.851 44.976 31.205 45.48 ;
     RECT  31.169 16.224 31.241 16.296 ;
     RECT  31.097 23.712 31.285 24.936 ;
     RECT  31.285 23.712 31.331 25.128 ;
     RECT  30.803 10.896 31.349 11.928 ;
     RECT  31.061 54.624 31.349 56.424 ;
     RECT  31.105 20.496 31.385 21.672 ;
     RECT  30.953 47.184 31.453 49.512 ;
     RECT  30.949 30.288 31.493 31.752 ;
     RECT  31.237 51.888 31.561 51.912 ;
     RECT  30.755 6.24 31.597 6.264 ;
     RECT  31.493 30.384 31.601 31.752 ;
     RECT  31.349 54.624 31.601 54.648 ;
     RECT  31.273 33.312 31.637 33.336 ;
     RECT  31.601 30.576 31.709 31.752 ;
     RECT  31.169 8.736 31.777 9.624 ;
     RECT  31.349 10.896 31.777 11.208 ;
     RECT  29.953 41.232 31.777 42.744 ;
     RECT  30.917 64.992 31.781 65.016 ;
     RECT  30.953 60.528 31.813 60.552 ;
     RECT  31.385 21.408 31.817 21.672 ;
     RECT  31.777 8.736 31.861 11.208 ;
     RECT  31.633 4.176 31.885 4.2 ;
     RECT  31.169 17.376 31.885 17.4 ;
     RECT  31.849 34.464 31.885 34.488 ;
     RECT  29.704 35.52 31.885 36.264 ;
     RECT  31.597 52.992 31.885 53.016 ;
     RECT  31.709 30.624 31.925 31.752 ;
     RECT  31.777 41.04 31.925 42.744 ;
     RECT  30.953 63.216 31.925 63.24 ;
     RECT  31.921 13.728 31.957 13.752 ;
     RECT  31.241 16.224 31.961 16.248 ;
     RECT  31.021 67.104 31.961 67.128 ;
     RECT  31.925 42.096 32.101 42.744 ;
     RECT  31.093 43.872 32.101 43.896 ;
     RECT  31.331 24.912 32.105 25.128 ;
     RECT  31.925 30.624 32.105 30.648 ;
     RECT  31.061 57.552 32.137 57.96 ;
     RECT  31.453 47.184 32.173 49.896 ;
     RECT  31.861 10.896 32.177 11.208 ;
     RECT  31.925 31.632 32.177 31.752 ;
     RECT  32.137 57.552 32.177 58.152 ;
     RECT  31.597 6.24 32.209 6.648 ;
     RECT  31.331 23.712 32.213 23.88 ;
     RECT  31.885 34.32 32.245 34.488 ;
     RECT  32.177 58.128 32.317 58.152 ;
     RECT  31.237 26.88 32.353 26.904 ;
     RECT  30.989 2.208 32.389 3.048 ;
     RECT  31.885 4.176 32.389 4.392 ;
     RECT  32.177 11.184 32.393 11.208 ;
     RECT  31.561 51.696 32.393 51.912 ;
     RECT  31.813 60.24 32.393 60.552 ;
     RECT  31.861 8.736 32.425 9.624 ;
     RECT  32.353 26.88 32.533 27.384 ;
     RECT  32.425 8.352 32.537 9.624 ;
     RECT  32.245 33.984 32.537 34.488 ;
     RECT  32.101 42.096 32.537 43.896 ;
     RECT  32.173 28.464 32.605 28.488 ;
     RECT  31.205 45.168 32.605 45.48 ;
     RECT  32.173 46.512 32.605 49.896 ;
     RECT  32.209 6.24 32.681 6.792 ;
     RECT  31.957 13.728 32.713 14.184 ;
     RECT  31.817 21.648 32.713 21.672 ;
     RECT  31.885 52.992 32.713 53.784 ;
     RECT  32.605 45.168 32.749 49.896 ;
     RECT  31.349 56.112 32.773 56.424 ;
     RECT  32.749 45.168 32.785 50.712 ;
     RECT  32.393 51.696 32.785 51.72 ;
     RECT  32.317 58.128 32.785 59.016 ;
     RECT  32.393 60.24 32.785 60.264 ;
     RECT  32.677 31.92 32.821 31.944 ;
     RECT  32.105 25.104 32.825 25.128 ;
     RECT  32.785 45.168 32.833 51.72 ;
     RECT  32.713 52.992 32.857 54.408 ;
     RECT  32.773 55.872 32.857 56.424 ;
     RECT  32.209 64.416 32.857 64.44 ;
     RECT  32.537 33.984 32.861 34.152 ;
     RECT  32.857 52.992 32.861 56.424 ;
     RECT  32.857 64.416 32.869 65.016 ;
     RECT  32.713 12.816 32.897 14.472 ;
     RECT  32.833 45.168 32.897 49.848 ;
     RECT  32.869 63.84 32.915 65.016 ;
     RECT  32.915 64.992 32.941 65.016 ;
     RECT  32.537 8.352 32.965 8.376 ;
     RECT  31.885 35.52 32.965 36.504 ;
     RECT  31.925 41.04 32.965 41.064 ;
     RECT  32.857 19.248 32.969 19.272 ;
     RECT  32.897 45.168 32.969 49.608 ;
     RECT  32.821 37.536 33.004 37.56 ;
     RECT  32.533 26.736 33.041 27.384 ;
     RECT  32.821 31.92 33.041 32.088 ;
     RECT  32.861 34.128 33.041 34.152 ;
     RECT  32.965 40.944 33.077 41.064 ;
     RECT  32.785 58.128 33.149 60.264 ;
     RECT  31.885 17.376 33.217 18.072 ;
     RECT  32.861 52.992 33.217 55.896 ;
     RECT  32.213 23.808 33.221 23.88 ;
     RECT  32.969 45.552 33.221 49.512 ;
     RECT  33.217 52.896 33.221 55.896 ;
     RECT  33.077 40.944 33.253 40.968 ;
     RECT  33.221 55.872 33.257 55.896 ;
     RECT  32.833 50.88 33.361 51.72 ;
     RECT  33.221 52.896 33.361 54.408 ;
     RECT  33.217 17.376 33.365 18.216 ;
     RECT  33.365 18.048 33.473 18.216 ;
     RECT  32.713 21.648 33.493 21.912 ;
     RECT  33.253 23.136 33.493 23.16 ;
     RECT  33.493 21.648 33.539 23.16 ;
     RECT  32.537 42.096 33.545 42.984 ;
     RECT  33.397 57.552 33.587 57.576 ;
     RECT  32.965 7.392 33.613 8.376 ;
     RECT  32.537 9.6 33.613 9.624 ;
     RECT  33.149 58.992 33.628 60.264 ;
     RECT  31.025 61.584 33.649 61.608 ;
     RECT  32.605 28.416 33.653 28.488 ;
     RECT  32.965 35.424 33.725 36.504 ;
     RECT  33.473 18.192 33.761 18.216 ;
     RECT  33.253 40.464 33.797 40.968 ;
     RECT  33.628 58.992 33.833 59.016 ;
     RECT  32.681 6.24 33.877 6.264 ;
     RECT  33.613 7.392 33.877 9.624 ;
     RECT  32.897 13.632 34.009 14.472 ;
     RECT  32.605 16.08 34.009 16.104 ;
     RECT  33.545 42.816 34.009 42.984 ;
     RECT  33.325 10.8 34.045 10.824 ;
     RECT  32.929 12.096 34.045 12.12 ;
     RECT  33.877 6.24 34.081 9.624 ;
     RECT  33.541 20.64 34.081 20.664 ;
     RECT  33.685 67.824 34.153 67.848 ;
     RECT  34.045 10.8 34.189 12.12 ;
     RECT  34.009 13.632 34.189 16.104 ;
     RECT  32.915 63.84 34.225 63.864 ;
     RECT  33.041 27.36 34.261 27.384 ;
     RECT  33.653 28.416 34.261 28.44 ;
     RECT  33.361 50.88 34.268 54.408 ;
     RECT  33.221 45.552 34.369 49.32 ;
     RECT  33.649 61.584 34.405 61.704 ;
     RECT  34.225 63.792 34.441 63.864 ;
     RECT  34.009 42.816 34.513 43.368 ;
     RECT  34.369 44.736 34.513 49.32 ;
     RECT  33.628 60.096 34.549 60.264 ;
     RECT  34.405 61.584 34.549 61.896 ;
     RECT  32.533 39.216 34.657 39.24 ;
     RECT  34.081 20.64 34.693 20.952 ;
     RECT  34.513 42.816 34.693 49.32 ;
     RECT  34.268 50.448 34.693 54.408 ;
     RECT  34.729 25.824 34.765 25.848 ;
     RECT  32.389 2.208 34.801 4.392 ;
     RECT  34.693 42.816 34.801 54.408 ;
     RECT  34.801 2.208 34.808 4.536 ;
     RECT  34.081 6.192 34.808 9.624 ;
     RECT  34.189 10.8 34.808 16.104 ;
     RECT  34.693 19.872 34.808 20.952 ;
     RECT  33.539 22.224 34.808 23.16 ;
     RECT  34.765 25.728 34.808 25.848 ;
     RECT  34.261 27.36 34.808 28.44 ;
     RECT  34.009 30.816 34.808 30.84 ;
     RECT  34.765 33.36 34.808 33.384 ;
     RECT  33.725 35.52 34.808 36.504 ;
     RECT  33.973 37.872 34.808 37.896 ;
     RECT  34.657 39.216 34.808 39.528 ;
     RECT  33.797 40.944 34.808 40.968 ;
     RECT  34.801 42.72 34.808 54.408 ;
     RECT  34.369 57.024 34.808 57.048 ;
     RECT  34.549 60.096 34.808 61.896 ;
     RECT  34.441 63.36 34.808 63.864 ;
     RECT  34.153 67.152 34.808 67.848 ;
     RECT  34.808 2.148 34.912 69.132 ;
     RECT  34.912 2.256 35.104 68.862 ;
     RECT  35.104 51.216 35.165 51.72 ;
     RECT  35.104 19.872 35.237 19.944 ;
     RECT  35.104 27.696 35.273 27.72 ;
     RECT  35.104 37.296 35.273 37.896 ;
     RECT  35.237 19.872 35.309 19.896 ;
     RECT  35.104 67.152 35.345 68.376 ;
     RECT  35.104 3.936 35.417 4.536 ;
     RECT  35.104 5.712 35.417 5.736 ;
     RECT  35.104 12.048 35.417 14.184 ;
     RECT  35.104 9.36 35.489 10.296 ;
     RECT  35.104 43.344 35.489 44.472 ;
     RECT  35.104 60.096 35.489 60.12 ;
     RECT  35.104 52.752 35.525 53.016 ;
     RECT  35.489 43.92 35.561 44.472 ;
     RECT  35.417 13.824 35.597 14.184 ;
     RECT  35.104 25.2 35.597 25.752 ;
     RECT  35.104 30.72 35.597 30.744 ;
     RECT  35.104 17.04 35.705 17.064 ;
     RECT  35.104 39.504 35.741 39.528 ;
     RECT  35.525 52.752 35.741 52.968 ;
     RECT  35.741 52.752 35.813 52.92 ;
     RECT  35.104 2.256 35.821 2.904 ;
     RECT  35.104 45.792 35.849 49.8 ;
     RECT  35.104 7.584 35.891 7.608 ;
     RECT  35.417 3.936 35.932 3.96 ;
     RECT  35.345 67.152 35.957 67.176 ;
     RECT  35.104 35.76 35.993 35.88 ;
     RECT  35.104 18.192 36.065 18.84 ;
     RECT  35.849 46.128 36.085 49.8 ;
     RECT  35.165 51.312 36.131 51.72 ;
     RECT  36.085 46.128 36.172 50.04 ;
     RECT  36.131 51.696 36.205 51.72 ;
     RECT  35.813 52.752 36.205 52.872 ;
     RECT  35.273 37.296 36.241 37.32 ;
     RECT  35.104 22.992 36.245 23.016 ;
     RECT  36.172 46.128 36.245 49.32 ;
     RECT  35.104 61.344 36.313 61.416 ;
     RECT  35.104 42.144 36.317 42.168 ;
     RECT  36.065 18.816 36.353 18.84 ;
     RECT  36.205 51.696 36.353 52.872 ;
     RECT  35.417 12.048 36.36 12.168 ;
     RECT  35.597 13.824 36.385 14.088 ;
     RECT  35.104 55.2 36.385 55.224 ;
     RECT  36.385 13.2 36.469 14.088 ;
     RECT  35.597 25.2 36.493 25.224 ;
     RECT  36.313 61.344 36.641 61.512 ;
     RECT  36.277 5.376 36.673 5.4 ;
     RECT  35.104 31.776 36.677 31.8 ;
     RECT  35.104 56.736 36.745 56.76 ;
     RECT  36.745 56.304 36.817 57.048 ;
     RECT  35.104 63.792 36.817 63.816 ;
     RECT  36.385 54.72 36.853 55.224 ;
     RECT  36.817 56.304 36.853 57.144 ;
     RECT  35.345 68.352 36.853 68.376 ;
     RECT  36.493 25.152 36.857 25.224 ;
     RECT  36.853 67.824 36.893 68.376 ;
     RECT  36.673 5.376 36.925 5.928 ;
     RECT  35.489 10.272 36.949 10.296 ;
     RECT  36.36 11.712 36.949 12.168 ;
     RECT  36.641 61.392 36.961 61.512 ;
     RECT  35.104 62.736 36.961 62.76 ;
     RECT  36.853 54.72 36.965 57.144 ;
     RECT  36.817 63.792 36.965 64.728 ;
     RECT  36.565 8.688 37.001 8.712 ;
     RECT  36.353 51.696 37.001 52.488 ;
     RECT  36.965 63.792 37.001 63.912 ;
     RECT  35.993 35.856 37.033 35.88 ;
     RECT  36.925 5.04 37.069 5.928 ;
     RECT  36.925 7.392 37.069 7.416 ;
     RECT  35.821 2.256 37.073 2.856 ;
     RECT  37.033 35.76 37.073 35.88 ;
     RECT  37.069 5.04 37.105 6.072 ;
     RECT  37.069 7.392 37.105 7.896 ;
     RECT  36.245 46.128 37.109 46.968 ;
     RECT  36.965 55.488 37.109 56.76 ;
     RECT  35.104 32.976 37.177 33.048 ;
     RECT  35.104 58.416 37.177 58.44 ;
     RECT  37.109 55.488 37.181 55.512 ;
     RECT  36.857 25.152 37.217 25.176 ;
     RECT  37.109 46.944 37.237 46.968 ;
     RECT  36.245 48.24 37.237 49.32 ;
     RECT  37.237 46.944 37.283 49.32 ;
     RECT  36.241 37.296 37.285 37.512 ;
     RECT  37.283 47.856 37.285 49.32 ;
     RECT  37.285 47.856 37.501 50.04 ;
     RECT  37.001 51.696 37.501 51.768 ;
     RECT  37.177 57.84 37.537 58.44 ;
     RECT  36.949 10.272 37.541 12.168 ;
     RECT  36.961 61.392 37.577 62.76 ;
     RECT  37.393 64.896 37.613 64.92 ;
     RECT  37.537 57.84 37.681 58.536 ;
     RECT  37.105 5.04 37.685 7.896 ;
     RECT  37.577 61.872 37.715 62.76 ;
     RECT  37.393 26.208 37.717 26.232 ;
     RECT  37.537 27.6 37.717 27.624 ;
     RECT  37.724 3.936 37.753 3.96 ;
     RECT  37.685 5.04 37.753 7.656 ;
     RECT  37.753 3.936 37.757 7.656 ;
     RECT  37.717 26.208 37.757 27.624 ;
     RECT  37.177 32.976 37.757 33.144 ;
     RECT  37.285 37.296 37.757 37.656 ;
     RECT  35.561 43.92 37.757 43.944 ;
     RECT  37.681 57.84 37.757 59.256 ;
     RECT  37.001 63.888 37.757 63.912 ;
     RECT  37.757 57.888 37.829 59.256 ;
     RECT  37.757 26.592 37.969 27.624 ;
     RECT  37.541 10.272 37.973 11.736 ;
     RECT  37.213 23.136 38.005 23.16 ;
     RECT  37.757 3.936 38.009 6.6 ;
     RECT  36.469 14.064 38.009 14.088 ;
     RECT  37.501 47.856 38.009 51.768 ;
     RECT  37.969 21.408 38.041 21.432 ;
     RECT  37.073 2.352 38.108 2.856 ;
     RECT  38.009 3.936 38.108 6.216 ;
     RECT  37.969 26.592 38.117 27.864 ;
     RECT  38.108 2.352 38.195 6.216 ;
     RECT  37.969 66.144 38.195 66.168 ;
     RECT  37.141 60.288 38.221 60.312 ;
     RECT  38.117 27.84 38.225 27.864 ;
     RECT  36.349 42.768 38.257 42.792 ;
     RECT  38.009 50.016 38.257 51.768 ;
     RECT  37.109 56.64 38.293 56.76 ;
     RECT  38.195 2.352 38.297 2.856 ;
     RECT  38.005 22.8 38.365 23.16 ;
     RECT  36.349 40.032 38.365 40.056 ;
     RECT  37.829 58.416 38.401 59.256 ;
     RECT  38.221 60.288 38.401 60.552 ;
     RECT  38.365 22.8 38.441 23.4 ;
     RECT  37.393 20.16 38.473 20.184 ;
     RECT  38.473 20.064 38.513 20.184 ;
     RECT  38.293 56.592 38.545 56.76 ;
     RECT  37.973 10.272 38.549 11.448 ;
     RECT  38.441 23.376 38.581 23.4 ;
     RECT  37.717 25.056 38.621 25.08 ;
     RECT  37.789 15.984 38.653 16.008 ;
     RECT  38.257 42.768 38.689 42.888 ;
     RECT  38.117 26.592 38.693 26.76 ;
     RECT  38.041 21.408 38.725 21.672 ;
     RECT  38.689 42.24 38.725 42.888 ;
     RECT  37.757 7.632 38.761 7.656 ;
     RECT  37.757 37.296 38.761 37.32 ;
     RECT  38.365 40.032 38.761 40.872 ;
     RECT  38.725 21.36 38.765 21.672 ;
     RECT  38.581 23.376 38.765 23.88 ;
     RECT  38.513 20.064 38.773 20.088 ;
     RECT  38.653 15.984 38.801 16.392 ;
     RECT  36.853 44.976 38.801 45 ;
     RECT  38.773 19.824 38.819 20.088 ;
     RECT  38.401 58.416 38.833 60.552 ;
     RECT  36.893 67.824 38.837 67.848 ;
     RECT  38.545 56.064 38.869 56.76 ;
     RECT  38.833 57.84 38.876 60.552 ;
     RECT  37.715 61.872 38.876 62.712 ;
     RECT  38.869 55.92 38.941 56.76 ;
     RECT  38.876 57.84 38.941 62.712 ;
     RECT  38.941 55.92 38.963 62.712 ;
     RECT  38.819 19.824 39.013 19.848 ;
     RECT  37.073 35.76 39.013 35.784 ;
     RECT  38.761 37.296 39.013 37.416 ;
     RECT  38.549 10.272 39.085 11.16 ;
     RECT  38.545 66.384 39.089 66.84 ;
     RECT  38.009 47.856 39.121 48.936 ;
     RECT  38.257 50.016 39.121 52.536 ;
     RECT  39.089 66.816 39.125 66.84 ;
     RECT  38.963 62.112 39.161 62.712 ;
     RECT  38.725 42.24 39.233 43.56 ;
     RECT  39.121 47.856 39.233 52.536 ;
     RECT  39.193 64.368 39.265 64.392 ;
     RECT  39.229 28.464 39.301 28.488 ;
     RECT  36.277 30 39.301 30.024 ;
     RECT  38.195 4.656 39.337 6.216 ;
     RECT  38.761 7.632 39.337 7.752 ;
     RECT  38.761 39.888 39.349 40.872 ;
     RECT  39.233 42.24 39.349 42.264 ;
     RECT  39.233 49.488 39.373 52.536 ;
     RECT  39.337 4.656 39.409 7.752 ;
     RECT  39.013 35.76 39.517 37.416 ;
     RECT  37.757 32.976 39.541 33 ;
     RECT  38.801 16.368 39.553 16.392 ;
     RECT  39.517 8.832 39.661 8.856 ;
     RECT  39.409 4.224 39.733 7.752 ;
     RECT  39.013 31.68 39.788 31.704 ;
     RECT  38.765 21.36 39.805 21.432 ;
     RECT  39.788 31.68 39.829 31.8 ;
     RECT  39.541 32.976 39.829 33.384 ;
     RECT  38.963 55.92 39.877 60.984 ;
     RECT  39.869 45.024 39.913 45.048 ;
     RECT  38.297 2.352 39.949 2.808 ;
     RECT  39.373 49.488 39.98 53.352 ;
     RECT  39.161 62.256 40.129 62.712 ;
     RECT  39.625 46.752 40.165 46.776 ;
     RECT  39.233 47.856 40.165 48.264 ;
     RECT  39.949 2.352 40.208 3.096 ;
     RECT  39.733 4.128 40.208 7.752 ;
     RECT  39.661 8.736 40.208 8.856 ;
     RECT  39.085 10.08 40.208 11.16 ;
     RECT  39.013 12.528 40.208 12.552 ;
     RECT  39.553 16.368 40.208 16.536 ;
     RECT  40.165 17.712 40.208 17.736 ;
     RECT  39.013 19.344 40.208 19.848 ;
     RECT  39.805 21.12 40.208 21.432 ;
     RECT  38.765 23.856 40.208 23.88 ;
     RECT  38.693 26.736 40.208 26.76 ;
     RECT  39.301 28.464 40.208 30.024 ;
     RECT  39.829 31.68 40.208 33.384 ;
     RECT  39.517 34.8 40.208 37.416 ;
     RECT  39.337 38.64 40.208 38.664 ;
     RECT  39.349 39.888 40.208 42.264 ;
     RECT  39.233 43.536 40.208 43.56 ;
     RECT  39.913 45.024 40.208 45.192 ;
     RECT  40.165 46.752 40.208 48.264 ;
     RECT  39.98 49.488 40.208 53.592 ;
     RECT  39.877 55.248 40.208 60.984 ;
     RECT  40.129 62.016 40.208 62.712 ;
     RECT  39.265 63.792 40.208 64.392 ;
     RECT  39.553 67.44 40.208 67.464 ;
     RECT  40.208 2.148 40.312 69.132 ;
     RECT  40.312 2.352 40.504 68.862 ;
     RECT  40.504 2.352 40.565 3.096 ;
     RECT  40.504 15.408 40.565 17.736 ;
     RECT  40.565 2.496 40.637 3.096 ;
     RECT  40.565 17.088 40.643 17.736 ;
     RECT  40.504 18.816 40.709 18.84 ;
     RECT  40.504 68.4 40.745 68.424 ;
     RECT  40.504 19.824 40.853 21.432 ;
     RECT  40.504 47.04 40.853 48.456 ;
     RECT  40.853 47.952 40.925 48.456 ;
     RECT  40.504 8.736 41.02 11.16 ;
     RECT  40.504 32.736 41.02 37.992 ;
     RECT  40.565 15.408 41.027 15.72 ;
     RECT  40.504 54.48 41.033 60.408 ;
     RECT  40.504 49.488 41.069 53.016 ;
     RECT  41.033 55.008 41.141 60.408 ;
     RECT  41.02 32.736 41.149 37.416 ;
     RECT  40.504 5.136 41.177 5.88 ;
     RECT  41.149 33.072 41.285 37.416 ;
     RECT  40.637 2.496 41.429 2.808 ;
     RECT  41.177 5.856 41.497 5.88 ;
     RECT  40.504 6.96 41.497 7.752 ;
     RECT  41.02 8.736 41.497 8.76 ;
     RECT  40.504 42 41.557 42.792 ;
     RECT  40.504 26.736 41.569 26.76 ;
     RECT  41.557 42 41.573 43.752 ;
     RECT  41.573 42.72 41.603 43.752 ;
     RECT  41.497 5.856 41.717 8.76 ;
     RECT  41.285 33.648 41.753 37.416 ;
     RECT  40.504 40.464 41.785 40.488 ;
     RECT  41.603 42.768 41.789 43.752 ;
     RECT  40.504 4.128 41.821 4.152 ;
     RECT  41.789 43.728 41.821 43.752 ;
     RECT  40.504 44.928 41.821 45.192 ;
     RECT  41.717 5.856 41.825 8.616 ;
     RECT  41.141 55.248 41.825 60.408 ;
     RECT  40.925 48.288 41.941 48.456 ;
     RECT  41.069 50.016 41.987 53.016 ;
     RECT  41.987 50.16 42.005 53.016 ;
     RECT  41.429 2.784 42.073 2.808 ;
     RECT  41.821 4.128 42.073 4.488 ;
     RECT  41.027 15.696 42.073 15.72 ;
     RECT  42.005 51.408 42.073 53.016 ;
     RECT  41.785 40.464 42.109 41.016 ;
     RECT  40.504 61.536 42.109 63.96 ;
     RECT  42.073 2.784 42.113 4.488 ;
     RECT  42.109 12.624 42.145 12.648 ;
     RECT  40.504 13.824 42.145 14.232 ;
     RECT  42.073 15.6 42.145 15.72 ;
     RECT  40.504 31.68 42.145 31.752 ;
     RECT  42.073 51.408 42.185 53.064 ;
     RECT  42.185 52.224 42.221 53.064 ;
     RECT  42.145 13.824 42.289 15.72 ;
     RECT  40.643 17.184 42.289 17.736 ;
     RECT  41.569 26.736 42.289 26.808 ;
     RECT  42.325 68.16 42.361 68.184 ;
     RECT  41.713 38.688 42.433 38.712 ;
     RECT  41.02 10.32 42.469 11.16 ;
     RECT  42.289 13.824 42.505 17.736 ;
     RECT  42.221 52.224 42.509 53.016 ;
     RECT  42.505 13.68 42.542 17.736 ;
     RECT  42.289 26.736 42.545 26.904 ;
     RECT  41.941 47.856 42.545 49.032 ;
     RECT  42.469 10.32 42.581 11.208 ;
     RECT  42.433 38.688 42.581 38.808 ;
     RECT  42.113 2.784 42.617 4.152 ;
     RECT  42.581 38.688 42.617 38.712 ;
     RECT  42.581 10.32 42.649 11.16 ;
     RECT  41.821 43.728 42.649 45.192 ;
     RECT  40.853 20.592 42.685 21.432 ;
     RECT  42.649 43.728 42.685 45.24 ;
     RECT  42.109 40.464 42.757 41.064 ;
     RECT  42.542 13.68 42.797 17.688 ;
     RECT  41.753 35.04 42.829 37.416 ;
     RECT  42.757 40.176 42.829 41.064 ;
     RECT  42.617 2.784 42.833 3.432 ;
     RECT  41.825 55.248 42.833 57.384 ;
     RECT  41.825 58.512 42.833 60.408 ;
     RECT  42.829 34.992 42.853 37.416 ;
     RECT  42.833 58.512 42.865 58.92 ;
     RECT  42.145 12.528 42.869 12.648 ;
     RECT  42.685 20.592 42.869 21.816 ;
     RECT  42.833 59.952 42.869 60.408 ;
     RECT  42.833 2.784 42.905 2.808 ;
     RECT  41.825 6.576 42.905 8.616 ;
     RECT  42.685 43.728 42.905 46.152 ;
     RECT  42.109 61.536 42.941 64.104 ;
     RECT  42.545 49.008 42.973 49.032 ;
     RECT  42.005 50.16 42.973 50.184 ;
     RECT  42.325 19.584 42.997 19.608 ;
     RECT  42.469 66.336 43.009 66.36 ;
     RECT  42.797 13.68 43.084 17.112 ;
     RECT  42.973 49.008 43.085 50.184 ;
     RECT  42.649 10.272 43.117 11.16 ;
     RECT  42.865 58.416 43.121 58.92 ;
     RECT  42.905 43.728 43.129 45 ;
     RECT  43.009 66 43.153 66.36 ;
     RECT  42.869 12.528 43.157 12.552 ;
     RECT  42.509 52.8 43.189 53.016 ;
     RECT  42.941 61.536 43.189 63.288 ;
     RECT  43.117 9.36 43.193 11.16 ;
     RECT  43.085 50.16 43.193 50.184 ;
     RECT  43.189 52.8 43.229 53.688 ;
     RECT  43.189 60.864 43.235 63.288 ;
     RECT  43.235 60.864 43.276 60.888 ;
     RECT  43.235 62.208 43.283 63.288 ;
     RECT  42.853 34.992 43.297 38.376 ;
     RECT  43.229 52.944 43.297 53.688 ;
     RECT  43.153 65.184 43.297 66.552 ;
     RECT  43.084 16.224 43.301 17.112 ;
     RECT  43.084 13.68 43.324 15.192 ;
     RECT  43.297 52.944 43.333 54.024 ;
     RECT  43.301 16.224 43.337 16.248 ;
     RECT  42.869 21.024 43.373 21.816 ;
     RECT  43.085 49.008 43.373 49.032 ;
     RECT  43.333 52.944 43.409 54.12 ;
     RECT  42.829 40.176 43.441 41.208 ;
     RECT  43.121 58.416 43.445 58.584 ;
     RECT  43.297 64.368 43.445 66.552 ;
     RECT  42.905 6.576 43.481 8.376 ;
     RECT  43.324 13.68 43.481 13.848 ;
     RECT  43.481 6.576 43.513 7.704 ;
     RECT  43.445 58.416 43.517 58.536 ;
     RECT  43.373 21.792 43.661 21.816 ;
     RECT  43.513 6.192 43.697 7.704 ;
     RECT  42.757 33.168 43.733 33.192 ;
     RECT  42.545 26.736 43.837 26.76 ;
     RECT  42.361 67.92 43.841 68.376 ;
     RECT  43.081 29.664 43.873 29.688 ;
     RECT  42.905 46.128 43.873 46.152 ;
     RECT  43.441 40.176 43.877 41.4 ;
     RECT  42.833 55.488 43.913 57.384 ;
     RECT  43.283 62.208 43.913 63 ;
     RECT  43.877 40.176 43.985 40.2 ;
     RECT  43.193 10.368 44.089 11.16 ;
     RECT  42.145 31.68 44.089 32.04 ;
     RECT  43.409 53.664 44.093 54.12 ;
     RECT  43.909 24.48 44.149 24.504 ;
     RECT  43.873 29.664 44.165 30.648 ;
     RECT  43.324 15.168 44.195 15.192 ;
     RECT  44.149 24.096 44.195 24.504 ;
     RECT  43.913 62.208 44.197 62.664 ;
     RECT  43.873 46.128 44.273 46.392 ;
     RECT  44.197 61.44 44.305 62.664 ;
     RECT  43.297 34.896 44.341 38.376 ;
     RECT  43.913 55.488 44.345 56.856 ;
     RECT  44.269 2.832 44.377 2.856 ;
     RECT  44.093 53.952 44.377 54.12 ;
     RECT  44.345 55.488 44.377 56.76 ;
     RECT  44.377 53.952 44.381 56.76 ;
     RECT  43.129 43.728 44.413 44.088 ;
     RECT  43.445 64.368 44.413 66.456 ;
     RECT  44.341 34.896 44.417 38.808 ;
     RECT  44.381 53.952 44.417 56.328 ;
     RECT  43.837 26.736 44.437 26.952 ;
     RECT  44.165 30.288 44.437 30.648 ;
     RECT  44.089 31.68 44.437 32.472 ;
     RECT  44.437 30.288 44.483 32.472 ;
     RECT  44.417 53.952 44.489 56.232 ;
     RECT  44.413 64.368 44.489 67.8 ;
     RECT  44.492 14.928 44.579 14.952 ;
     RECT  44.413 43.728 44.597 44.184 ;
     RECT  42.545 47.856 44.597 47.88 ;
     RECT  44.305 61.392 44.627 62.664 ;
     RECT  44.489 64.368 44.629 66.36 ;
     RECT  44.417 35.088 44.633 38.808 ;
     RECT  44.437 26.64 44.701 26.952 ;
     RECT  44.195 24.096 44.737 24.168 ;
     RECT  44.627 61.392 44.773 61.416 ;
     RECT  44.341 58.128 44.989 58.152 ;
     RECT  43.697 6.768 45.013 7.704 ;
     RECT  43.193 9.36 45.013 9.384 ;
     RECT  44.489 67.392 45.061 67.8 ;
     RECT  44.341 5.472 45.277 5.496 ;
     RECT  45.277 4.944 45.457 5.496 ;
     RECT  45.457 4.752 45.529 5.496 ;
     RECT  45.013 6.768 45.529 9.384 ;
     RECT  44.413 42.432 45.565 42.456 ;
     RECT  44.989 58.128 45.565 58.68 ;
     RECT  44.917 59.856 45.565 59.88 ;
     RECT  44.377 2.832 45.608 3.576 ;
     RECT  45.529 4.752 45.608 9.384 ;
     RECT  44.089 10.368 45.608 11.4 ;
     RECT  43.481 13.68 45.608 13.704 ;
     RECT  45.061 14.832 45.608 14.856 ;
     RECT  44.533 16.56 45.608 16.584 ;
     RECT  42.997 19.584 45.608 20.04 ;
     RECT  44.737 23.28 45.608 24.168 ;
     RECT  44.701 26.64 45.608 27.336 ;
     RECT  44.483 30.624 45.608 32.472 ;
     RECT  44.773 33.648 45.608 33.672 ;
     RECT  44.633 35.088 45.608 38.376 ;
     RECT  45.025 39.744 45.608 39.768 ;
     RECT  43.877 41.376 45.608 41.4 ;
     RECT  45.565 42.432 45.608 42.744 ;
     RECT  44.597 44.064 45.608 44.184 ;
     RECT  44.773 45.696 45.608 45.72 ;
     RECT  44.665 47.184 45.608 47.208 ;
     RECT  44.809 48.816 45.608 49.608 ;
     RECT  44.161 50.688 45.608 50.712 ;
     RECT  44.881 51.936 45.608 51.96 ;
     RECT  44.489 53.952 45.608 55.704 ;
     RECT  45.493 56.784 45.608 56.808 ;
     RECT  45.565 58.128 45.608 59.88 ;
     RECT  44.773 60.912 45.608 61.416 ;
     RECT  44.627 62.496 45.608 62.664 ;
     RECT  44.629 63.792 45.608 66.36 ;
     RECT  45.061 67.392 45.608 67.944 ;
     RECT  45.608 2.148 45.712 69.132 ;
     RECT  45.712 2.418 45.904 68.862 ;
     RECT  45.904 39.456 45.965 44.184 ;
     RECT  45.904 51.312 46.001 51.96 ;
     RECT  45.904 8.928 46.019 11.16 ;
     RECT  45.904 19.872 46.019 21.576 ;
     RECT  45.904 23.376 46.019 24.168 ;
     RECT  46.019 8.928 46.037 11.064 ;
     RECT  45.904 26.64 46.073 27.192 ;
     RECT  46.019 19.872 46.163 20.904 ;
     RECT  45.904 62.112 46.163 63.384 ;
     RECT  45.904 13.728 46.181 13.752 ;
     RECT  45.904 49.584 46.181 49.896 ;
     RECT  45.904 3.936 46.204 7.464 ;
     RECT  45.965 42.192 46.211 44.184 ;
     RECT  45.904 58.608 46.217 59.88 ;
     RECT  46.037 8.928 46.289 9.096 ;
     RECT  45.904 29.568 46.325 33.192 ;
     RECT  46.019 24.096 46.361 24.168 ;
     RECT  46.325 29.568 46.433 33.096 ;
     RECT  46.204 7.44 46.505 7.464 ;
     RECT  45.904 65.088 46.505 68.376 ;
     RECT  45.904 48.432 46.541 48.456 ;
     RECT  46.204 3.936 46.547 6.312 ;
     RECT  46.163 62.496 46.643 63.384 ;
     RECT  46.505 66.672 46.643 68.376 ;
     RECT  45.904 35.424 46.649 38.472 ;
     RECT  46.505 65.088 46.684 65.4 ;
     RECT  45.904 45.552 46.691 45.576 ;
     RECT  46.211 42.192 46.739 44.088 ;
     RECT  46.073 26.64 46.829 27.096 ;
     RECT  46.547 4.656 46.865 6.312 ;
     RECT  46.433 29.568 46.901 31.992 ;
     RECT  46.289 8.928 46.931 8.952 ;
     RECT  46.901 31.392 47.009 31.992 ;
     RECT  45.904 16.944 47.041 16.968 ;
     RECT  45.904 15.552 47.077 15.576 ;
     RECT  46.037 10.224 47.185 11.064 ;
     RECT  46.829 26.736 47.185 27.096 ;
     RECT  46.643 67.392 47.185 68.376 ;
     RECT  46.739 42.768 47.189 44.088 ;
     RECT  46.163 19.968 47.221 20.904 ;
     RECT  47.189 42.864 47.297 42.888 ;
     RECT  47.221 63.792 47.308 63.816 ;
     RECT  46.361 24.096 47.329 24.12 ;
     RECT  47.221 19.968 47.365 20.952 ;
     RECT  47.009 31.392 47.369 31.512 ;
     RECT  46.649 36.864 47.369 38.472 ;
     RECT  45.904 55.968 47.369 55.992 ;
     RECT  46.684 65.088 47.369 65.112 ;
     RECT  47.185 26.736 47.405 27.96 ;
     RECT  46.901 29.568 47.405 30.216 ;
     RECT  46.433 32.976 47.437 33.096 ;
     RECT  46.001 51.312 47.437 51.336 ;
     RECT  47.041 16.944 47.441 17.208 ;
     RECT  47.437 32.736 47.441 33.096 ;
     RECT  47.185 10.224 47.473 11.352 ;
     RECT  46.865 5.664 47.477 6.312 ;
     RECT  47.437 51.264 47.516 51.336 ;
     RECT  47.441 16.944 47.549 17.016 ;
     RECT  45.965 39.456 47.581 40.968 ;
     RECT  47.477 5.664 47.585 5.688 ;
     RECT  47.516 51.264 47.603 52.2 ;
     RECT  45.904 34.32 47.617 34.344 ;
     RECT  46.649 35.424 47.617 35.88 ;
     RECT  46.181 49.872 47.617 49.896 ;
     RECT  47.617 34.32 47.653 35.88 ;
     RECT  46.865 4.656 47.693 4.68 ;
     RECT  47.581 39.456 47.765 41.016 ;
     RECT  45.904 53.856 47.801 53.88 ;
     RECT  47.797 47.088 47.869 47.112 ;
     RECT  47.077 14.88 47.909 15.576 ;
     RECT  47.365 19.968 47.909 21 ;
     RECT  47.405 30.192 47.909 30.216 ;
     RECT  47.473 9.936 47.977 11.352 ;
     RECT  47.869 46.416 47.977 47.112 ;
     RECT  47.977 9.936 47.981 11.4 ;
     RECT  47.653 34.224 47.981 35.88 ;
     RECT  47.405 26.736 48.017 27.912 ;
     RECT  47.833 18.528 48.049 18.552 ;
     RECT  48.017 26.736 48.085 26.76 ;
     RECT  47.549 16.944 48.089 16.968 ;
     RECT  47.441 32.736 48.089 33 ;
     RECT  47.765 39.456 48.089 40.392 ;
     RECT  47.185 67.392 48.089 68.712 ;
     RECT  47.189 43.92 48.121 44.088 ;
     RECT  47.981 35.424 48.125 35.88 ;
     RECT  46.217 58.608 48.157 59.208 ;
     RECT  47.369 37.488 48.193 38.472 ;
     RECT  46.643 62.544 48.233 62.712 ;
     RECT  47.833 57.408 48.301 57.432 ;
     RECT  48.157 58.608 48.301 59.496 ;
     RECT  48.121 43.92 48.373 44.184 ;
     RECT  47.329 24.096 48.409 24.216 ;
     RECT  48.089 32.976 48.409 33 ;
     RECT  47.981 34.224 48.409 34.248 ;
     RECT  48.193 37.488 48.467 38.76 ;
     RECT  47.833 22.56 48.469 22.584 ;
     RECT  47.909 15.552 48.481 15.576 ;
     RECT  48.233 62.544 48.515 62.568 ;
     RECT  48.467 37.488 48.521 38.136 ;
     RECT  48.469 61.2 48.556 61.224 ;
     RECT  47.369 31.392 48.589 31.416 ;
     RECT  48.301 57.216 48.589 59.496 ;
     RECT  48.049 18.432 48.593 18.552 ;
     RECT  48.589 57.12 48.593 59.496 ;
     RECT  47.617 49.344 48.613 49.896 ;
     RECT  47.603 51.264 48.613 51.96 ;
     RECT  48.373 43.92 48.661 44.424 ;
     RECT  48.089 67.392 48.661 68.376 ;
     RECT  48.593 57.12 48.665 59.208 ;
     RECT  48.613 49.344 48.7 51.96 ;
     RECT  48.593 18.528 48.701 18.552 ;
     RECT  48.7 49.344 48.701 50.04 ;
     RECT  48.017 27.888 48.709 27.912 ;
     RECT  48.409 29.088 48.709 29.112 ;
     RECT  48.709 27.888 48.755 29.112 ;
     RECT  48.661 43.92 48.769 44.856 ;
     RECT  48.7 51.264 48.769 51.96 ;
     RECT  48.373 52.992 48.769 53.016 ;
     RECT  48.755 28.512 48.773 29.112 ;
     RECT  48.337 64.752 48.773 64.776 ;
     RECT  48.773 28.512 48.796 28.968 ;
     RECT  47.981 10.176 48.805 11.4 ;
     RECT  48.089 40.368 48.881 40.392 ;
     RECT  48.469 21.648 48.917 22.584 ;
     RECT  48.445 41.52 48.917 41.544 ;
     RECT  48.589 31.344 48.947 31.416 ;
     RECT  47.909 19.968 48.949 19.992 ;
     RECT  48.769 51.264 48.949 53.016 ;
     RECT  48.409 32.976 48.961 34.248 ;
     RECT  48.373 7.056 48.985 7.08 ;
     RECT  48.125 35.424 48.985 35.784 ;
     RECT  48.769 43.92 48.985 44.952 ;
     RECT  48.805 10.176 48.989 11.448 ;
     RECT  48.661 66.72 48.989 68.376 ;
     RECT  48.949 19.392 48.995 19.992 ;
     RECT  48.985 6.96 49.021 7.08 ;
     RECT  48.521 37.488 49.021 37.512 ;
     RECT  48.949 51.264 49.025 53.448 ;
     RECT  49.025 52.32 49.045 53.448 ;
     RECT  48.985 43.92 49.057 45.048 ;
     RECT  48.157 55.248 49.061 55.272 ;
     RECT  49.025 51.264 49.091 51.288 ;
     RECT  49.045 52.32 49.093 53.496 ;
     RECT  48.665 57.12 49.133 57.144 ;
     RECT  48.409 24.096 49.169 24.312 ;
     RECT  49.093 52.32 49.177 53.592 ;
     RECT  48.764 5.616 49.201 5.64 ;
     RECT  49.021 6.864 49.201 7.08 ;
     RECT  48.989 66.72 49.201 66.792 ;
     RECT  48.985 34.752 49.205 35.784 ;
     RECT  48.085 25.776 49.237 26.76 ;
     RECT  48.989 67.776 49.237 68.376 ;
     RECT  48.481 15.552 49.273 16.296 ;
     RECT  49.201 5.616 49.309 7.08 ;
     RECT  49.177 52.32 49.349 53.448 ;
     RECT  48.701 49.872 49.421 50.04 ;
     RECT  49.201 12.864 49.453 12.888 ;
     RECT  49.453 12.72 49.489 12.888 ;
     RECT  48.917 22.56 49.493 22.584 ;
     RECT  49.237 25.632 49.565 26.76 ;
     RECT  48.961 32.976 49.565 33.576 ;
     RECT  49.565 25.632 49.637 25.8 ;
     RECT  49.309 5.28 49.669 7.08 ;
     RECT  49.669 5.28 49.673 7.176 ;
     RECT  48.901 29.952 49.673 29.976 ;
     RECT  49.273 15.408 49.709 16.296 ;
     RECT  49.565 33.072 49.709 33.576 ;
     RECT  49.637 25.776 49.745 25.8 ;
     RECT  49.021 37.008 49.745 37.512 ;
     RECT  49.201 66.624 49.772 66.792 ;
     RECT  48.989 10.176 49.813 10.872 ;
     RECT  49.673 5.616 49.853 7.176 ;
     RECT  49.772 66.096 49.859 66.792 ;
     RECT  49.057 43.92 49.885 45.24 ;
     RECT  47.977 46.416 49.885 47.352 ;
     RECT  48.947 31.344 49.921 31.368 ;
     RECT  49.745 37.44 49.957 37.512 ;
     RECT  49.921 31.104 49.961 31.368 ;
     RECT  49.885 43.92 49.993 47.352 ;
     RECT  49.993 43.872 50.065 47.352 ;
     RECT  49.813 9.504 50.137 10.872 ;
     RECT  49.489 12.72 50.137 12.984 ;
     RECT  49.813 39.456 50.137 39.48 ;
     RECT  50.065 43.872 50.137 47.64 ;
     RECT  50.137 43.776 50.317 47.64 ;
     RECT  50.317 43.776 50.353 47.976 ;
     RECT  48.796 28.512 50.425 28.536 ;
     RECT  49.349 52.32 50.425 52.776 ;
     RECT  49.237 67.776 50.425 68.76 ;
     RECT  50.137 12.72 50.461 13.08 ;
     RECT  49.169 24.096 50.461 24.12 ;
     RECT  49.421 49.872 50.485 49.896 ;
     RECT  50.425 52.32 50.497 52.824 ;
     RECT  49.853 5.616 50.677 7.08 ;
     RECT  50.425 27.888 50.677 28.536 ;
     RECT  50.353 43.632 50.677 47.976 ;
     RECT  50.485 48.96 50.677 49.896 ;
     RECT  50.497 52.32 50.677 53.592 ;
     RECT  50.317 3.6 50.713 3.624 ;
     RECT  50.677 4.656 50.713 7.08 ;
     RECT  49.957 37.44 50.713 37.656 ;
     RECT  49.859 66.432 50.713 66.792 ;
     RECT  50.425 67.776 50.713 68.808 ;
     RECT  50.713 3.6 50.725 7.08 ;
     RECT  50.137 9.456 50.725 10.872 ;
     RECT  50.461 12.48 50.725 13.08 ;
     RECT  50.725 9.456 50.749 13.08 ;
     RECT  50.137 39.456 50.749 39.624 ;
     RECT  50.677 43.632 50.749 49.896 ;
     RECT  49.417 64.416 50.785 64.44 ;
     RECT  50.677 26.208 50.965 28.536 ;
     RECT  48.665 58.128 51.001 59.208 ;
     RECT  50.725 3.408 51.008 7.08 ;
     RECT  50.749 9.072 51.008 13.08 ;
     RECT  49.709 15.408 51.008 15.96 ;
     RECT  50.641 17.088 51.008 17.112 ;
     RECT  48.995 19.392 51.008 19.416 ;
     RECT  50.353 20.928 51.008 20.952 ;
     RECT  50.461 24.096 51.008 24.504 ;
     RECT  50.965 25.536 51.008 28.536 ;
     RECT  49.961 31.104 51.008 31.128 ;
     RECT  49.709 33.552 51.008 33.576 ;
     RECT  49.205 35.472 51.008 35.784 ;
     RECT  50.713 37.104 51.008 37.656 ;
     RECT  50.749 38.784 51.008 39.624 ;
     RECT  49.273 42.48 51.008 42.504 ;
     RECT  50.749 43.632 51.008 50.328 ;
     RECT  50.677 51.744 51.008 53.592 ;
     RECT  50.461 54.672 51.008 54.696 ;
     RECT  51.001 58.128 51.008 59.256 ;
     RECT  49.525 61.2 51.008 61.224 ;
     RECT  50.785 63.792 51.008 64.44 ;
     RECT  50.713 66.432 51.008 68.808 ;
     RECT  51.008 2.148 51.112 69.132 ;
     RECT  51.112 2.418 51.304 69 ;
     RECT  51.304 12.528 51.365 13.08 ;
     RECT  51.304 58.128 51.365 60.024 ;
     RECT  51.304 25.536 51.401 25.56 ;
     RECT  51.304 61.2 51.401 61.224 ;
     RECT  51.304 43.008 51.437 48.792 ;
     RECT  51.304 52.8 51.473 52.824 ;
     RECT  51.304 38.784 51.509 38.808 ;
     RECT  51.304 49.872 51.653 51.768 ;
     RECT  51.304 28.992 51.689 29.016 ;
     RECT  51.304 4.416 51.725 5.496 ;
     RECT  51.304 33.552 51.725 33.576 ;
     RECT  51.365 58.128 51.725 59.256 ;
     RECT  51.653 49.872 51.875 51.288 ;
     RECT  51.304 9.072 51.905 9.096 ;
     RECT  51.365 12.528 51.905 12.552 ;
     RECT  51.304 27.12 51.905 27.144 ;
     RECT  51.304 62.544 51.905 62.808 ;
     RECT  51.304 17.616 51.923 18.408 ;
     RECT  51.725 5.232 51.941 5.496 ;
     RECT  51.304 22.752 51.941 24.12 ;
     RECT  51.905 62.64 51.941 62.808 ;
     RECT  51.304 66.096 51.971 69 ;
     RECT  51.304 30.768 51.977 31.128 ;
     RECT  51.725 58.128 52.019 58.68 ;
     RECT  51.304 55.44 52.049 55.848 ;
     RECT  51.304 56.88 52.06 56.904 ;
     RECT  51.941 5.472 52.085 5.496 ;
     RECT  51.977 30.816 52.157 31.128 ;
     RECT  51.304 20.448 52.265 20.472 ;
     RECT  51.304 37.632 52.265 37.656 ;
     RECT  51.304 7.776 52.307 7.8 ;
     RECT  51.304 14.64 52.369 14.76 ;
     RECT  51.875 51.264 52.373 51.288 ;
     RECT  51.304 10.944 52.405 11.112 ;
     RECT  51.941 24.096 52.441 24.12 ;
     RECT  51.437 43.632 52.441 48.792 ;
     RECT  52.441 43.344 52.508 48.792 ;
     RECT  51.875 49.872 52.508 49.896 ;
     RECT  52.405 10.752 52.513 11.112 ;
     RECT  52.508 43.344 52.517 49.896 ;
     RECT  52.513 37.584 52.549 37.608 ;
     RECT  51.971 66.096 52.549 66.936 ;
     RECT  52.513 10.752 52.595 12.024 ;
     RECT  52.517 47.952 52.625 49.896 ;
     RECT  52.652 33.6 52.693 33.624 ;
     RECT  52.693 33.6 52.739 34.248 ;
     RECT  52.369 19.584 52.765 19.608 ;
     RECT  51.941 62.736 52.801 62.808 ;
     RECT  51.304 63.792 52.801 63.816 ;
     RECT  52.441 24.096 52.805 24.168 ;
     RECT  52.801 32.496 52.873 32.52 ;
     RECT  52.801 62.736 52.873 63.816 ;
     RECT  52.801 65.04 52.873 65.064 ;
     RECT  51.923 17.616 52.877 17.64 ;
     RECT  52.157 30.816 52.877 30.84 ;
     RECT  52.549 37.152 52.877 37.608 ;
     RECT  52.739 34.224 52.913 34.248 ;
     RECT  52.909 52.416 52.945 52.44 ;
     RECT  51.304 3.408 52.981 3.432 ;
     RECT  52.441 9.264 52.981 9.288 ;
     RECT  52.549 66.048 52.981 66.936 ;
     RECT  51.971 68.208 52.981 69 ;
     RECT  52.873 41.04 53.021 41.064 ;
     RECT  52.595 11.28 53.027 12.024 ;
     RECT  52.981 8.448 53.093 9.288 ;
     RECT  52.369 14.64 53.093 15.72 ;
     RECT  52.873 62.736 53.161 65.064 ;
     RECT  52.873 32.496 53.165 33.048 ;
     RECT  52.517 43.344 53.165 46.872 ;
     RECT  52.981 60.384 53.165 60.408 ;
     RECT  53.161 62.064 53.197 65.064 ;
     RECT  52.657 55.872 53.233 55.896 ;
     RECT  52.805 24.096 53.269 24.12 ;
     RECT  51.941 22.752 53.276 22.776 ;
     RECT  53.093 8.448 53.309 8.472 ;
     RECT  53.165 43.344 53.341 46.776 ;
     RECT  53.197 61.968 53.341 65.064 ;
     RECT  52.981 66.048 53.341 69 ;
     RECT  53.027 11.28 53.345 11.4 ;
     RECT  53.276 22.032 53.363 22.776 ;
     RECT  53.233 55.776 53.377 55.896 ;
     RECT  52.765 19.344 53.413 19.608 ;
     RECT  53.341 43.2 53.413 46.776 ;
     RECT  53.413 42.816 53.417 46.776 ;
     RECT  53.413 19.104 53.489 19.608 ;
     RECT  53.341 61.968 53.489 69 ;
     RECT  53.377 54.912 53.516 55.896 ;
     RECT  53.417 42.816 53.521 45.768 ;
     RECT  53.363 22.752 53.557 22.776 ;
     RECT  53.269 23.808 53.557 24.12 ;
     RECT  52.945 52.416 53.557 53.256 ;
     RECT  53.516 54.864 53.557 55.896 ;
     RECT  53.165 32.496 53.593 32.52 ;
     RECT  53.557 22.752 53.603 24.12 ;
     RECT  52.981 71.232 53.629 71.256 ;
     RECT  53.557 52.416 53.633 55.896 ;
     RECT  52.477 57.552 53.665 57.576 ;
     RECT  52.019 58.656 53.665 58.68 ;
     RECT  53.197 40.032 53.669 40.056 ;
     RECT  52.625 47.952 53.669 49.608 ;
     RECT  53.089 30.624 53.701 30.648 ;
     RECT  53.669 47.952 53.705 48.888 ;
     RECT  53.305 50.736 53.705 50.76 ;
     RECT  53.665 57.552 53.705 58.68 ;
     RECT  52.981 3.408 53.773 4.008 ;
     RECT  53.089 28.176 53.777 28.2 ;
     RECT  53.633 52.416 53.813 53.064 ;
     RECT  53.489 62.016 53.813 69 ;
     RECT  53.629 16.56 53.849 16.584 ;
     RECT  53.413 20.88 53.849 20.904 ;
     RECT  53.521 42.768 53.849 45.768 ;
     RECT  53.773 3.408 53.953 4.104 ;
     RECT  53.377 6.192 53.953 6.216 ;
     RECT  53.701 29.808 54.065 30.648 ;
     RECT  53.953 3.072 54.097 4.104 ;
     RECT  53.593 31.68 54.173 32.52 ;
     RECT  53.813 65.04 54.173 69 ;
     RECT  53.489 19.104 54.209 19.56 ;
     RECT  53.633 54.096 54.209 55.896 ;
     RECT  53.849 42.768 54.245 44.904 ;
     RECT  52.877 37.584 54.312 37.608 ;
     RECT  53.953 6.192 54.317 6.264 ;
     RECT  54.097 3.072 54.353 4.68 ;
     RECT  54.061 17.904 54.353 17.928 ;
     RECT  53.093 14.64 54.449 14.76 ;
     RECT  54.312 36.912 54.453 37.608 ;
     RECT  54.449 14.64 54.469 14.856 ;
     RECT  54.453 36.912 54.529 37.464 ;
     RECT  54.469 14.592 54.533 14.856 ;
     RECT  54.245 42.768 54.533 43.128 ;
     RECT  53.773 25.104 54.565 25.128 ;
     RECT  53.417 46.752 54.605 46.776 ;
     RECT  54.637 40.176 54.673 40.2 ;
     RECT  53.813 62.016 54.673 63.384 ;
     RECT  54.169 34.224 54.707 34.248 ;
     RECT  54.209 19.104 54.713 19.224 ;
     RECT  53.705 48.384 54.713 48.888 ;
     RECT  54.493 13.536 54.749 13.56 ;
     RECT  54.173 65.472 54.749 69 ;
     RECT  54.385 5.088 54.785 5.112 ;
     RECT  54.709 50.688 54.821 50.712 ;
     RECT  54.353 3.072 54.853 4.104 ;
     RECT  54.065 30.624 54.885 30.648 ;
     RECT  54.853 2.64 54.893 4.104 ;
     RECT  54.893 2.64 54.899 3.528 ;
     RECT  54.529 36.384 54.929 37.464 ;
     RECT  53.813 52.416 54.929 52.44 ;
     RECT  54.209 54.096 55.001 54.936 ;
     RECT  54.673 61.92 55.037 63.384 ;
     RECT  54.673 40.176 55.073 40.728 ;
     RECT  54.713 48.384 55.105 48.408 ;
     RECT  53.603 23.04 55.109 24.12 ;
     RECT  55.069 29.328 55.141 29.352 ;
     RECT  55.105 39.312 55.213 40.152 ;
     RECT  54.457 59.952 55.217 59.976 ;
     RECT  54.673 12.528 55.237 12.552 ;
     RECT  54.533 14.592 55.253 14.664 ;
     RECT  55.253 14.64 55.283 14.664 ;
     RECT  55.213 38.688 55.283 40.152 ;
     RECT  54.565 25.104 55.285 25.224 ;
     RECT  55.213 18.24 55.297 18.264 ;
     RECT  53.345 11.376 55.321 11.4 ;
     RECT  53.845 9.648 55.34 9.72 ;
     RECT  55.321 11.232 55.34 11.4 ;
     RECT  54.533 43.104 55.357 43.128 ;
     RECT  54.245 44.16 55.357 44.904 ;
     RECT  55.34 9.648 55.393 11.4 ;
     RECT  54.317 6.24 55.427 6.264 ;
     RECT  55.109 23.328 55.429 24.12 ;
     RECT  55.285 25.104 55.429 26.136 ;
     RECT  55.001 54.096 55.573 54.12 ;
     RECT  55.357 43.104 55.609 44.904 ;
     RECT  54.277 56.064 55.609 56.088 ;
     RECT  55.429 23.328 55.645 26.136 ;
     RECT  55.177 27.6 55.645 27.624 ;
     RECT  55.237 12.528 55.717 13.08 ;
     RECT  55.037 62.976 55.789 63.384 ;
     RECT  55.105 47.616 55.82 48.408 ;
     RECT  54.749 65.472 55.825 68.712 ;
     RECT  55.789 69.792 55.825 69.816 ;
     RECT  53.629 71.136 55.825 71.256 ;
     RECT  55.789 62.976 55.861 63.96 ;
     RECT  55.861 62.976 55.933 64.2 ;
     RECT  55.825 65.472 55.933 71.256 ;
     RECT  53.705 58.08 55.969 58.68 ;
     RECT  55.037 61.92 56.149 61.944 ;
     RECT  54.899 2.64 56.185 3.432 ;
     RECT  56.077 60.24 56.185 60.264 ;
     RECT  54.661 32.976 56.293 33 ;
     RECT  56.185 60.24 56.401 60.408 ;
     RECT  56.149 61.632 56.401 61.944 ;
     RECT  56.185 2.64 56.408 4.152 ;
     RECT  56.401 5.28 56.408 5.304 ;
     RECT  55.393 9.552 56.408 11.4 ;
     RECT  55.717 12.528 56.408 13.656 ;
     RECT  55.861 19.728 56.408 19.752 ;
     RECT  54.925 21.648 56.408 21.672 ;
     RECT  55.645 23.328 56.408 27.624 ;
     RECT  55.141 28.752 56.408 29.352 ;
     RECT  54.173 31.68 56.408 31.704 ;
     RECT  56.293 32.832 56.408 33 ;
     RECT  54.929 36.384 56.408 36.408 ;
     RECT  54.929 37.44 56.408 37.464 ;
     RECT  55.283 38.688 56.408 38.808 ;
     RECT  55.283 40.128 56.408 40.152 ;
     RECT  55.609 43.104 56.408 44.952 ;
     RECT  55.82 46.08 56.408 48.408 ;
     RECT  55.429 51.984 56.408 52.008 ;
     RECT  55.573 53.568 56.408 54.12 ;
     RECT  55.609 55.296 56.408 56.088 ;
     RECT  55.969 57.936 56.408 58.68 ;
     RECT  56.401 60.24 56.408 61.944 ;
     RECT  55.933 62.976 56.408 71.256 ;
     RECT  56.408 2.148 56.512 71.256 ;
     RECT  56.512 2.418 56.704 71.256 ;
     RECT  56.704 23.088 56.801 27.72 ;
     RECT  56.704 5.28 56.873 5.544 ;
     RECT  56.704 37.44 56.909 38.76 ;
     RECT  56.704 2.88 56.945 4.152 ;
     RECT  56.704 29.328 56.945 34.2 ;
     RECT  56.704 61.584 57.125 63.288 ;
     RECT  56.704 12.528 57.203 14.424 ;
     RECT  56.704 47.904 57.203 48.408 ;
     RECT  57.203 12.528 57.244 13.08 ;
     RECT  56.704 55.968 57.269 56.808 ;
     RECT  57.125 61.584 57.269 63.144 ;
     RECT  56.704 51.264 57.413 52.008 ;
     RECT  56.704 9.6 57.491 10.92 ;
     RECT  56.945 29.328 57.521 33.72 ;
     RECT  57.269 61.584 57.521 62.664 ;
     RECT  56.704 57.936 57.587 59.64 ;
     RECT  57.521 61.584 57.587 62.472 ;
     RECT  57.491 10.272 57.593 10.92 ;
     RECT  56.801 23.088 57.593 27.48 ;
     RECT  56.909 37.44 57.593 37.464 ;
     RECT  57.587 61.92 57.629 62.472 ;
     RECT  57.587 57.936 57.665 59.208 ;
     RECT  57.521 29.328 57.685 30.264 ;
     RECT  56.909 38.736 57.701 38.76 ;
     RECT  57.685 28.464 57.731 30.264 ;
     RECT  56.704 40.128 57.737 41.016 ;
     RECT  57.203 14.4 57.769 14.424 ;
     RECT  57.731 28.464 57.772 29.544 ;
     RECT  56.704 42.144 57.841 43.368 ;
     RECT  57.521 31.68 57.953 33.72 ;
     RECT  56.704 44.88 58.097 45 ;
     RECT  57.841 42.144 58.117 43.896 ;
     RECT  57.805 50.112 58.129 50.136 ;
     RECT  57.737 40.128 58.163 40.152 ;
     RECT  56.704 64.992 58.205 71.256 ;
     RECT  57.269 56.016 58.241 56.808 ;
     RECT  57.841 54.096 58.417 54.504 ;
     RECT  58.241 56.016 58.417 56.28 ;
     RECT  58.129 49.296 58.453 50.136 ;
     RECT  57.413 51.264 58.453 51.912 ;
     RECT  58.117 41.376 58.489 43.896 ;
     RECT  58.097 44.88 58.489 44.904 ;
     RECT  57.593 23.328 58.525 27.48 ;
     RECT  57.772 28.464 58.525 29.016 ;
     RECT  57.953 31.92 58.525 33.72 ;
     RECT  56.704 7.92 58.561 7.944 ;
     RECT  57.244 12.864 58.597 13.08 ;
     RECT  58.525 31.92 58.597 34.152 ;
     RECT  58.417 54 58.597 54.504 ;
     RECT  58.417 55.92 58.597 56.28 ;
     RECT  58.453 49.296 58.637 51.912 ;
     RECT  58.597 54 58.669 56.28 ;
     RECT  58.597 31.92 58.693 34.2 ;
     RECT  58.057 46.896 58.705 46.92 ;
     RECT  58.489 41.376 58.709 44.904 ;
     RECT  58.637 50.976 58.741 51.912 ;
     RECT  58.597 30.768 58.745 30.84 ;
     RECT  58.709 41.376 58.745 41.976 ;
     RECT  58.709 43.056 58.745 44.904 ;
     RECT  58.705 46.752 58.745 46.92 ;
     RECT  58.669 53.616 58.745 56.28 ;
     RECT  57.665 58.128 58.777 59.208 ;
     RECT  58.693 31.92 58.781 34.824 ;
     RECT  56.704 21.648 58.813 21.672 ;
     RECT  58.745 55.152 58.817 56.28 ;
     RECT  58.597 12.528 58.844 13.08 ;
     RECT  58.741 50.976 58.853 52.104 ;
     RECT  58.813 21.648 58.885 22.2 ;
     RECT  58.525 23.328 58.885 29.016 ;
     RECT  58.777 58.128 58.885 59.832 ;
     RECT  58.844 11.664 58.892 13.08 ;
     RECT  57.769 14.4 58.892 14.76 ;
     RECT  58.892 11.664 58.925 14.76 ;
     RECT  58.925 11.664 58.931 11.688 ;
     RECT  58.925 13.056 58.979 14.76 ;
     RECT  58.853 51.984 58.997 52.104 ;
     RECT  58.997 52.08 59.029 52.104 ;
     RECT  58.745 53.616 59.029 54.024 ;
     RECT  57.629 62.448 59.029 62.472 ;
     RECT  58.781 31.92 59.069 33.624 ;
     RECT  58.885 9.648 59.105 9.672 ;
     RECT  58.205 64.992 59.141 65.016 ;
     RECT  58.561 7.392 59.177 7.944 ;
     RECT  56.945 2.88 59.209 3.336 ;
     RECT  59.029 52.08 59.249 54.024 ;
     RECT  59.177 7.392 59.285 7.416 ;
     RECT  58.885 21.648 59.317 29.016 ;
     RECT  58.979 14.4 59.321 14.76 ;
     RECT  58.205 66.048 59.321 71.256 ;
     RECT  58.637 49.296 59.357 49.32 ;
     RECT  59.317 21.408 59.389 29.016 ;
     RECT  58.745 30.816 59.413 30.84 ;
     RECT  59.069 31.92 59.413 32.952 ;
     RECT  59.321 14.736 59.429 14.76 ;
     RECT  58.885 58.128 59.461 60.696 ;
     RECT  59.321 68.64 59.501 71.256 ;
     RECT  59.461 57.264 59.537 60.696 ;
     RECT  59.321 66.048 59.537 67.272 ;
     RECT  59.537 57.264 59.548 59.256 ;
     RECT  58.781 34.8 59.573 34.824 ;
     RECT  58.745 43.728 59.573 44.904 ;
     RECT  59.701 45.024 59.713 45.048 ;
     RECT  59.537 66.48 59.717 67.272 ;
     RECT  59.573 43.728 59.747 43.752 ;
     RECT  59.713 45.024 59.788 45.576 ;
     RECT  59.389 21.408 59.843 29.064 ;
     RECT  59.413 30.816 59.843 32.952 ;
     RECT  59.788 45.552 59.843 45.576 ;
     RECT  59.843 30.816 59.893 32.808 ;
     RECT  58.853 50.976 59.897 51 ;
     RECT  59.548 58.128 59.897 59.256 ;
     RECT  59.717 67.152 59.897 67.272 ;
     RECT  59.209 2.88 59.989 3.864 ;
     RECT  59.989 2.256 60.076 3.864 ;
     RECT  58.745 41.472 60.113 41.976 ;
     RECT  59.029 62.448 60.131 63.288 ;
     RECT  57.203 47.904 60.181 47.928 ;
     RECT  59.893 30.384 60.257 32.808 ;
     RECT  60.076 2.496 60.277 3.864 ;
     RECT  57.949 5.424 60.277 5.448 ;
     RECT  60.277 2.496 60.293 5.448 ;
     RECT  60.293 2.496 60.323 5.352 ;
     RECT  59.843 25.008 60.329 29.064 ;
     RECT  59.897 58.128 60.329 59.016 ;
     RECT  59.249 53.04 60.361 54.024 ;
     RECT  60.323 3.84 60.365 5.352 ;
     RECT  59.843 21.408 60.365 23.928 ;
     RECT  60.284 6.672 60.371 6.696 ;
     RECT  59.821 9.216 60.371 9.24 ;
     RECT  60.365 21.408 60.437 22.536 ;
     RECT  60.289 35.76 60.437 35.784 ;
     RECT  59.537 60.672 60.437 60.696 ;
     RECT  60.329 58.512 60.467 59.016 ;
     RECT  59.713 14.88 60.473 14.904 ;
     RECT  60.365 23.76 60.473 23.928 ;
     RECT  60.361 53.04 60.505 54.12 ;
     RECT  58.817 55.152 60.505 56.088 ;
     RECT  58.745 46.752 60.509 46.776 ;
     RECT  60.323 2.496 60.545 2.52 ;
     RECT  60.365 5.328 60.581 5.352 ;
     RECT  59.897 67.248 60.581 67.272 ;
     RECT  60.001 64.368 60.62 64.44 ;
     RECT  59.749 42.96 60.653 42.984 ;
     RECT  60.62 64.368 60.661 64.968 ;
     RECT  60.397 62.112 60.709 62.136 ;
     RECT  60.661 64.368 60.721 65.592 ;
     RECT  60.473 23.76 60.725 23.784 ;
     RECT  59.501 68.688 60.725 71.256 ;
     RECT  60.541 40.32 60.757 40.344 ;
     RECT  60.113 41.472 60.757 41.496 ;
     RECT  60.181 47.856 60.761 47.928 ;
     RECT  60.709 62.016 60.761 62.136 ;
     RECT  60.709 49.392 60.797 49.416 ;
     RECT  60.761 62.016 60.797 62.04 ;
     RECT  60.725 68.688 60.865 71.16 ;
     RECT  58.979 13.056 61.045 13.08 ;
     RECT  60.329 25.008 61.153 29.016 ;
     RECT  60.865 68.16 61.265 71.16 ;
     RECT  61.189 38.976 61.297 39 ;
     RECT  60.757 40.32 61.297 41.496 ;
     RECT  61.153 24.96 61.333 29.016 ;
     RECT  60.257 30.384 61.333 31.944 ;
     RECT  60.131 63.264 61.369 63.288 ;
     RECT  60.721 64.368 61.369 65.784 ;
     RECT  61.225 67.056 61.369 67.08 ;
     RECT  60.467 58.992 61.405 59.016 ;
     RECT  60.761 47.904 61.513 47.928 ;
     RECT  61.405 35.808 61.621 35.832 ;
     RECT  60.437 22.176 61.649 22.536 ;
     RECT  61.297 38.784 61.657 39 ;
     RECT  61.649 22.128 61.669 22.536 ;
     RECT  60.365 3.84 61.693 3.864 ;
     RECT  61.693 3.312 61.808 3.912 ;
     RECT  60.937 7.728 61.808 7.752 ;
     RECT  61.045 13.056 61.808 13.704 ;
     RECT  60.793 16.8 61.808 16.824 ;
     RECT  60.757 20.112 61.808 20.136 ;
     RECT  61.669 22.128 61.808 23.4 ;
     RECT  61.333 24.96 61.808 31.944 ;
     RECT  61.621 35.472 61.808 35.832 ;
     RECT  61.657 38.448 61.808 39.24 ;
     RECT  61.297 40.32 61.808 42.216 ;
     RECT  61.513 47.904 61.808 48.456 ;
     RECT  61.549 49.488 61.808 49.512 ;
     RECT  60.865 50.544 61.808 50.568 ;
     RECT  60.505 53.04 61.808 56.088 ;
     RECT  61.405 58.992 61.808 59.544 ;
     RECT  61.369 61.44 61.808 61.464 ;
     RECT  61.369 63.264 61.808 67.08 ;
     RECT  61.265 68.16 61.808 70.92 ;
     RECT  61.808 2.148 61.912 70.92 ;
     RECT  61.912 2.418 62.104 70.92 ;
     RECT  62.104 24.96 62.165 28.44 ;
     RECT  62.104 58.656 62.201 61.752 ;
     RECT  62.104 66.768 62.201 67.32 ;
     RECT  62.104 3.312 62.243 4.92 ;
     RECT  62.104 6.816 62.243 9.096 ;
     RECT  62.104 13.056 62.243 14.904 ;
     RECT  62.104 54.144 62.243 55.272 ;
     RECT  62.201 59.28 62.243 61.752 ;
     RECT  62.104 22.752 62.273 23.976 ;
     RECT  62.104 48.096 62.273 48.456 ;
     RECT  62.201 66.864 62.273 67.32 ;
     RECT  62.165 27.168 62.309 28.44 ;
     RECT  62.104 68.976 62.333 70.92 ;
     RECT  62.104 33.552 62.345 34.344 ;
     RECT  62.104 35.472 62.345 35.832 ;
     RECT  62.104 10.224 62.387 10.344 ;
     RECT  62.104 37.104 62.417 37.128 ;
     RECT  62.104 65.664 62.417 65.784 ;
     RECT  62.309 27.456 62.453 28.44 ;
     RECT  62.243 7.392 62.489 9.096 ;
     RECT  62.104 16.8 62.525 16.824 ;
     RECT  62.104 29.568 62.525 31.992 ;
     RECT  62.489 7.968 62.597 9.096 ;
     RECT  62.345 33.6 62.597 34.344 ;
     RECT  62.104 52.992 62.633 53.016 ;
     RECT  62.165 24.96 62.669 26.04 ;
     RECT  62.243 60.432 62.675 61.752 ;
     RECT  62.333 68.976 62.701 71.16 ;
     RECT  62.243 13.584 62.723 14.904 ;
     RECT  62.104 45.168 62.741 45.192 ;
     RECT  62.104 62.832 62.741 63.768 ;
     RECT  62.417 65.664 62.741 65.688 ;
     RECT  62.701 68.976 62.771 71.256 ;
     RECT  62.243 3.312 62.777 3.96 ;
     RECT  62.104 38.784 62.777 42.216 ;
     RECT  62.387 10.224 62.813 10.248 ;
     RECT  62.345 35.808 62.813 35.832 ;
     RECT  62.243 54.768 62.813 55.272 ;
     RECT  62.723 13.584 62.819 14.808 ;
     RECT  62.777 3.936 62.885 3.96 ;
     RECT  62.741 63.744 62.885 63.768 ;
     RECT  62.104 51.456 62.957 51.864 ;
     RECT  62.597 33.6 62.993 33.624 ;
     RECT  62.273 67.296 63.029 67.32 ;
     RECT  62.819 13.584 63.101 14.28 ;
     RECT  62.525 30.384 63.101 31.368 ;
     RECT  62.777 38.784 63.133 39 ;
     RECT  62.957 51.456 63.133 51.48 ;
     RECT  62.675 60.72 63.173 61.224 ;
     RECT  62.273 48.096 63.205 48.12 ;
     RECT  62.771 68.976 63.281 70.152 ;
     RECT  63.281 69.504 63.289 70.152 ;
     RECT  62.669 25.104 63.313 26.04 ;
     RECT  62.597 7.968 63.317 8.136 ;
     RECT  62.104 56.352 63.349 57.048 ;
     RECT  63.097 58.128 63.349 58.152 ;
     RECT  63.133 51.36 63.385 51.48 ;
     RECT  63.349 56.352 63.395 58.152 ;
     RECT  62.243 59.28 63.433 59.304 ;
     RECT  63.395 57.024 63.461 58.152 ;
     RECT  63.173 60.72 63.461 60.984 ;
     RECT  63.385 16.704 63.493 16.728 ;
     RECT  62.813 54.768 63.493 54.792 ;
     RECT  63.461 60.96 63.497 60.984 ;
     RECT  62.104 11.52 63.529 11.976 ;
     RECT  63.493 54.672 63.605 54.792 ;
     RECT  62.453 27.6 63.709 28.44 ;
     RECT  63.605 54.72 63.749 54.792 ;
     RECT  63.133 38.544 63.781 39 ;
     RECT  63.385 50.88 63.781 51.48 ;
     RECT  63.529 10.704 63.785 11.976 ;
     RECT  63.101 31.344 63.785 31.368 ;
     RECT  62.273 22.752 63.821 23.928 ;
     RECT  63.289 69.552 63.877 70.152 ;
     RECT  62.771 71.136 63.877 71.256 ;
     RECT  63.493 16.512 63.893 16.728 ;
     RECT  63.781 38.208 63.929 39 ;
     RECT  62.777 39.984 63.929 42.216 ;
     RECT  63.565 67.44 63.965 67.464 ;
     RECT  63.709 27.504 63.997 28.44 ;
     RECT  63.785 11.04 64.069 11.976 ;
     RECT  63.313 25.104 64.069 26.232 ;
     RECT  63.997 27.504 64.069 28.536 ;
     RECT  63.101 13.824 64.109 14.28 ;
     RECT  64.069 11.04 64.115 12.024 ;
     RECT  64.069 25.104 64.115 29.064 ;
     RECT  63.169 20.736 64.177 20.76 ;
     RECT  63.821 23.232 64.177 23.928 ;
     RECT  64.177 20.544 64.217 21.672 ;
     RECT  64.115 25.104 64.289 27.624 ;
     RECT  63.893 16.512 64.325 16.536 ;
     RECT  63.877 69.552 64.357 71.256 ;
     RECT  63.929 40.08 64.361 40.392 ;
     RECT  64.361 40.08 64.433 40.104 ;
     RECT  64.357 69.504 64.441 71.256 ;
     RECT  64.177 23.232 64.451 24.12 ;
     RECT  64.451 24.096 64.512 24.12 ;
     RECT  63.929 41.376 64.717 42.216 ;
     RECT  63.565 62.736 64.753 62.76 ;
     RECT  64.109 13.824 64.793 14.232 ;
     RECT  63.461 57.456 64.793 58.152 ;
     RECT  64.393 49.488 64.861 49.512 ;
     RECT  64.289 26.832 64.865 27.624 ;
     RECT  64.289 25.104 64.892 25.656 ;
     RECT  64.609 34.752 64.933 34.776 ;
     RECT  63.205 47.856 64.933 48.12 ;
     RECT  64.933 34.656 64.937 34.776 ;
     RECT  64.753 62.64 64.937 62.76 ;
     RECT  64.549 68.976 64.937 69 ;
     RECT  64.892 25.056 64.979 25.656 ;
     RECT  63.929 38.208 65.005 38.76 ;
     RECT  64.94 53.568 65.027 53.592 ;
     RECT  64.115 12 65.045 12.024 ;
     RECT  64.217 21.648 65.045 21.672 ;
     RECT  63.749 54.72 65.045 54.744 ;
     RECT  65.005 37.632 65.077 38.856 ;
     RECT  64.933 47.28 65.153 48.12 ;
     RECT  64.865 26.832 65.297 26.856 ;
     RECT  64.793 14.208 65.315 14.232 ;
     RECT  65.077 37.2 65.329 38.856 ;
     RECT  64.717 41.376 65.329 42.456 ;
     RECT  64.861 49.488 65.333 49.56 ;
     RECT  65.257 17.088 65.341 17.112 ;
     RECT  64.937 34.656 65.369 34.68 ;
     RECT  65.293 11.472 65.401 11.496 ;
     RECT  64.217 20.544 65.405 20.568 ;
     RECT  65.401 11.424 65.437 11.496 ;
     RECT  64.069 9.648 65.473 9.672 ;
     RECT  64.441 70.128 65.473 71.256 ;
     RECT  65.473 9.264 65.513 9.672 ;
     RECT  65.329 37.056 65.513 38.856 ;
     RECT  63.781 50.736 65.513 51.48 ;
     RECT  63.745 6.864 65.545 6.888 ;
     RECT  63.317 7.968 65.545 7.992 ;
     RECT  65.513 37.056 65.545 38.712 ;
     RECT  65.437 10.848 65.549 11.496 ;
     RECT  65.293 66.672 65.549 66.696 ;
     RECT  65.317 68.4 65.549 68.424 ;
     RECT  65.545 6.864 65.585 7.992 ;
     RECT  65.549 11.424 65.585 11.496 ;
     RECT  65.513 9.264 65.603 9.288 ;
     RECT  65.513 50.736 65.621 51.384 ;
     RECT  65.585 7.392 65.629 7.992 ;
     RECT  65.585 11.472 65.693 11.496 ;
     RECT  65.329 40.272 65.693 42.456 ;
     RECT  65.629 7.968 65.729 7.992 ;
     RECT  65.693 41.616 65.729 42.456 ;
     RECT  64.793 57.456 65.756 57.48 ;
     RECT  65.041 58.656 65.756 58.68 ;
     RECT  65.221 44.64 65.765 44.664 ;
     RECT  65.756 57.456 65.797 58.68 ;
     RECT  65.437 59.856 65.797 59.88 ;
     RECT  64.115 29.04 65.837 29.064 ;
     RECT  65.729 41.904 65.837 42.456 ;
     RECT  65.797 57.456 65.843 59.88 ;
     RECT  65.843 57.456 65.905 57.48 ;
     RECT  64.979 25.632 65.945 25.656 ;
     RECT  65.905 49.728 66.017 49.752 ;
     RECT  65.843 59.04 66.131 59.88 ;
     RECT  65.621 50.736 66.265 50.856 ;
     RECT  66.409 34.944 66.625 34.968 ;
     RECT  66.265 50.544 66.661 50.856 ;
     RECT  65.473 69.552 66.697 71.256 ;
     RECT  65.905 56.88 66.709 57.48 ;
     RECT  66.625 34.944 66.805 35.256 ;
     RECT  65.545 36.576 66.805 38.712 ;
     RECT  65.693 40.272 66.985 40.44 ;
     RECT  65.153 47.664 67.057 48.12 ;
     RECT  66.805 34.944 67.201 38.712 ;
     RECT  66.661 50.544 67.201 51.72 ;
     RECT  65.869 32.976 67.208 33 ;
     RECT  67.201 34.416 67.208 38.712 ;
     RECT  66.985 40.032 67.208 40.44 ;
     RECT  65.837 41.904 67.208 41.928 ;
     RECT  66.013 43.632 67.208 43.656 ;
     RECT  67.057 47.664 67.208 48.456 ;
     RECT  67.201 50.544 67.208 52.2 ;
     RECT  65.977 53.232 67.208 53.256 ;
     RECT  65.473 55.296 67.208 55.32 ;
     RECT  66.709 56.496 67.208 57.48 ;
     RECT  66.131 59.04 67.208 59.064 ;
     RECT  66.697 68.976 67.208 71.256 ;
     RECT  67.208 2.148 67.312 71.256 ;
     RECT  67.312 2.418 67.504 71.256 ;
     RECT  67.504 57.6 67.601 57.624 ;
     RECT  67.504 54.528 67.619 55.464 ;
     RECT  67.504 33.36 67.637 34.44 ;
     RECT  67.504 41.088 67.637 41.928 ;
     RECT  67.504 66 67.645 66.024 ;
     RECT  67.504 46.368 67.709 46.584 ;
     RECT  67.619 54.528 67.709 54.696 ;
     RECT  67.637 33.36 67.715 34.008 ;
     RECT  67.715 33.36 67.753 33.384 ;
     RECT  67.504 49.344 67.763 49.368 ;
     RECT  67.504 51.6 67.763 52.2 ;
     RECT  67.709 54.624 67.817 54.696 ;
     RECT  67.504 37.584 67.961 37.608 ;
     RECT  67.504 68.976 68.393 71.256 ;
     RECT  67.817 54.672 68.501 54.696 ;
     RECT  67.637 41.088 68.573 41.544 ;
     RECT  68.393 69.648 68.609 71.256 ;
     RECT  68.573 41.52 68.681 41.544 ;
     RECT  67.709 46.368 68.681 46.392 ;
     RECT  68.677 62.88 68.773 62.904 ;
     RECT  68.773 62.64 68.861 62.904 ;
     RECT  68.861 62.688 68.963 62.904 ;
     RECT  68.963 62.688 68.969 62.808 ;
     RECT  68.609 70.08 69.517 71.16 ;
     RECT  69.613 69.504 69.697 69.528 ;
     RECT  69.517 70.56 70.067 71.16 ;
     RECT  70.067 70.704 70.451 71.16 ;
     RECT  70.451 71.136 70.553 71.16 ;
    LAYER M5 ;
     RECT  0.72 0.016 10.824 0.227 ;
     RECT  13.008 0.016 19.08 1.763 ;
     RECT  0.816 0.227 10.824 1.811 ;
     RECT  13.104 1.763 19.08 1.811 ;
     RECT  0.816 1.811 10.632 1.859 ;
     RECT  0.816 1.859 5.64 1.907 ;
     RECT  6.768 1.859 8.52 1.907 ;
     RECT  9.552 1.859 10.632 1.907 ;
     RECT  13.2 1.811 19.08 1.907 ;
     RECT  0.816 1.907 5.352 1.955 ;
     RECT  13.2 1.907 18.912 2.003 ;
     RECT  14.928 2.003 18.912 2.099 ;
     RECT  29.4 2.137 29.52 2.151 ;
     RECT  34.8 2.137 34.92 2.151 ;
     RECT  40.2 2.137 40.32 2.151 ;
     RECT  45.6 2.137 45.72 2.151 ;
     RECT  51 2.137 51.12 2.151 ;
     RECT  56.4 2.137 56.52 2.151 ;
     RECT  61.8 2.137 61.92 2.151 ;
     RECT  67.2 2.137 67.32 2.151 ;
     RECT  22.992 0.016 25.992 2.197 ;
     RECT  5.088 1.955 5.352 2.243 ;
     RECT  13.2 2.003 13.704 2.243 ;
     RECT  22.752 2.197 25.992 2.245 ;
     RECT  13.2 2.243 13.608 2.291 ;
     RECT  14.928 2.099 17.064 2.291 ;
     RECT  22.752 2.245 26.904 2.291 ;
     RECT  34.8 2.151 35.112 2.293 ;
     RECT  22.752 2.291 25.32 2.339 ;
     RECT  26.88 2.291 26.904 2.435 ;
     RECT  15.408 2.291 16.392 2.627 ;
     RECT  34.8 2.293 35.784 2.773 ;
     RECT  10.32 1.907 10.632 2.819 ;
     RECT  10.608 2.819 10.632 2.821 ;
     RECT  16.368 2.627 16.392 2.915 ;
     RECT  34.56 2.773 35.784 2.915 ;
     RECT  10.608 2.821 10.872 2.963 ;
     RECT  19.92 2.245 19.944 3.059 ;
     RECT  60 2.245 60.024 3.061 ;
     RECT  22.752 2.339 23.016 3.107 ;
     RECT  10.752 2.963 10.872 3.155 ;
     RECT  13.2 2.291 13.512 3.157 ;
     RECT  24 2.339 25.32 3.299 ;
     RECT  51 2.151 51.312 3.397 ;
     RECT  10.848 3.155 10.872 3.443 ;
     RECT  34.56 2.915 35.112 3.539 ;
     RECT  54.864 2.629 54.888 3.539 ;
     RECT  61.8 2.151 62.112 3.829 ;
     RECT  60 3.061 60.312 3.875 ;
     RECT  34.8 3.539 35.112 3.925 ;
     RECT  38.16 2.821 38.184 3.925 ;
     RECT  45.6 2.151 45.912 3.925 ;
     RECT  6.96 1.907 8.52 4.019 ;
     RECT  18.096 2.099 18.912 4.019 ;
     RECT  24 3.299 25.176 4.067 ;
     RECT  5.088 2.243 5.112 4.259 ;
     RECT  15.36 3.925 15.384 4.595 ;
     RECT  24 4.067 24.648 4.595 ;
     RECT  50.736 3.397 51.312 4.595 ;
     RECT  37.776 3.925 38.184 4.643 ;
     RECT  25.968 4.501 25.992 4.645 ;
     RECT  60.288 3.875 60.312 4.691 ;
     RECT  29.4 2.151 29.712 4.837 ;
     RECT  25.968 4.645 26.808 4.883 ;
     RECT  61.8 3.829 62.232 4.931 ;
     RECT  6.96 4.019 8.112 4.933 ;
     RECT  45.6 3.925 46.536 5.219 ;
     RECT  6.912 4.933 8.112 5.461 ;
     RECT  14.496 4.789 14.52 5.699 ;
     RECT  10.272 4.693 10.296 5.701 ;
     RECT  0.816 1.955 3.336 5.747 ;
     RECT  10.272 5.701 10.824 5.747 ;
     RECT  12.768 3.157 13.512 5.843 ;
     RECT  29.4 4.837 30.312 6.037 ;
     RECT  6.816 5.461 8.112 6.179 ;
     RECT  22.992 3.107 23.016 6.229 ;
     RECT  25.968 4.883 25.992 6.229 ;
     RECT  25.968 6.229 26.088 6.275 ;
     RECT  29.4 6.037 30.744 6.275 ;
     RECT  0.816 5.747 1.32 6.371 ;
     RECT  0.912 6.371 1.32 6.419 ;
     RECT  0.912 6.419 0.936 6.611 ;
     RECT  45.6 5.219 45.912 6.757 ;
     RECT  46.896 5.653 46.92 6.757 ;
     RECT  2.304 5.747 3.336 6.805 ;
     RECT  34.8 3.925 35.88 6.805 ;
     RECT  61.8 4.931 62.112 6.805 ;
     RECT  29.4 6.275 29.88 6.851 ;
     RECT  37.776 4.643 37.8 6.853 ;
     RECT  2.304 6.805 3.624 6.995 ;
     RECT  22.032 6.229 23.016 7.331 ;
     RECT  61.8 6.805 62.232 7.381 ;
     RECT  33.888 6.805 35.88 7.667 ;
     RECT  37.44 6.853 37.8 7.667 ;
     RECT  51 4.595 51.312 7.765 ;
     RECT  29.4 6.851 29.712 7.909 ;
     RECT  18.6 4.019 18.912 8.245 ;
     RECT  6.912 6.179 8.112 8.435 ;
     RECT  45.6 6.757 46.92 8.437 ;
     RECT  51 7.765 52.296 8.437 ;
     RECT  20.832 6.613 20.856 8.485 ;
     RECT  20.832 8.485 21.192 8.675 ;
     RECT  14.736 8.197 14.76 8.723 ;
     RECT  31.824 6.229 31.848 8.821 ;
     RECT  45.024 8.437 46.92 8.963 ;
     RECT  24 4.595 24.552 9.011 ;
     RECT  61.8 7.381 62.28 9.061 ;
     RECT  29.4 7.909 30.264 9.107 ;
     RECT  7.8 8.435 8.112 9.109 ;
     RECT  18.6 8.245 19.032 9.155 ;
     RECT  60.336 5.317 60.36 9.251 ;
     RECT  51 8.437 53.016 9.299 ;
     RECT  65.568 7.381 65.592 9.299 ;
     RECT  45.024 8.963 46.152 9.395 ;
     RECT  27.168 8.533 28.008 9.539 ;
     RECT  40.2 2.151 40.512 9.541 ;
     RECT  31.296 8.821 31.848 9.589 ;
     RECT  34.8 7.667 35.88 9.589 ;
     RECT  56.4 2.151 56.712 9.589 ;
     RECT  30.768 9.589 31.848 9.635 ;
     RECT  27.984 9.539 28.008 9.923 ;
     RECT  7.8 9.109 8.952 9.971 ;
     RECT  10.8 5.747 10.824 10.069 ;
     RECT  20.016 9.637 20.04 10.163 ;
     RECT  7.8 9.971 8.112 10.165 ;
     RECT  55.392 6.229 55.416 10.213 ;
     RECT  56.4 9.589 57.48 10.213 ;
     RECT  31.824 9.635 31.848 10.307 ;
     RECT  33.984 9.589 35.88 10.307 ;
     RECT  55.392 10.213 57.48 10.307 ;
     RECT  40.2 9.541 40.968 10.355 ;
     RECT  61.8 9.061 62.376 10.355 ;
     RECT  21.168 8.675 21.192 10.499 ;
     RECT  26.064 6.275 26.088 10.741 ;
     RECT  51 9.299 52.296 10.741 ;
     RECT  33.984 10.307 35.112 10.835 ;
     RECT  51 10.741 52.584 10.837 ;
     RECT  2.304 6.995 2.856 10.883 ;
     RECT  6.864 10.165 8.112 10.883 ;
     RECT  37.776 7.667 37.8 10.981 ;
     RECT  7.8 10.883 8.112 11.029 ;
     RECT  45.6 9.395 46.152 11.075 ;
     RECT  36.96 10.981 37.8 11.123 ;
     RECT  50.736 10.837 52.584 11.123 ;
     RECT  45.6 11.075 46.008 11.171 ;
     RECT  7.8 11.029 8.952 11.219 ;
     RECT  55.392 10.307 56.712 11.267 ;
     RECT  52.56 11.123 52.584 11.269 ;
     RECT  52.56 11.269 53.016 11.315 ;
     RECT  25.488 10.741 26.088 11.411 ;
     RECT  48.816 5.605 48.84 11.459 ;
     RECT  2.4 10.883 2.856 11.555 ;
     RECT  50.736 11.123 51.312 11.651 ;
     RECT  22.992 7.331 23.016 11.653 ;
     RECT  58.896 9.637 58.92 11.699 ;
     RECT  36.96 11.123 36.984 11.701 ;
     RECT  36.432 11.701 36.984 11.747 ;
     RECT  29.4 9.107 29.712 11.749 ;
     RECT  30.768 9.635 30.792 11.749 ;
     RECT  29.4 11.749 30.792 11.939 ;
     RECT  52.992 11.315 53.016 12.035 ;
     RECT  64.08 11.029 64.104 12.035 ;
     RECT  22.416 11.653 23.016 12.227 ;
     RECT  56.4 11.267 56.712 12.517 ;
     RECT  55.392 11.267 55.416 13.045 ;
     RECT  56.4 12.517 57.192 13.045 ;
     RECT  55.248 13.045 55.416 13.091 ;
     RECT  61.8 10.355 62.232 13.091 ;
     RECT  36.432 11.747 36.456 13.235 ;
     RECT  45.6 11.171 45.912 13.717 ;
     RECT  10.56 10.069 10.824 13.813 ;
     RECT  10.512 13.813 10.824 13.859 ;
     RECT  40.2 10.355 40.512 14.197 ;
     RECT  61.8 13.091 62.112 14.245 ;
     RECT  43.248 11.125 43.272 14.339 ;
     RECT  58.944 13.429 58.968 14.435 ;
     RECT  55.248 13.091 55.272 14.581 ;
     RECT  61.8 14.245 62.808 14.819 ;
     RECT  54.48 14.581 55.272 14.867 ;
     RECT  61.8 14.819 62.712 14.915 ;
     RECT  44.544 14.917 44.568 15.157 ;
     RECT  2.4 11.555 2.712 15.349 ;
     RECT  40.2 14.197 41.016 15.443 ;
     RECT  45.6 13.717 46.008 15.587 ;
     RECT  18.6 9.155 18.912 15.829 ;
     RECT  2.4 15.349 2.904 16.019 ;
     RECT  10.512 13.859 10.584 16.259 ;
     RECT  18.096 15.829 18.912 16.595 ;
     RECT  26.976 11.653 27 16.595 ;
     RECT  44.16 15.157 44.568 16.595 ;
     RECT  15.12 11.941 15.144 16.981 ;
     RECT  4.896 16.837 4.92 17.077 ;
     RECT  40.2 15.443 40.512 17.077 ;
     RECT  65.28 14.197 65.304 17.123 ;
     RECT  13.2 5.843 13.512 17.605 ;
     RECT  14.496 16.981 15.144 17.605 ;
     RECT  51 11.651 51.312 17.605 ;
     RECT  40.2 17.077 40.632 17.747 ;
     RECT  4.608 17.077 4.92 17.891 ;
     RECT  4.608 17.891 4.632 17.939 ;
     RECT  24 9.011 24.312 18.133 ;
     RECT  29.4 11.939 30.024 18.179 ;
     RECT  25.488 11.411 25.944 18.275 ;
     RECT  55.248 14.867 55.272 18.275 ;
     RECT  51 17.605 51.912 18.419 ;
     RECT  17.04 18.181 17.064 18.421 ;
     RECT  17.04 18.421 17.16 18.661 ;
     RECT  18.6 16.595 18.912 18.661 ;
     RECT  17.04 18.661 18.912 18.709 ;
     RECT  29.4 18.179 29.88 19.141 ;
     RECT  31.056 18.421 31.08 19.141 ;
     RECT  22.752 12.227 23.016 19.283 ;
     RECT  43.008 15.349 43.032 19.573 ;
     RECT  29.4 19.141 31.08 19.765 ;
     RECT  7.8 11.219 8.112 19.861 ;
     RECT  45.6 15.587 45.912 19.861 ;
     RECT  48.96 19.381 48.984 19.957 ;
     RECT  45.6 19.861 46.152 20.003 ;
     RECT  48.48 19.957 48.984 20.003 ;
     RECT  13.2 17.605 15.144 20.245 ;
     RECT  16.224 18.709 18.912 20.245 ;
     RECT  13.2 20.245 18.912 20.291 ;
     RECT  25.92 18.275 25.944 20.485 ;
     RECT  42.336 19.573 43.032 20.627 ;
     RECT  17.952 20.291 18.912 20.629 ;
     RECT  29.28 19.765 31.08 20.819 ;
     RECT  25.92 20.485 26.712 21.109 ;
     RECT  21.024 17.989 21.048 21.155 ;
     RECT  4.176 20.869 4.2 21.205 ;
     RECT  22.992 19.283 23.016 21.205 ;
     RECT  24 18.133 24.408 21.205 ;
     RECT  38.784 19.813 38.808 21.395 ;
     RECT  25.92 21.109 26.808 21.397 ;
     RECT  43.008 20.627 43.032 21.443 ;
     RECT  45.6 20.003 45.912 21.541 ;
     RECT  10.56 16.259 10.584 21.637 ;
     RECT  25.92 21.397 26.952 21.637 ;
     RECT  25.776 21.637 26.952 21.683 ;
     RECT  48.48 20.003 48.504 21.683 ;
     RECT  13.2 20.291 16.248 22.021 ;
     RECT  2.4 16.019 2.712 22.069 ;
     RECT  61.8 14.915 62.112 22.117 ;
     RECT  13.104 22.021 16.248 22.163 ;
     RECT  13.104 22.163 14.088 22.211 ;
     RECT  15.12 22.163 16.248 22.211 ;
     RECT  7.8 19.861 8.904 22.213 ;
     RECT  33.504 21.637 33.528 22.259 ;
     RECT  10.512 21.637 10.584 22.453 ;
     RECT  10.512 22.453 10.824 22.499 ;
     RECT  13.2 22.211 14.088 22.499 ;
     RECT  17.952 20.629 19.416 22.547 ;
     RECT  26.784 21.683 26.952 22.595 ;
     RECT  6.336 21.733 6.36 22.741 ;
     RECT  7.8 22.213 9.144 22.741 ;
     RECT  53.328 22.021 53.352 22.741 ;
     RECT  53.328 22.741 53.592 22.787 ;
     RECT  6.336 22.741 9.144 22.979 ;
     RECT  6.336 22.979 8.616 23.027 ;
     RECT  15.12 22.211 15.624 23.173 ;
     RECT  2.4 22.069 2.808 23.267 ;
     RECT  61.68 22.117 62.112 23.317 ;
     RECT  45.6 21.541 46.008 23.411 ;
     RECT  61.68 23.317 62.232 23.411 ;
     RECT  3.984 21.205 4.2 23.555 ;
     RECT  22.992 21.205 24.408 23.555 ;
     RECT  53.568 22.787 53.592 23.699 ;
     RECT  59.616 22.165 59.64 23.893 ;
     RECT  64.416 21.637 64.44 23.893 ;
     RECT  10.56 22.499 10.824 23.987 ;
     RECT  61.8 23.411 62.232 23.987 ;
     RECT  25.776 21.683 25.8 24.035 ;
     RECT  29.4 20.819 31.08 24.181 ;
     RECT  10.8 23.987 10.824 24.323 ;
     RECT  44.16 16.595 44.184 24.469 ;
     RECT  51 18.419 51.312 24.469 ;
     RECT  43.92 24.469 44.184 24.515 ;
     RECT  59.616 23.893 59.832 24.515 ;
     RECT  6.336 23.027 6.504 24.563 ;
     RECT  29.4 24.181 31.32 24.901 ;
     RECT  29.28 24.901 31.32 24.947 ;
     RECT  64.08 23.893 64.44 25.045 ;
     RECT  26.928 22.595 26.952 25.139 ;
     RECT  31.296 24.947 31.32 25.139 ;
     RECT  13.2 22.499 13.848 25.189 ;
     RECT  15.12 23.173 16.152 25.189 ;
     RECT  7.8 23.027 8.616 25.235 ;
     RECT  64.08 25.045 64.968 25.667 ;
     RECT  4.464 23.893 4.488 25.715 ;
     RECT  56.4 13.045 57.672 25.907 ;
     RECT  13.2 25.189 16.152 26.005 ;
     RECT  13.2 26.005 16.488 26.101 ;
     RECT  7.8 25.235 8.28 26.291 ;
     RECT  59.616 24.515 59.736 26.293 ;
     RECT  29.28 24.947 29.832 26.629 ;
     RECT  43.92 24.515 43.944 26.629 ;
     RECT  58.752 26.293 59.736 26.675 ;
     RECT  43.92 26.629 44.472 26.771 ;
     RECT  58.848 26.675 59.736 26.773 ;
     RECT  58.848 26.773 59.832 27.299 ;
     RECT  61.8 23.987 62.112 27.301 ;
     RECT  28.944 26.629 30.36 27.347 ;
     RECT  13.2 26.101 16.536 27.395 ;
     RECT  13.2 27.395 16.2 27.587 ;
     RECT  2.4 23.267 2.712 27.877 ;
     RECT  61.152 27.301 62.112 27.923 ;
     RECT  29.088 27.347 30.36 28.115 ;
     RECT  2.4 27.877 2.808 28.211 ;
     RECT  32.688 26.725 32.712 28.451 ;
     RECT  40.2 17.747 40.512 28.453 ;
     RECT  59.088 27.299 59.832 28.499 ;
     RECT  64.08 25.667 64.104 28.547 ;
     RECT  48.72 27.877 48.744 28.979 ;
     RECT  29.088 28.115 29.712 29.315 ;
     RECT  39.312 28.453 40.512 29.363 ;
     RECT  2.4 28.211 2.712 29.605 ;
     RECT  6.48 24.563 6.504 29.605 ;
     RECT  29.28 29.315 29.712 29.795 ;
     RECT  15.408 27.587 16.2 30.275 ;
     RECT  43.92 26.771 44.28 30.275 ;
     RECT  57.696 28.453 57.72 30.275 ;
     RECT  4.848 27.877 4.872 30.277 ;
     RECT  44.256 30.275 44.28 30.277 ;
     RECT  10.848 28.453 10.872 30.323 ;
     RECT  44.256 30.277 44.472 30.323 ;
     RECT  22.992 23.555 23.016 30.325 ;
     RECT  24 23.555 24.408 30.371 ;
     RECT  15.408 30.275 16.008 30.611 ;
     RECT  54 30.133 54.024 30.613 ;
     RECT  54 30.613 54.84 30.659 ;
     RECT  6.336 29.605 6.504 30.661 ;
     RECT  6.336 30.661 6.792 30.803 ;
     RECT  6.336 30.803 6.504 30.899 ;
     RECT  15.552 30.611 16.008 30.899 ;
     RECT  59.808 28.499 59.832 31.141 ;
     RECT  3.888 30.277 4.872 31.379 ;
     RECT  44.448 30.323 44.472 31.427 ;
     RECT  20.784 22.021 20.808 31.525 ;
     RECT  54.816 30.659 54.84 31.715 ;
     RECT  40.2 29.363 40.512 31.717 ;
     RECT  39.024 31.669 39.048 31.765 ;
     RECT  40.2 31.717 41.112 31.765 ;
     RECT  22.896 30.325 23.016 31.861 ;
     RECT  24 30.371 24.312 31.861 ;
     RECT  13.2 27.587 14.136 31.907 ;
     RECT  6.384 30.899 6.504 31.955 ;
     RECT  59.424 31.141 59.832 31.955 ;
     RECT  13.2 31.907 14.088 32.003 ;
     RECT  2.4 29.605 2.808 32.053 ;
     RECT  6.384 31.955 6.408 32.483 ;
     RECT  22.896 31.861 24.312 32.579 ;
     RECT  11.472 31.765 11.496 32.723 ;
     RECT  39.024 31.765 41.112 32.771 ;
     RECT  56.4 25.907 56.712 32.821 ;
     RECT  59.808 31.955 59.832 32.963 ;
     RECT  56.304 32.821 56.712 33.011 ;
     RECT  19.92 31.525 20.808 33.059 ;
     RECT  15.552 30.899 15.624 33.107 ;
     RECT  22.896 32.579 23.016 33.107 ;
     RECT  15.552 33.107 15.576 33.109 ;
     RECT  2.4 32.053 2.856 33.155 ;
     RECT  15.504 33.109 15.576 33.347 ;
     RECT  67.2 2.151 67.512 33.349 ;
     RECT  67.2 33.349 67.704 34.019 ;
     RECT  2.4 33.155 2.808 34.117 ;
     RECT  7.8 26.291 8.112 34.165 ;
     RECT  48.912 29.941 48.936 34.259 ;
     RECT  52.704 33.589 52.728 34.259 ;
     RECT  54.672 32.965 54.696 34.259 ;
     RECT  29.4 29.795 29.712 34.357 ;
     RECT  7.8 34.165 8.232 34.403 ;
     RECT  25.968 29.605 25.992 34.403 ;
     RECT  17.952 22.547 18.912 34.741 ;
     RECT  39.024 32.771 40.512 34.835 ;
     RECT  58.704 32.341 58.728 34.835 ;
     RECT  29.4 34.357 30.504 34.885 ;
     RECT  15.504 33.347 15.528 34.931 ;
     RECT  29.232 34.885 30.504 35.075 ;
     RECT  44.304 34.933 44.328 35.267 ;
     RECT  17.952 34.741 19.752 35.459 ;
     RECT  22.992 33.107 23.016 35.555 ;
     RECT  29.4 35.075 30.504 35.699 ;
     RECT  29.4 35.699 29.712 36.229 ;
     RECT  39.024 34.835 39.048 36.421 ;
     RECT  40.2 34.835 40.512 36.421 ;
     RECT  39.024 36.421 40.512 36.469 ;
     RECT  39.024 36.469 40.968 36.515 ;
     RECT  2.304 34.117 2.808 36.611 ;
     RECT  17.952 35.459 18.912 36.755 ;
     RECT  39.744 36.515 40.968 36.851 ;
     RECT  18.144 36.755 18.912 36.997 ;
     RECT  18.144 36.997 19.656 37.427 ;
     RECT  56.4 33.011 56.712 37.429 ;
     RECT  32.928 36.469 32.952 37.571 ;
     RECT  54.384 36.901 54.408 37.619 ;
     RECT  40.2 36.851 40.968 38.003 ;
     RECT  45.6 23.411 45.912 38.101 ;
     RECT  7.8 34.403 8.112 38.149 ;
     RECT  13.2 32.003 13.512 38.149 ;
     RECT  10.32 37.189 10.344 38.243 ;
     RECT  56.4 37.429 56.808 38.435 ;
     RECT  48.432 37.573 48.456 38.771 ;
     RECT  12.768 38.149 13.512 38.963 ;
     RECT  4.848 31.379 4.872 39.013 ;
     RECT  18.192 37.427 19.656 39.251 ;
     RECT  29.232 36.229 29.712 39.253 ;
     RECT  24 32.579 24.312 39.301 ;
     RECT  2.4 36.611 2.808 39.491 ;
     RECT  40.2 38.003 40.512 39.877 ;
     RECT  4.848 39.013 5.688 39.923 ;
     RECT  29.232 39.253 30.36 40.067 ;
     RECT  55.248 39.301 55.272 40.163 ;
     RECT  18.24 39.251 19.656 40.499 ;
     RECT  16.368 39.205 16.392 40.547 ;
     RECT  7.8 38.149 8.328 40.595 ;
     RECT  39.36 39.877 40.512 41.363 ;
     RECT  20.784 33.059 20.808 41.365 ;
     RECT  58.128 40.117 58.152 41.365 ;
     RECT  58.128 41.365 58.296 41.411 ;
     RECT  29.232 40.067 29.712 41.557 ;
     RECT  20.4 41.365 20.808 41.939 ;
     RECT  13.056 38.963 13.512 42.133 ;
     RECT  5.952 40.981 5.976 42.179 ;
     RECT  18.24 40.499 18.912 42.227 ;
     RECT  24 39.301 25.128 42.227 ;
     RECT  45.6 38.101 46.728 42.227 ;
     RECT  22.896 39.109 22.92 42.421 ;
     RECT  16.56 41.029 16.584 42.707 ;
     RECT  29.232 41.557 29.88 42.709 ;
     RECT  29.232 42.709 29.928 42.755 ;
     RECT  12.864 42.133 13.512 42.851 ;
     RECT  59.808 41.941 59.832 42.995 ;
     RECT  29.4 42.755 29.928 43.379 ;
     RECT  40.2 41.363 40.512 43.525 ;
     RECT  58.272 41.411 58.296 43.763 ;
     RECT  18.384 42.227 18.912 43.859 ;
     RECT  56.4 38.435 56.712 44.629 ;
     RECT  20.784 41.939 20.808 44.725 ;
     RECT  22.464 42.421 22.92 44.773 ;
     RECT  13.056 42.851 13.512 44.821 ;
     RECT  48.912 44.581 48.936 44.915 ;
     RECT  42.864 37.381 42.888 44.965 ;
     RECT  39.888 43.525 40.512 45.059 ;
     RECT  59.712 43.717 59.736 45.059 ;
     RECT  41.568 42.709 41.592 45.155 ;
     RECT  45.6 42.227 46.2 45.541 ;
     RECT  7.8 40.595 8.112 46.069 ;
     RECT  27.024 42.709 27.048 46.069 ;
     RECT  42.864 44.965 43.08 46.163 ;
     RECT  22.32 44.773 22.92 46.211 ;
     RECT  29.4 43.379 29.88 46.261 ;
     RECT  29.4 46.261 30.84 46.645 ;
     RECT  27.024 46.069 28.008 46.787 ;
     RECT  50.496 24.469 51.312 47.029 ;
     RECT  52.56 43.909 52.584 47.029 ;
     RECT  20.304 44.725 20.808 47.173 ;
     RECT  33.12 42.709 33.144 47.221 ;
     RECT  27.984 46.787 28.008 47.267 ;
     RECT  20.208 47.173 20.808 47.363 ;
     RECT  29.28 46.645 30.84 47.363 ;
     RECT  33.12 47.221 33.624 47.363 ;
     RECT  29.28 47.363 29.88 47.651 ;
     RECT  50.496 47.029 52.584 47.651 ;
     RECT  55.872 44.629 56.712 47.651 ;
     RECT  42.864 46.163 42.888 47.845 ;
     RECT  20.208 47.363 20.52 47.891 ;
     RECT  41.952 47.845 42.888 47.891 ;
     RECT  56.4 47.651 56.712 47.893 ;
     RECT  59.808 45.541 59.832 47.939 ;
     RECT  24 42.227 24.312 48.229 ;
     RECT  12.768 44.821 13.512 48.373 ;
     RECT  56.4 47.893 57.048 48.373 ;
     RECT  12.768 48.373 14.472 48.419 ;
     RECT  7.8 46.069 8.232 48.421 ;
     RECT  7.68 48.421 8.232 48.803 ;
     RECT  23.808 48.229 24.312 48.803 ;
     RECT  33.6 47.363 33.624 48.947 ;
     RECT  37.248 46.933 37.272 48.947 ;
     RECT  4.848 39.923 4.872 48.949 ;
     RECT  50.496 47.651 51.312 48.995 ;
     RECT  37.008 48.997 37.032 49.093 ;
     RECT  36.096 49.093 37.032 49.139 ;
     RECT  67.2 34.019 67.512 49.333 ;
     RECT  18.6 43.859 18.912 49.477 ;
     RECT  20.496 47.891 20.52 49.523 ;
     RECT  10.752 44.485 10.776 49.763 ;
     RECT  7.8 48.803 8.232 49.861 ;
     RECT  45.6 45.541 46.68 49.907 ;
     RECT  13.2 48.419 14.472 50.003 ;
     RECT  41.952 47.891 41.976 50.051 ;
     RECT  17.568 48.997 17.592 50.195 ;
     RECT  18.6 49.477 19.416 50.195 ;
     RECT  29.4 47.651 29.88 50.195 ;
     RECT  13.2 50.003 13.512 50.245 ;
     RECT  50.88 48.995 51.312 50.293 ;
     RECT  52.56 47.651 52.584 50.293 ;
     RECT  13.104 50.245 13.512 50.387 ;
     RECT  48.624 49.333 48.648 50.387 ;
     RECT  34.8 10.835 35.112 50.437 ;
     RECT  7.2 49.861 8.232 50.629 ;
     RECT  7.152 50.629 8.568 50.867 ;
     RECT  34.32 50.437 35.112 51.251 ;
     RECT  50.88 50.293 52.584 51.299 ;
     RECT  36.096 49.139 36.12 51.347 ;
     RECT  56.4 48.373 57.192 51.347 ;
     RECT  24 48.803 24.312 51.733 ;
     RECT  4.56 48.949 4.872 51.875 ;
     RECT  7.152 50.867 8.112 51.875 ;
     RECT  50.88 51.299 51.312 51.971 ;
     RECT  47.568 51.301 47.592 52.211 ;
     RECT  67.2 49.333 67.752 52.211 ;
     RECT  4.848 51.875 4.872 52.981 ;
     RECT  61.8 27.923 62.112 52.981 ;
     RECT  7.2 51.875 8.112 53.075 ;
     RECT  18.6 50.195 18.912 53.365 ;
     RECT  49.056 51.253 49.08 53.507 ;
     RECT  13.2 50.387 13.512 53.557 ;
     RECT  40.2 45.059 40.512 53.557 ;
     RECT  4.512 52.981 4.872 54.035 ;
     RECT  7.8 53.075 8.112 54.181 ;
     RECT  18.48 53.365 18.912 54.373 ;
     RECT  13.2 53.557 13.608 54.467 ;
     RECT  17.856 54.373 18.912 54.659 ;
     RECT  7.392 54.181 8.112 54.661 ;
     RECT  67.2 52.211 67.512 54.661 ;
     RECT  64.992 53.557 65.016 54.755 ;
     RECT  53.568 54.085 53.592 54.899 ;
     RECT  22.32 46.211 22.344 55.237 ;
     RECT  24 51.733 24.408 55.237 ;
     RECT  61.8 52.981 62.232 55.237 ;
     RECT  67.2 54.661 67.608 55.475 ;
     RECT  4.512 54.035 4.536 55.667 ;
     RECT  18.48 54.659 18.912 55.669 ;
     RECT  14.736 55.045 14.76 55.813 ;
     RECT  51 51.971 51.312 55.813 ;
     RECT  52.56 51.299 52.584 55.813 ;
     RECT  6.528 54.661 8.112 55.955 ;
     RECT  22.32 55.237 24.408 55.955 ;
     RECT  6.528 55.955 6.552 56.003 ;
     RECT  18.48 55.669 19.032 56.003 ;
     RECT  59.472 55.237 59.496 56.053 ;
     RECT  60.72 49.381 60.744 56.053 ;
     RECT  29.4 50.195 29.712 56.101 ;
     RECT  32.784 50.677 32.808 56.147 ;
     RECT  24 55.955 24.408 56.195 ;
     RECT  29.4 56.101 30.264 56.197 ;
     RECT  61.8 55.237 62.664 56.341 ;
     RECT  14.736 55.813 15.72 56.387 ;
     RECT  67.2 55.475 67.512 56.485 ;
     RECT  45.6 49.907 45.912 56.773 ;
     RECT  22.32 55.955 22.344 56.869 ;
     RECT  66.72 56.485 67.512 56.915 ;
     RECT  18.6 56.003 19.032 56.965 ;
     RECT  17.616 56.965 19.032 57.059 ;
     RECT  61.8 56.341 63.384 57.059 ;
     RECT  28.656 56.197 30.264 57.299 ;
     RECT  59.472 56.053 60.744 57.299 ;
     RECT  40.032 53.557 40.512 57.829 ;
     RECT  14.736 56.387 14.76 57.875 ;
     RECT  17.616 57.059 18.912 57.923 ;
     RECT  22.272 56.869 22.344 57.971 ;
     RECT  18.6 57.923 18.912 58.117 ;
     RECT  49.104 53.557 49.128 58.117 ;
     RECT  48.48 58.117 49.128 58.163 ;
     RECT  51 55.813 52.584 58.163 ;
     RECT  11.568 57.493 11.592 58.499 ;
     RECT  45.504 56.773 45.912 58.643 ;
     RECT  13.2 54.467 13.512 58.645 ;
     RECT  52.56 58.163 52.584 58.691 ;
     RECT  39.84 57.829 40.512 58.835 ;
     RECT  65.808 58.117 65.832 59.029 ;
     RECT  65.808 59.029 66.12 59.075 ;
     RECT  56.4 51.347 56.712 59.173 ;
     RECT  22.32 57.971 22.344 59.219 ;
     RECT  49.776 58.597 49.8 59.219 ;
     RECT  15.84 57.733 15.864 59.221 ;
     RECT  58.992 59.029 59.016 59.221 ;
     RECT  60.336 57.299 60.744 59.221 ;
     RECT  15.84 59.221 15.96 59.267 ;
     RECT  61.8 57.059 62.112 59.269 ;
     RECT  13.2 58.645 14.424 59.315 ;
     RECT  63.36 57.059 63.384 59.315 ;
     RECT  33.552 57.541 33.576 59.459 ;
     RECT  58.992 59.221 60.744 59.843 ;
     RECT  66.096 59.075 66.12 59.891 ;
     RECT  18.6 58.117 19.608 60.035 ;
     RECT  15.936 59.267 15.96 60.421 ;
     RECT  61.8 59.269 62.232 60.421 ;
     RECT  15.936 60.421 16.44 60.467 ;
     RECT  29.4 57.299 30.264 60.517 ;
     RECT  40.032 58.835 40.512 60.611 ;
     RECT  20.544 60.949 20.568 61.045 ;
     RECT  20.544 61.045 20.808 61.091 ;
     RECT  43.2 60.853 43.224 61.571 ;
     RECT  56.4 59.173 57.576 61.619 ;
     RECT  45.6 58.643 45.912 62.101 ;
     RECT  38.928 61.189 38.952 62.147 ;
     RECT  59.856 59.843 60.744 62.483 ;
     RECT  45.6 62.101 46.152 62.485 ;
     RECT  44.592 61.429 44.616 62.531 ;
     RECT  28.272 62.293 28.296 62.579 ;
     RECT  48.48 58.163 48.504 62.579 ;
     RECT  56.4 61.619 57 62.629 ;
     RECT  43.248 62.197 43.272 62.677 ;
     RECT  45.6 62.485 46.632 62.677 ;
     RECT  68.784 62.629 68.808 62.677 ;
     RECT  38.16 62.677 38.184 62.725 ;
     RECT  68.784 62.677 68.952 62.819 ;
     RECT  18.6 60.035 18.912 62.821 ;
     RECT  42.72 62.677 43.272 62.915 ;
     RECT  68.928 62.819 68.952 62.915 ;
     RECT  20.784 61.091 20.808 63.251 ;
     RECT  60.096 62.483 60.744 63.253 ;
     RECT  61.8 60.421 62.664 63.253 ;
     RECT  18.48 62.821 18.912 63.299 ;
     RECT  43.248 62.915 43.272 63.299 ;
     RECT  60.096 63.253 62.664 63.299 ;
     RECT  16.416 60.467 16.44 63.781 ;
     RECT  16.32 63.781 16.44 63.827 ;
     RECT  45.6 62.677 47.256 63.827 ;
     RECT  61.68 63.299 62.664 63.827 ;
     RECT  37.68 62.725 38.184 63.923 ;
     RECT  15.12 62.437 15.144 64.019 ;
     RECT  60.096 63.299 60.12 64.451 ;
     RECT  16.32 63.827 16.344 65.027 ;
     RECT  32.88 63.829 32.904 65.027 ;
     RECT  56.4 62.629 57.432 65.027 ;
     RECT  29.4 60.517 30.504 65.413 ;
     RECT  29.28 65.413 30.504 65.603 ;
     RECT  60.672 64.933 60.696 65.603 ;
     RECT  61.8 63.827 62.664 65.653 ;
     RECT  67.2 56.915 67.512 65.989 ;
     RECT  51 58.163 51.312 66.085 ;
     RECT  38.16 63.923 38.184 66.179 ;
     RECT  14.832 64.981 14.856 66.227 ;
     RECT  56.4 65.027 57 66.467 ;
     RECT  29.28 65.603 29.712 66.515 ;
     RECT  16.752 65.509 16.776 66.659 ;
     RECT  49.824 66.085 49.848 66.659 ;
     RECT  45.6 63.827 46.632 66.707 ;
     RECT  56.4 66.467 56.952 66.755 ;
     RECT  61.392 65.653 62.664 66.755 ;
     RECT  20.976 64.885 21 67.283 ;
     RECT  61.488 66.755 62.664 67.331 ;
     RECT  22.176 66.661 22.2 67.523 ;
     RECT  51 66.085 51.96 67.619 ;
     RECT  45.6 66.707 46.008 67.811 ;
     RECT  56.4 66.755 56.712 67.909 ;
     RECT  57.936 67.861 57.96 67.909 ;
     RECT  53.184 67.237 53.208 68.387 ;
     RECT  61.488 67.331 62.112 68.677 ;
     RECT  60.816 68.677 62.112 68.965 ;
     RECT  65.328 68.389 65.352 68.965 ;
     RECT  67.2 65.989 67.608 68.965 ;
     RECT  2.4 39.491 2.712 69.129 ;
     RECT  7.8 55.955 8.112 69.129 ;
     RECT  13.2 59.315 13.512 69.129 ;
     RECT  18.6 63.299 18.912 69.129 ;
     RECT  24 56.195 24.312 69.129 ;
     RECT  29.4 66.515 29.712 69.129 ;
     RECT  34.8 51.251 35.112 69.129 ;
     RECT  40.2 60.611 40.512 69.129 ;
     RECT  45.6 67.811 45.912 69.129 ;
     RECT  51 67.619 51.312 69.129 ;
     RECT  56.4 67.909 57.96 69.129 ;
     RECT  2.4 69.129 2.52 69.143 ;
     RECT  7.8 69.129 7.92 69.143 ;
     RECT  13.2 69.129 13.32 69.143 ;
     RECT  18.6 69.129 18.72 69.143 ;
     RECT  24 69.129 24.12 69.143 ;
     RECT  29.4 69.129 29.52 69.143 ;
     RECT  34.8 69.129 34.92 69.143 ;
     RECT  40.2 69.129 40.32 69.143 ;
     RECT  45.6 69.129 45.72 69.143 ;
     RECT  51 69.129 51.12 69.143 ;
     RECT  56.4 69.129 56.52 69.143 ;
     RECT  60.816 68.965 63.144 69.205 ;
     RECT  58.992 68.965 59.208 69.493 ;
     RECT  60.528 69.205 63.144 69.493 ;
     RECT  64.56 68.965 65.352 69.493 ;
     RECT  57.552 69.129 57.96 69.541 ;
     RECT  58.992 69.493 59.304 69.541 ;
     RECT  60.528 69.493 63.24 69.541 ;
     RECT  64.368 69.493 65.352 69.541 ;
     RECT  66.768 68.965 68.328 69.541 ;
     RECT  57.552 69.541 68.328 69.637 ;
     RECT  57.552 69.637 68.52 70.069 ;
     RECT  69.648 69.493 69.672 70.069 ;
     RECT  57.552 70.069 69.672 70.549 ;
     RECT  57.552 70.549 70.056 70.693 ;
     RECT  57.36 70.693 70.44 71.077 ;
     RECT  57.072 71.077 70.44 71.125 ;
     RECT  57.072 71.125 70.536 71.248 ;
     RECT  57.072 71.248 57.096 71.267 ;
     RECT  13.008 1.763 13.104 1.811 ;
     RECT  10.632 1.811 10.824 2.821 ;
     RECT  13.008 1.811 13.2 3.157 ;
     RECT  5.64 1.859 6.768 1.907 ;
     RECT  8.52 1.859 9.552 1.907 ;
     RECT  18.912 1.907 19.08 2.245 ;
     RECT  13.704 2.003 14.928 2.243 ;
     RECT  17.064 2.099 18.096 2.291 ;
     RECT  13.608 2.243 14.928 2.291 ;
     RECT  18.912 2.245 19.92 3.059 ;
     RECT  23.016 2.339 24 21.205 ;
     RECT  54.888 2.629 56.4 3.539 ;
     RECT  35.112 2.915 35.784 3.925 ;
     RECT  60.312 3.061 61.8 4.691 ;
     RECT  25.176 3.299 25.32 4.067 ;
     RECT  24.648 4.067 25.32 4.501 ;
     RECT  24.648 4.501 25.968 4.595 ;
     RECT  24.552 4.595 25.968 6.275 ;
     RECT  60.336 4.691 61.8 5.317 ;
     RECT  13.512 4.789 14.496 5.699 ;
     RECT  25.992 4.883 26.088 6.229 ;
     RECT  45.912 5.219 46.536 5.653 ;
     RECT  60.36 5.317 61.8 9.251 ;
     RECT  45.912 5.653 46.896 6.757 ;
     RECT  1.32 5.747 2.304 6.419 ;
     RECT  30.744 6.229 31.824 6.275 ;
     RECT  55.416 6.229 56.4 10.213 ;
     RECT  24.552 6.275 26.064 9.011 ;
     RECT  0.936 6.419 2.304 6.611 ;
     RECT  20.856 6.613 22.032 7.331 ;
     RECT  29.712 6.851 29.88 7.909 ;
     RECT  20.856 7.331 21.192 8.485 ;
     RECT  13.512 8.197 14.736 8.723 ;
     RECT  26.088 8.533 27.168 9.539 ;
     RECT  28.008 8.533 29.4 9.923 ;
     RECT  20.832 8.675 21.168 9.637 ;
     RECT  30.264 8.821 31.296 9.107 ;
     RECT  29.712 9.107 31.296 9.589 ;
     RECT  18.912 9.155 19.032 9.637 ;
     RECT  52.296 9.299 52.584 10.741 ;
     RECT  29.712 9.589 30.768 11.749 ;
     RECT  30.792 9.635 31.824 10.307 ;
     RECT  18.912 9.637 20.016 10.163 ;
     RECT  20.04 9.637 21.168 10.163 ;
     RECT  57.48 9.637 58.896 10.307 ;
     RECT  8.112 9.971 8.952 11.029 ;
     RECT  35.112 10.307 35.88 10.981 ;
     RECT  24.312 10.741 25.488 18.133 ;
     RECT  35.112 10.981 36.96 11.701 ;
     RECT  51.312 11.123 52.56 11.315 ;
     RECT  55.416 11.267 56.4 13.091 ;
     RECT  25.944 11.411 26.088 11.653 ;
     RECT  25.944 11.653 26.976 16.595 ;
     RECT  35.112 11.701 36.432 13.235 ;
     RECT  55.272 13.091 56.4 18.275 ;
     RECT  62.112 13.091 62.232 14.245 ;
     RECT  57.672 13.429 58.944 14.435 ;
     RECT  43.248 14.339 43.272 14.917 ;
     RECT  43.248 14.917 44.544 15.157 ;
     RECT  44.568 14.917 45.6 16.595 ;
     RECT  43.248 15.157 44.16 15.349 ;
     RECT  43.032 15.349 44.16 21.443 ;
     RECT  44.184 16.595 45.6 24.515 ;
     RECT  13.512 16.981 14.496 17.605 ;
     RECT  24.408 18.133 25.488 18.275 ;
     RECT  29.88 18.179 30.024 18.421 ;
     RECT  24.408 18.275 25.92 21.637 ;
     RECT  17.16 18.421 18.6 18.661 ;
     RECT  29.88 18.421 31.056 19.141 ;
     RECT  15.144 18.709 16.224 20.245 ;
     RECT  38.808 19.813 40.2 21.395 ;
     RECT  2.712 20.869 4.176 21.205 ;
     RECT  2.712 21.205 3.984 22.069 ;
     RECT  24.408 21.637 25.776 24.035 ;
     RECT  33.528 21.637 34.8 22.259 ;
     RECT  25.8 21.683 26.784 22.595 ;
     RECT  6.36 21.733 7.8 22.741 ;
     RECT  19.416 22.021 20.784 22.547 ;
     RECT  2.808 22.069 3.984 23.267 ;
     RECT  14.088 22.163 15.12 22.499 ;
     RECT  15.624 22.211 16.152 23.173 ;
     RECT  9.144 22.213 10.512 22.499 ;
     RECT  9.144 22.499 10.56 22.979 ;
     RECT  13.848 22.499 15.12 25.189 ;
     RECT  25.8 22.595 26.928 24.035 ;
     RECT  6.504 23.027 7.8 30.661 ;
     RECT  2.712 23.267 3.984 23.555 ;
     RECT  23.016 23.555 24 31.861 ;
     RECT  29.832 24.947 31.296 25.139 ;
     RECT  29.832 25.139 30.36 26.629 ;
     RECT  16.488 26.005 17.952 26.101 ;
     RECT  16.536 26.101 17.952 27.395 ;
     RECT  44.472 26.629 45.6 26.771 ;
     RECT  44.28 26.771 45.6 30.277 ;
     RECT  58.848 27.299 59.088 28.453 ;
     RECT  59.832 27.301 61.152 27.923 ;
     RECT  14.136 27.587 15.408 30.611 ;
     RECT  2.712 28.211 2.808 29.605 ;
     RECT  56.712 28.453 57.696 30.275 ;
     RECT  57.72 28.453 59.088 28.499 ;
     RECT  4.872 29.605 6.336 30.899 ;
     RECT  2.808 30.277 3.888 31.379 ;
     RECT  44.472 30.277 45.6 31.427 ;
     RECT  14.136 30.611 15.552 31.907 ;
     RECT  6.792 30.661 7.8 30.803 ;
     RECT  6.504 30.803 7.8 31.955 ;
     RECT  4.872 30.899 6.384 32.483 ;
     RECT  2.808 31.379 2.856 32.053 ;
     RECT  18.912 31.525 19.92 33.059 ;
     RECT  39.048 31.669 40.2 31.765 ;
     RECT  14.088 31.907 15.552 32.003 ;
     RECT  6.408 31.955 7.8 32.483 ;
     RECT  59.424 31.955 59.808 32.341 ;
     RECT  15.504 32.003 15.552 33.109 ;
     RECT  58.728 32.341 59.808 32.963 ;
     RECT  23.016 32.579 24 35.555 ;
     RECT  51.312 33.589 52.704 34.259 ;
     RECT  19.752 34.741 20.784 35.459 ;
     RECT  39.048 34.835 40.2 36.421 ;
     RECT  44.328 34.933 45.6 35.267 ;
     RECT  29.232 35.075 29.4 36.229 ;
     RECT  19.656 36.997 20.784 40.499 ;
     RECT  22.92 39.109 24 46.211 ;
     RECT  55.272 39.301 56.4 40.163 ;
     RECT  4.872 39.923 5.688 40.981 ;
     RECT  29.712 40.067 29.88 41.557 ;
     RECT  56.712 40.117 58.128 41.411 ;
     RECT  18.912 40.499 20.784 41.365 ;
     RECT  4.872 40.981 5.952 42.179 ;
     RECT  18.912 41.365 20.4 41.939 ;
     RECT  58.296 41.941 59.808 42.995 ;
     RECT  40.512 42.709 41.568 45.155 ;
     RECT  41.592 42.709 42.864 45.155 ;
     RECT  58.296 42.995 59.736 43.717 ;
     RECT  58.296 43.717 59.712 43.763 ;
     RECT  51.312 43.909 52.56 47.029 ;
     RECT  18.912 44.725 20.304 47.173 ;
     RECT  20.808 44.773 22.32 47.363 ;
     RECT  28.008 46.069 29.4 46.645 ;
     RECT  28.008 46.645 29.28 47.267 ;
     RECT  18.912 47.173 20.208 47.891 ;
     RECT  33.624 47.221 34.8 48.947 ;
     RECT  51.312 47.651 52.56 50.293 ;
     RECT  40.512 47.845 41.952 50.051 ;
     RECT  22.344 48.229 23.808 48.803 ;
     RECT  7.68 48.803 7.8 49.861 ;
     RECT  34.32 48.947 34.8 50.437 ;
     RECT  17.592 48.997 18.6 50.195 ;
     RECT  35.112 49.093 36.096 51.347 ;
     RECT  60.744 49.381 61.8 63.253 ;
     RECT  19.416 49.477 20.496 49.523 ;
     RECT  48.624 50.387 48.648 51.253 ;
     RECT  32.808 50.677 34.32 51.251 ;
     RECT  48.624 51.253 49.056 51.301 ;
     RECT  51.312 51.299 52.56 55.813 ;
     RECT  47.592 51.301 49.056 52.211 ;
     RECT  4.56 51.875 4.848 52.981 ;
     RECT  7.392 53.075 7.8 54.181 ;
     RECT  52.584 54.085 53.568 54.899 ;
     RECT  13.512 54.467 13.608 55.045 ;
     RECT  13.512 55.045 14.736 57.875 ;
     RECT  59.496 55.237 60.72 56.053 ;
     RECT  6.552 55.955 7.8 56.003 ;
     RECT  18.48 56.003 18.6 56.965 ;
     RECT  14.76 56.387 15.72 57.733 ;
     RECT  66.72 56.915 67.2 58.117 ;
     RECT  18.912 57.059 19.032 58.117 ;
     RECT  62.112 57.059 63.36 59.269 ;
     RECT  33.576 57.541 34.8 59.459 ;
     RECT  14.76 57.733 15.84 57.875 ;
     RECT  13.512 57.875 15.84 58.645 ;
     RECT  65.832 58.117 67.2 59.029 ;
     RECT  48.504 58.163 49.128 58.597 ;
     RECT  51.312 58.163 52.56 58.691 ;
     RECT  48.504 58.597 49.776 59.219 ;
     RECT  49.8 58.597 51 59.219 ;
     RECT  14.424 58.645 15.84 59.267 ;
     RECT  59.016 59.029 60.336 59.221 ;
     RECT  66.12 59.029 67.2 59.891 ;
     RECT  57.576 59.173 58.992 59.843 ;
     RECT  14.424 59.267 15.936 59.315 ;
     RECT  62.232 59.269 63.36 59.315 ;
     RECT  62.232 59.315 62.664 60.421 ;
     RECT  40.032 60.611 40.2 61.189 ;
     RECT  38.952 61.189 40.2 62.147 ;
     RECT  43.224 61.429 44.592 61.571 ;
     RECT  44.616 61.429 45.6 62.531 ;
     RECT  43.2 61.571 44.592 62.197 ;
     RECT  57 61.619 57.432 62.629 ;
     RECT  43.2 62.197 43.248 62.677 ;
     RECT  43.272 62.197 44.592 62.531 ;
     RECT  28.296 62.293 29.4 62.579 ;
     RECT  15.144 62.437 16.416 63.781 ;
     RECT  67.512 62.629 68.784 62.819 ;
     RECT  67.512 62.819 68.928 62.915 ;
     RECT  15.144 63.781 16.32 64.019 ;
     RECT  61.68 63.827 61.8 64.933 ;
     RECT  15.12 64.019 16.32 64.981 ;
     RECT  60.696 64.933 61.8 65.603 ;
     RECT  13.512 64.981 14.832 66.227 ;
     RECT  14.856 64.981 16.32 65.027 ;
     RECT  61.392 65.603 61.8 65.653 ;
     RECT  49.848 66.085 51 66.659 ;
     RECT  56.952 66.467 57 66.755 ;
     RECT  21 66.661 22.176 67.283 ;
     RECT  56.712 66.755 57 67.861 ;
     RECT  51.96 67.237 53.184 67.619 ;
     RECT  56.712 67.861 57.936 67.909 ;
     RECT  57.96 68.965 58.992 69.541 ;
     RECT  63.144 68.965 64.56 69.493 ;
     RECT  65.352 68.965 66.768 69.541 ;
     RECT  56.52 69.129 57.552 69.143 ;
     RECT  59.208 69.205 60.528 69.493 ;
     RECT  59.304 69.493 60.528 69.541 ;
     RECT  63.24 69.493 64.368 69.541 ;
     RECT  68.328 69.493 69.648 69.637 ;
     RECT  68.52 69.637 69.648 70.069 ;
  END
END ot_qwen_slab_pg_lanes
END LIBRARY
